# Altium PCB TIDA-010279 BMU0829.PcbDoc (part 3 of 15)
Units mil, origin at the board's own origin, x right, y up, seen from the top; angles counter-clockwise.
Board outline 11269.69 x 4438.98 mil, 4 copper layers (Top Layer, Signal Layer 1, Signal Layer 2, Bottom Layer), stack 61.6 mil thick; 1437 components, 728 nets, 3667 pads, 2806 vias.

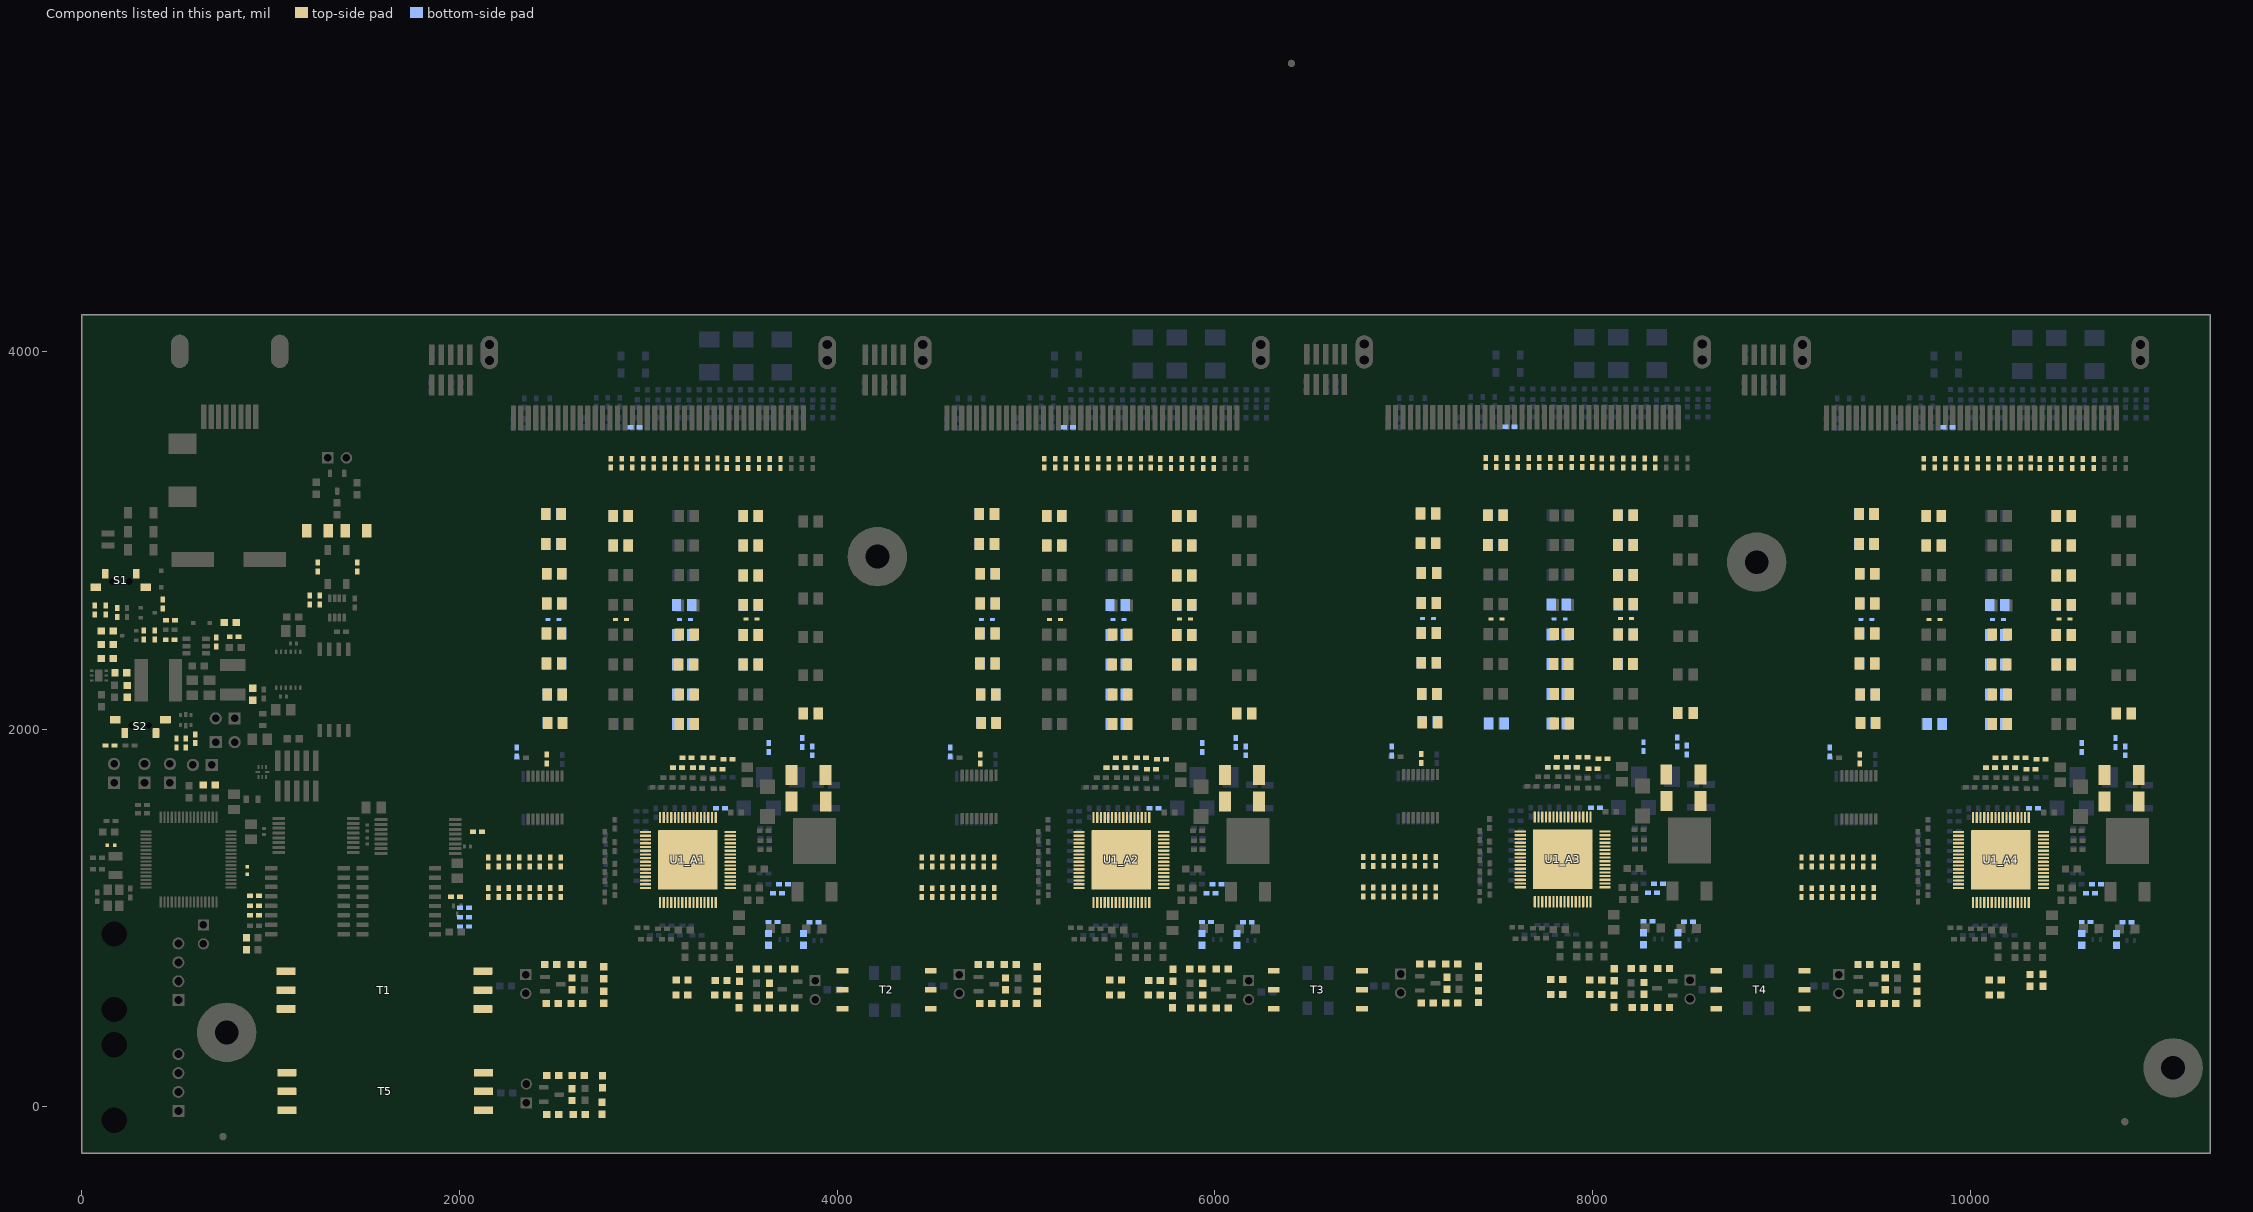
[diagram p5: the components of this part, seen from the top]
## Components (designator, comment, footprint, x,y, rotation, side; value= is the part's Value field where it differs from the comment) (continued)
R38_A3 "CRCW080568R0JNEA" 0805_HV 7490.51,2029.14 r0 bottom value=68 (schematic designator R38)
R38_A4 "CRCW080568R0JNEA" 0805_HV 9810.74,2025.93 r0 bottom value=68 (schematic designator R38)
R39_A1 "CRCW080568R0JNEA" 0805_HV 3189.11,2656.12 r0 bottom value=68 (schematic designator R39)
R39_A2 "CRCW080568R0JNEA" 0805_HV 5484.12,2656.12 r0 bottom value=68 (schematic designator R39)
R39_A3 "CRCW080568R0JNEA" 0805_HV 7820.72,2659.32 r0 bottom value=68 (schematic designator R39)
R39_A4 "CRCW080568R0JNEA" 0805_HV 10140.95,2656.12 r0 bottom value=68 (schematic designator R39)
R40_A1 "CRCW080568R0JNEA" 0805_HV 3859.45,2081.65 r0 top value=68 (schematic designator R40)
R40_A2 "CRCW080568R0JNEA" 0805_HV 6154.47,2081.65 r0 top value=68 (schematic designator R40)
R40_A3 "CRCW080568R0JNEA" 0805_HV 8491.06,2084.86 r0 top value=68 (schematic designator R40)
R40_A4 "CRCW080568R0JNEA" 0805_HV 10811.29,2081.65 r0 top value=68 (schematic designator R40)
R41_A1 "CRCW04021K00FKED" 0402 3699.67,3405.51 r270 top value=1.00k (schematic designator R41)
R41_A2 "CRCW04021K00FKED" 0402 5994.68,3405.51 r270 top value=1.00k (schematic designator R41)
R41_A3 "CRCW04021K00FKED" 0402 8331.28,3408.72 r270 top value=1.00k (schematic designator R41)
R41_A4 "CRCW04021K00FKED" 0402 10651.51,3405.51 r270 top value=1.00k (schematic designator R41)
R42_A1 "CRCW080568R0JNEA" 0805_HV 2498.12,3138.62 r0 top value=68 (schematic designator R42)
R42_A2 "CRCW080568R0JNEA" 0805_HV 4793.14,3138.62 r0 top value=68 (schematic designator R42)
R42_A3 "CRCW080568R0JNEA" 0805_HV 7129.74,3141.83 r0 top value=68 (schematic designator R42)
R42_A4 "CRCW080568R0JNEA" 0805_HV 9449.97,3138.62 r0 top value=68 (schematic designator R42)
R43_A1 "CRCW080568R0JNEA" 0805_HV 3204.12,2500.26 r0 top value=68 (schematic designator R43)
R43_A2 "CRCW080568R0JNEA" 0805_HV 5499.14,2500.26 r0 top value=68 (schematic designator R43)
R43_A3 "CRCW080568R0JNEA" 0805_HV 7835.73,2503.47 r0 top value=68 (schematic designator R43)
R43_A4 "CRCW080568R0JNEA" 0805_HV 10155.96,2500.26 r0 top value=68 (schematic designator R43)
R44_A1 "CRCW080568R0JNEA" 0805_HV 3541.98,3128.75 r0 top value=68 (schematic designator R44)
R44_A2 "CRCW080568R0JNEA" 0805_HV 5836.99,3128.75 r0 top value=68 (schematic designator R44)
R44_A3 "CRCW080568R0JNEA" 0805_HV 8173.59,3131.96 r0 top value=68 (schematic designator R44)
R44_A4 "CRCW080568R0JNEA" 0805_HV 10493.82,3128.75 r0 top value=68 (schematic designator R44)
R45_A1 "CRCW080568R0JNEA" 0805_HV 2498.12,2980.51 r0 top value=68 (schematic designator R45)
R45_A2 "CRCW080568R0JNEA" 0805_HV 4793.14,2980.51 r0 top value=68 (schematic designator R45)
R45_A3 "CRCW080568R0JNEA" 0805_HV 7129.74,2983.72 r0 top value=68 (schematic designator R45)
R45_A4 "CRCW080568R0JNEA" 0805_HV 9449.97,2980.51 r0 top value=68 (schematic designator R45)
R46_A1 "CRCW080568R0JNEA" 0805_HV 3189.11,2498.57 r0 bottom value=68 (schematic designator R46)
R46_A2 "CRCW080568R0JNEA" 0805_HV 5484.12,2498.57 r0 bottom value=68 (schematic designator R46)
R46_A3 "CRCW080568R0JNEA" 0805_HV 7820.72,2501.78 r0 bottom value=68 (schematic designator R46)
R46_A4 "CRCW080568R0JNEA" 0805_HV 10140.95,2498.57 r0 bottom value=68 (schematic designator R46)
R47_A1 "CRCW080568R0JNEA" 0805_HV 3541.98,2971.21 r0 top value=68 (schematic designator R47)
R47_A2 "CRCW080568R0JNEA" 0805_HV 5836.99,2971.21 r0 top value=68 (schematic designator R47)
R47_A3 "CRCW080568R0JNEA" 0805_HV 8173.59,2974.42 r0 top value=68 (schematic designator R47)
R47_A4 "CRCW080568R0JNEA" 0805_HV 10493.82,2971.21 r0 top value=68 (schematic designator R47)
R48_A1 "CRCW080568R0JNEA" 0805_HV 2495.94,3138.62 r0 bottom value=68 (schematic designator R48)
R48_A2 "CRCW080568R0JNEA" 0805_HV 4790.96,3138.62 r0 bottom value=68 (schematic designator R48)
R48_A3 "CRCW080568R0JNEA" 0805_HV 7127.56,3141.83 r0 bottom value=68 (schematic designator R48)
R48_A4 "CRCW080568R0JNEA" 0805_HV 9447.79,3138.62 r0 bottom value=68 (schematic designator R48)
R49_A1 "CRCW080568R0JNEA" 0805_HV 3189.11,2341.02 r0 bottom value=68 (schematic designator R49)
R49_A2 "CRCW080568R0JNEA" 0805_HV 5484.12,2341.02 r0 bottom value=68 (schematic designator R49)
R49_A3 "CRCW080568R0JNEA" 0805_HV 7820.72,2344.23 r0 bottom value=68 (schematic designator R49)
R49_A4 "CRCW080568R0JNEA" 0805_HV 10140.95,2341.02 r0 bottom value=68 (schematic designator R49)
R50_A1 "CRCW080568R0JNEA" 0805_HV 3543.08,3128.75 r0 bottom value=68 (schematic designator R50)
R50_A2 "CRCW080568R0JNEA" 0805_HV 5838.1,3128.75 r0 bottom value=68 (schematic designator R50)
R50_A3 "CRCW080568R0JNEA" 0805_HV 8174.69,3131.96 r0 bottom value=68 (schematic designator R50)
R50_A4 "CRCW080568R0JNEA" 0805_HV 10494.92,3128.75 r0 bottom value=68 (schematic designator R50)
R51_A1 "CRCW04021K00FKED" 0402 3642.8,3405.51 r270 top value=1.00k (schematic designator R51)
R51_A2 "CRCW04021K00FKED" 0402 5937.82,3405.51 r270 top value=1.00k (schematic designator R51)
R51_A3 "CRCW04021K00FKED" 0402 8274.41,3408.72 r270 top value=1.00k (schematic designator R51)
R51_A4 "CRCW04021K00FKED" 0402 10594.64,3405.51 r270 top value=1.00k (schematic designator R51)
R52_A1 "CRCW080568R0JNEA" 0805_HV 2495.94,2980.51 r0 bottom value=68 (schematic designator R52)
R52_A2 "CRCW080568R0JNEA" 0805_HV 4790.96,2980.51 r0 bottom value=68 (schematic designator R52)
R52_A3 "CRCW080568R0JNEA" 0805_HV 7127.56,2983.72 r0 bottom value=68 (schematic designator R52)
R52_A4 "CRCW080568R0JNEA" 0805_HV 9447.79,2980.51 r0 bottom value=68 (schematic designator R52)
R53_A1 "CRCW080568R0JNEA" 0805_HV 3201.6,2341.02 r0 top value=68 (schematic designator R53)
R53_A2 "CRCW080568R0JNEA" 0805_HV 5496.62,2341.02 r0 top value=68 (schematic designator R53)
R53_A3 "CRCW080568R0JNEA" 0805_HV 7833.21,2344.23 r0 top value=68 (schematic designator R53)
R53_A4 "CRCW080568R0JNEA" 0805_HV 10153.44,2341.02 r0 top value=68 (schematic designator R53)
R54_A1 "CRCW080568R0JNEA" 0805_HV 3543.08,2971.21 r0 bottom value=68 (schematic designator R54)
R54_A2 "CRCW080568R0JNEA" 0805_HV 5838.1,2971.21 r0 bottom value=68 (schematic designator R54)
R54_A3 "CRCW080568R0JNEA" 0805_HV 8174.69,2974.42 r0 bottom value=68 (schematic designator R54)
R54_A4 "CRCW080568R0JNEA" 0805_HV 10494.92,2971.21 r0 bottom value=68 (schematic designator R54)
R55_A1 "CRCW080568R0JNEA" 0805_HV 2501.64,2822.4 r0 top value=68 (schematic designator R55)
R55_A2 "CRCW080568R0JNEA" 0805_HV 4796.66,2822.4 r0 top value=68 (schematic designator R55)
R55_A3 "CRCW080568R0JNEA" 0805_HV 7133.26,2825.61 r0 top value=68 (schematic designator R55)
R55_A4 "CRCW080568R0JNEA" 0805_HV 9453.49,2822.4 r0 top value=68 (schematic designator R55)
R56_A1 "CRCW080568R0JNEA" 0805_HV 3204.12,2183.48 r0 top value=68 (schematic designator R56)
R56_A2 "CRCW080568R0JNEA" 0805_HV 5499.14,2183.48 r0 top value=68 (schematic designator R56)
R56_A3 "CRCW080568R0JNEA" 0805_HV 7835.73,2186.69 r0 top value=68 (schematic designator R56)
R56_A4 "CRCW080568R0JNEA" 0805_HV 10155.96,2183.48 r0 top value=68 (schematic designator R56)
R57_A1 "CRCW080568R0JNEA" 0805_HV 3542.76,2658.37 r0 top value=68 (schematic designator R57)
R57_A2 "CRCW080568R0JNEA" 0805_HV 5837.78,2658.37 r0 top value=68 (schematic designator R57)
R57_A3 "CRCW080568R0JNEA" 0805_HV 8174.38,2661.58 r0 top value=68 (schematic designator R57)
R57_A4 "CRCW080568R0JNEA" 0805_HV 10494.6,2658.37 r0 top value=68 (schematic designator R57)
R58_A1 "CRCW080568R0JNEA" 0805_HV 2501.39,2822.4 r0 bottom value=68 (schematic designator R58)
R58_A2 "CRCW080568R0JNEA" 0805_HV 4796.41,2822.4 r0 bottom value=68 (schematic designator R58)
R58_A3 "CRCW080568R0JNEA" 0805_HV 7133.01,2825.61 r0 bottom value=68 (schematic designator R58)
R58_A4 "CRCW080568R0JNEA" 0805_HV 9453.24,2822.4 r0 bottom value=68 (schematic designator R58)
R59_A1 "CRCW080568R0JNEA" 0805_HV 3203.57,2025.93 r0 top value=68 (schematic designator R59)
R59_A2 "CRCW080568R0JNEA" 0805_HV 5498.58,2025.93 r0 top value=68 (schematic designator R59)
R59_A3 "CRCW080568R0JNEA" 0805_HV 7835.18,2029.14 r0 top value=68 (schematic designator R59)
R59_A4 "CRCW080568R0JNEA" 0805_HV 10155.41,2025.93 r0 top value=68 (schematic designator R59)
R60_A1 "CRCW080568R0JNEA" 0805_HV 3543.08,2656.12 r0 bottom value=68 (schematic designator R60)
R60_A2 "CRCW080568R0JNEA" 0805_HV 5838.1,2656.12 r0 bottom value=68 (schematic designator R60)
R60_A3 "CRCW080568R0JNEA" 0805_HV 8174.69,2659.32 r0 bottom value=68 (schematic designator R60)
R60_A4 "CRCW080568R0JNEA" 0805_HV 10494.92,2656.12 r0 bottom value=68 (schematic designator R60)
R61_A1 "CRCW04021K00FKED" 0402 3585.93,3405.51 r270 top value=1.00k (schematic designator R61)
R61_A2 "CRCW04021K00FKED" 0402 5880.95,3405.51 r270 top value=1.00k (schematic designator R61)
R61_A3 "CRCW04021K00FKED" 0402 8217.54,3408.72 r270 top value=1.00k (schematic designator R61)
R61_A4 "CRCW04021K00FKED" 0402 10537.77,3405.51 r270 top value=1.00k (schematic designator R61)
R62_A1 "CRCW080568R0JNEA" 0805_HV 2501.11,2664.29 r0 top value=68 (schematic designator R62)
R62_A2 "CRCW080568R0JNEA" 0805_HV 4796.13,2664.29 r0 top value=68 (schematic designator R62)
R62_A3 "CRCW080568R0JNEA" 0805_HV 7132.73,2667.5 r0 top value=68 (schematic designator R62)
R62_A4 "CRCW080568R0JNEA" 0805_HV 9452.96,2664.29 r0 top value=68 (schematic designator R62)
R63_A1 "CRCW080568R0JNEA" 0805_HV 3189.11,2025.93 r0 bottom value=68 (schematic designator R63)
R63_A2 "CRCW080568R0JNEA" 0805_HV 5484.12,2025.93 r0 bottom value=68 (schematic designator R63)
R63_A3 "CRCW080568R0JNEA" 0805_HV 7820.72,2029.14 r0 bottom value=68 (schematic designator R63)
R63_A4 "CRCW080568R0JNEA" 0805_HV 10140.95,2025.93 r0 bottom value=68 (schematic designator R63)
R64_A1 "CRCW080568R0JNEA" 0805_HV 3541.98,2813.66 r0 top value=68 (schematic designator R64)
R64_A2 "CRCW080568R0JNEA" 0805_HV 5836.99,2813.66 r0 top value=68 (schematic designator R64)
R64_A3 "CRCW080568R0JNEA" 0805_HV 8173.59,2816.87 r0 top value=68 (schematic designator R64)
R64_A4 "CRCW080568R0JNEA" 0805_HV 10493.82,2813.66 r0 top value=68 (schematic designator R64)
R65_A1 "CRCW04021K00FKED" 0402 3529.06,3405.51 r270 top value=1.00k (schematic designator R65)
R65_A2 "CRCW04021K00FKED" 0402 5824.08,3405.51 r270 top value=1.00k (schematic designator R65)
R65_A3 "CRCW04021K00FKED" 0402 8160.68,3408.72 r270 top value=1.00k (schematic designator R65)
R65_A4 "CRCW04021K00FKED" 0402 10480.91,3405.51 r270 top value=1.00k (schematic designator R65)
R66_A1 "CRCW080568R0JNEA" 0805_HV 2501.39,2664.29 r0 bottom value=68 (schematic designator R66)
R66_A2 "CRCW080568R0JNEA" 0805_HV 4796.41,2664.29 r0 bottom value=68 (schematic designator R66)
R66_A3 "CRCW080568R0JNEA" 0805_HV 7133.01,2667.5 r0 bottom value=68 (schematic designator R66)
R66_A4 "CRCW080568R0JNEA" 0805_HV 9453.24,2664.29 r0 bottom value=68 (schematic designator R66)
R67_A1 "CRCW080568R0JNEA" 0805_HV 3189.11,2183.48 r0 bottom value=68 (schematic designator R67)
R67_A2 "CRCW080568R0JNEA" 0805_HV 5484.12,2183.48 r0 bottom value=68 (schematic designator R67)
R67_A3 "CRCW080568R0JNEA" 0805_HV 7820.72,2186.69 r0 bottom value=68 (schematic designator R67)
R67_A4 "CRCW080568R0JNEA" 0805_HV 10140.95,2183.48 r0 bottom value=68 (schematic designator R67)
R68_A1 "CRCW080568R0JNEA" 0805_HV 3543.08,2813.66 r0 bottom value=68 (schematic designator R68)
R68_A2 "CRCW080568R0JNEA" 0805_HV 5838.1,2813.66 r0 bottom value=68 (schematic designator R68)
R68_A3 "CRCW080568R0JNEA" 0805_HV 8174.69,2816.87 r0 bottom value=68 (schematic designator R68)
R68_A4 "CRCW080568R0JNEA" 0805_HV 10494.92,2813.66 r0 bottom value=68 (schematic designator R68)
R69_A1 "CRCW080568R0JNEA" 0805_HV 2500.37,2506.18 r0 top value=68 (schematic designator R69)
R69_A2 "CRCW080568R0JNEA" 0805_HV 4795.39,2506.18 r0 top value=68 (schematic designator R69)
R69_A3 "CRCW080568R0JNEA" 0805_HV 7131.98,2509.39 r0 top value=68 (schematic designator R69)
R69_A4 "CRCW080568R0JNEA" 0805_HV 9452.21,2506.18 r0 top value=68 (schematic designator R69)
R70_A1 "CRCW080568R0JNEA" 0805_HV 2854.76,3128.75 r0 bottom value=68 (schematic designator R70)
R70_A2 "CRCW080568R0JNEA" 0805_HV 5149.78,3128.75 r0 bottom value=68 (schematic designator R70)
R70_A3 "CRCW080568R0JNEA" 0805_HV 7486.37,3131.96 r0 bottom value=68 (schematic designator R70)
R70_A4 "CRCW080568R0JNEA" 0805_HV 9806.6,3128.75 r0 bottom value=68 (schematic designator R70)
R71_A1 "CRCW080568R0JNEA" 0805_HV 3543.08,2341.02 r0 bottom value=68 (schematic designator R71)
R71_A2 "CRCW080568R0JNEA" 0805_HV 5838.1,2341.02 r0 bottom value=68 (schematic designator R71)
R71_A3 "CRCW080568R0JNEA" 0805_HV 8174.69,2344.23 r0 bottom value=68 (schematic designator R71)
R71_A4 "CRCW080568R0JNEA" 0805_HV 10494.92,2341.02 r0 bottom value=68 (schematic designator R71)
R72_A1 "CRCW080568R0JNEA" 0805_HV 2501.39,2505.07 r0 bottom value=68 (schematic designator R72)
R72_A2 "CRCW080568R0JNEA" 0805_HV 4796.41,2505.07 r0 bottom value=68 (schematic designator R72)
R72_A3 "CRCW080568R0JNEA" 0805_HV 7133.01,2508.28 r0 bottom value=68 (schematic designator R72)
R72_A4 "CRCW080568R0JNEA" 0805_HV 9453.24,2505.07 r0 bottom value=68 (schematic designator R72)
R73_A1 "CRCW080568R0JNEA" 0805_HV 2853.39,3128.75 r0 top value=68 (schematic designator R73)
R73_A2 "CRCW080568R0JNEA" 0805_HV 5148.41,3128.75 r0 top value=68 (schematic designator R73)
R73_A3 "CRCW080568R0JNEA" 0805_HV 7485,3131.96 r0 top value=68 (schematic designator R73)
R73_A4 "CRCW080568R0JNEA" 0805_HV 9805.23,3128.75 r0 top value=68 (schematic designator R73)
R74_A1 "CRCW080568R0JNEA" 0805_HV 3541.29,2341.02 r0 top value=68 (schematic designator R74)
R74_A2 "CRCW080568R0JNEA" 0805_HV 5836.3,2341.02 r0 top value=68 (schematic designator R74)
R74_A3 "CRCW080568R0JNEA" 0805_HV 8172.9,2344.23 r0 top value=68 (schematic designator R74)
R74_A4 "CRCW080568R0JNEA" 0805_HV 10493.13,2341.02 r0 top value=68 (schematic designator R74)
R75_A1 "CRCW04021K00FKED" 0402 3472.2,3405.51 r270 top value=1.00k (schematic designator R75)
R75_A2 "CRCW04021K00FKED" 0402 5767.21,3405.51 r270 top value=1.00k (schematic designator R75)
R75_A3 "CRCW04021K00FKED" 0402 8103.81,3408.72 r270 top value=1.00k (schematic designator R75)
R75_A4 "CRCW04021K00FKED" 0402 10424.04,3405.51 r270 top value=1.00k (schematic designator R75)
R76_A1 "CRCW080568R0JNEA" 0805_HV 2501.39,2348.07 r0 bottom value=68 (schematic designator R76)
R76_A2 "CRCW080568R0JNEA" 0805_HV 4796.41,2348.07 r0 bottom value=68 (schematic designator R76)
R76_A3 "CRCW080568R0JNEA" 0805_HV 7133.01,2351.28 r0 bottom value=68 (schematic designator R76)
R76_A4 "CRCW080568R0JNEA" 0805_HV 9453.24,2348.07 r0 bottom value=68 (schematic designator R76)
R77_A1 "CRCW080568R0JNEA" 0805_HV 2854.76,2971.21 r0 bottom value=68 (schematic designator R77)
R77_A2 "CRCW080568R0JNEA" 0805_HV 5149.78,2971.21 r0 bottom value=68 (schematic designator R77)
R77_A3 "CRCW080568R0JNEA" 0805_HV 7486.37,2974.42 r0 bottom value=68 (schematic designator R77)
R77_A4 "CRCW080568R0JNEA" 0805_HV 9806.6,2971.21 r0 bottom value=68 (schematic designator R77)
R78_A1 "CRCW080568R0JNEA" 0805_HV 3542.76,2498.57 r0 top value=68 (schematic designator R78)
R78_A2 "CRCW080568R0JNEA" 0805_HV 5837.78,2498.57 r0 top value=68 (schematic designator R78)
R78_A3 "CRCW080568R0JNEA" 0805_HV 8174.38,2501.78 r0 top value=68 (schematic designator R78)
R78_A4 "CRCW080568R0JNEA" 0805_HV 10494.6,2498.57 r0 top value=68 (schematic designator R78)
R79_A1 "CRCW0402511RFKED" 0402 3366.1,3408.84 r90 top value=511 (schematic designator R79)
R79_A2 "CRCW0402511RFKED" 0402 5661.12,3408.84 r90 top value=511 (schematic designator R79)
R79_A3 "CRCW0402511RFKED" 0402 7997.72,3412.05 r90 top value=511 (schematic designator R79)
R79_A4 "CRCW0402511RFKED" 0402 10317.95,3408.84 r90 top value=511 (schematic designator R79)
R80_A1 "CRCW080568R0JNEA" 0805_HV 2500.37,2348.07 r0 top value=68 (schematic designator R80)
R80_A2 "CRCW080568R0JNEA" 0805_HV 4795.39,2348.07 r0 top value=68 (schematic designator R80)
R80_A3 "CRCW080568R0JNEA" 0805_HV 7131.98,2351.28 r0 top value=68 (schematic designator R80)
R80_A4 "CRCW080568R0JNEA" 0805_HV 9452.21,2348.07 r0 top value=68 (schematic designator R80)
R81_A1 "CRCW080568R0JNEA" 0805_HV 2853.39,2971.21 r0 top value=68 (schematic designator R81)
R81_A2 "CRCW080568R0JNEA" 0805_HV 5148.41,2971.21 r0 top value=68 (schematic designator R81)
R81_A3 "CRCW080568R0JNEA" 0805_HV 7485,2974.42 r0 top value=68 (schematic designator R81)
R81_A4 "CRCW080568R0JNEA" 0805_HV 9805.23,2971.21 r0 top value=68 (schematic designator R81)
R82_A1 "CRCW080568R0JNEA" 0805_HV 3543.08,2498.57 r0 bottom value=68 (schematic designator R82)
R82_A2 "CRCW080568R0JNEA" 0805_HV 5838.1,2498.57 r0 bottom value=68 (schematic designator R82)
R82_A3 "CRCW080568R0JNEA" 0805_HV 8174.69,2501.78 r0 bottom value=68 (schematic designator R82)
R82_A4 "CRCW080568R0JNEA" 0805_HV 10494.92,2498.57 r0 bottom value=68 (schematic designator R82)
R83_A1 "CRCW04021K00FKED" 0402 3415.33,3405.51 r270 top value=1.00k (schematic designator R83)
R83_A2 "CRCW04021K00FKED" 0402 5710.34,3405.51 r270 top value=1.00k (schematic designator R83)
R83_A3 "CRCW04021K00FKED" 0402 8046.94,3408.72 r270 top value=1.00k (schematic designator R83)
R83_A4 "CRCW04021K00FKED" 0402 10367.17,3405.51 r270 top value=1.00k (schematic designator R83)
R84_A1 "CRCW080568R0JNEA" 0805_HV 2506.8,2031.85 r0 top value=68 (schematic designator R84)
R84_A2 "CRCW080568R0JNEA" 0805_HV 4801.81,2031.85 r0 top value=68 (schematic designator R84)
R84_A3 "CRCW080568R0JNEA" 0805_HV 7138.41,2035.06 r0 top value=68 (schematic designator R84)
R84_A4 "CRCW080568R0JNEA" 0805_HV 9458.64,2031.85 r0 top value=68 (schematic designator R84)
R85_A1 "CRCW080568R0JNEA" 0805_HV 2504.54,2183.48 r0 bottom value=68 (schematic designator R85)
R85_A2 "CRCW080568R0JNEA" 0805_HV 4799.55,2183.48 r0 bottom value=68 (schematic designator R85)
R85_A3 "CRCW080568R0JNEA" 0805_HV 7136.15,2186.69 r0 bottom value=68 (schematic designator R85)
R85_A4 "CRCW080568R0JNEA" 0805_HV 9456.38,2183.48 r0 bottom value=68 (schematic designator R85)
R86_A1 "CRCW080568R0JNEA" 0805_HV 2503.71,2183.48 r0 top value=68 (schematic designator R86)
R86_A2 "CRCW080568R0JNEA" 0805_HV 4798.73,2183.48 r0 top value=68 (schematic designator R86)
R86_A3 "CRCW080568R0JNEA" 0805_HV 7135.32,2186.69 r0 top value=68 (schematic designator R86)
R86_A4 "CRCW080568R0JNEA" 0805_HV 9455.55,2183.48 r0 top value=68 (schematic designator R86)
R87_A1 "CRCW080568R0JNEA" 0805_HV 2504.54,2033.6 r0 bottom value=68 (schematic designator R87)
R87_A2 "CRCW080568R0JNEA" 0805_HV 4799.55,2033.6 r0 bottom value=68 (schematic designator R87)
R87_A3 "CRCW080568R0JNEA" 0805_HV 7136.15,2036.8 r0 bottom value=68 (schematic designator R87)
R87_A4 "CRCW080568R0JNEA" 0805_HV 9456.38,2033.6 r0 bottom value=68 (schematic designator R87)
R88 "ERJ-2GEJ473X" FP-ERJ-2GEJ473X_0402-MFG 875.98,1250.49 r270 top value=47k
R90_A1 "CRCW04021K00FKED" 0402 3313.38,3407.63 r270 top value=1.00k (schematic designator R90)
R90_A2 "CRCW04021K00FKED" 0402 5608.4,3407.63 r270 top value=1.00k (schematic designator R90)
R90_A3 "CRCW04021K00FKED" 0402 7945,3410.84 r270 top value=1.00k (schematic designator R90)
R90_A4 "CRCW04021K00FKED" 0402 10265.23,3407.63 r270 top value=1.00k (schematic designator R90)
R100_A1 "CRCW04021K00FKED" 0402 3256.52,3407.63 r270 top value=1.00k (schematic designator R100)
R100_A2 "CRCW04021K00FKED" 0402 5551.53,3407.63 r270 top value=1.00k (schematic designator R100)
R100_A3 "CRCW04021K00FKED" 0402 7888.13,3410.84 r270 top value=1.00k (schematic designator R100)
R100_A4 "CRCW04021K00FKED" 0402 10208.36,3407.63 r270 top value=1.00k (schematic designator R100)
R104_A1 "CRCW04021K00FKED" 0402 3199.65,3407.63 r270 top value=1.00k (schematic designator R104)
R104_A2 "CRCW04021K00FKED" 0402 5494.66,3407.63 r270 top value=1.00k (schematic designator R104)
R104_A3 "CRCW04021K00FKED" 0402 7831.26,3410.84 r270 top value=1.00k (schematic designator R104)
R104_A4 "CRCW04021K00FKED" 0402 10151.49,3407.63 r270 top value=1.00k (schematic designator R104)
R114_A1 "CRCW04021K00FKED" 0402 3142.78,3407.63 r270 top value=1.00k (schematic designator R114)
R114_A2 "CRCW04021K00FKED" 0402 5437.8,3407.63 r270 top value=1.00k (schematic designator R114)
R114_A3 "CRCW04021K00FKED" 0402 7774.39,3410.84 r270 top value=1.00k (schematic designator R114)
R114_A4 "CRCW04021K00FKED" 0402 10094.62,3407.63 r270 top value=1.00k (schematic designator R114)
R121_A1 "CRCW04023K30JNED" 0402 3660.84,978.59 r0 bottom value=3.3k (schematic designator R121)
R121_A2 "CRCW04023K30JNED" 0402 5955.86,978.59 r0 bottom value=3.3k (schematic designator R121)
R121_A3 "CRCW04023K30JNED" 0402 8292.46,981.79 r0 bottom value=3.3k (schematic designator R121)
R121_A4 "CRCW04023K30JNED" 0402 10612.69,978.59 r0 bottom value=3.3k (schematic designator R121)
R122_A1 "CRCW04023K30JNED" 0402 3876.11,977.11 r0 bottom value=3.3k (schematic designator R122)
R122_A2 "CRCW04023K30JNED" 0402 6171.13,977.11 r0 bottom value=3.3k (schematic designator R122)
R122_A3 "CRCW04023K30JNED" 0402 8507.73,980.32 r0 bottom value=3.3k (schematic designator R122)
R122_A4 "CRCW04023K30JNED" 0402 10827.96,977.11 r0 bottom value=3.3k (schematic designator R122)
R126_A1 "CRCW04021K00FKED" 0402 3085.91,3407.63 r270 top value=1.00k (schematic designator R126)
R126_A2 "CRCW04021K00FKED" 0402 5380.93,3407.63 r270 top value=1.00k (schematic designator R126)
R126_A3 "CRCW04021K00FKED" 0402 7717.52,3410.84 r270 top value=1.00k (schematic designator R126)
R126_A4 "CRCW04021K00FKED" 0402 10037.75,3407.63 r270 top value=1.00k (schematic designator R126)
R128_A1 "CRCW04021K00FKED" 0402 3029.04,3407.63 r270 top value=1.00k (schematic designator R128)
R128_A2 "CRCW04021K00FKED" 0402 5324.06,3407.63 r270 top value=1.00k (schematic designator R128)
R128_A3 "CRCW04021K00FKED" 0402 7660.66,3410.84 r270 top value=1.00k (schematic designator R128)
R128_A4 "CRCW04021K00FKED" 0402 9980.89,3407.63 r270 top value=1.00k (schematic designator R128)
R132_A1 "CRCW04021K00FKED" 0402 2972.18,3407.63 r270 top value=1.00k (schematic designator R132)
R132_A2 "CRCW04021K00FKED" 0402 5267.19,3407.63 r270 top value=1.00k (schematic designator R132)
R132_A3 "CRCW04021K00FKED" 0402 7603.79,3410.84 r270 top value=1.00k (schematic designator R132)
R132_A4 "CRCW04021K00FKED" 0402 9924.02,3407.63 r270 top value=1.00k (schematic designator R132)
R135_A1 "CRCW04021K00FKED" 0402 2915.31,3407.63 r270 top value=1.00k (schematic designator R135)
R135_A2 "CRCW04021K00FKED" 0402 5210.32,3407.63 r270 top value=1.00k (schematic designator R135)
R135_A3 "CRCW04021K00FKED" 0402 7546.92,3410.84 r270 top value=1.00k (schematic designator R135)
R135_A4 "CRCW04021K00FKED" 0402 9867.15,3407.63 r270 top value=1.00k (schematic designator R135)
R136_A1 "CRCW060310M0JNEA" 0603 3637.22,886.3 r270 bottom value=10Meg (schematic designator R136)
R136_A2 "CRCW060310M0JNEA" 0603 5932.24,886.3 r270 bottom value=10Meg (schematic designator R136)
R136_A3 "CRCW060310M0JNEA" 0603 8268.83,889.51 r270 bottom value=10Meg (schematic designator R136)
R136_A4 "CRCW060310M0JNEA" 0603 10589.06,886.3 r270 bottom value=10Meg (schematic designator R136)
R137_A1 "CRCW060310M0JNEA" 0603 3821,886.3 r270 bottom value=10Meg (schematic designator R137)
R137_A2 "CRCW060310M0JNEA" 0603 6116.01,886.3 r270 bottom value=10Meg (schematic designator R137)
R137_A3 "CRCW060310M0JNEA" 0603 8452.61,889.51 r270 bottom value=10Meg (schematic designator R137)
R137_A4 "CRCW060310M0JNEA" 0603 10772.84,886.3 r270 bottom value=10Meg (schematic designator R137)
R138_A1 "CRCW04021K00FKED" 0402 2858.44,3407.63 r270 top value=1.00k (schematic designator R138)
R138_A2 "CRCW04021K00FKED" 0402 5153.46,3407.63 r270 top value=1.00k (schematic designator R138)
R138_A3 "CRCW04021K00FKED" 0402 7490.05,3410.84 r270 top value=1.00k (schematic designator R138)
R138_A4 "CRCW04021K00FKED" 0402 9810.28,3407.63 r270 top value=1.00k (schematic designator R138)
R139_A1 "CRCW04021K00FKED" 0402 2801.57,3407.63 r270 top value=1.00k (schematic designator R139)
R139_A2 "CRCW04021K00FKED" 0402 5096.59,3407.63 r270 top value=1.00k (schematic designator R139)
R139_A3 "CRCW04021K00FKED" 0402 7433.19,3410.84 r270 top value=1.00k (schematic designator R139)
R139_A4 "CRCW04021K00FKED" 0402 9753.42,3407.63 r270 top value=1.00k (schematic designator R139)
R140_A1 "CRCW04020000Z0ED" 0402 2929.95,3597.76 r0 bottom value=0 (schematic designator R140)
R140_A2 "CRCW04020000Z0ED" 0402 5224.97,3597.76 r0 bottom value=0 (schematic designator R140)
R140_A3 "CRCW04020000Z0ED" 0402 7561.56,3600.97 r0 bottom value=0 (schematic designator R140)
R140_A4 "CRCW04020000Z0ED" 0402 9881.79,3597.76 r0 bottom value=0 (schematic designator R140)
R144_A1 "CRCW040210K0FKED" 0402 2153.54,1133.86 r270 top value=10.0k (schematic designator R144)
R144_A2 "CRCW040210K0FKED" 0402 4448.56,1133.86 r270 top value=10.0k (schematic designator R144)
R144_A3 "CRCW040210K0FKED" 0402 6785.15,1137.07 r270 top value=10.0k (schematic designator R144)
R144_A4 "CRCW040210K0FKED" 0402 9105.38,1133.86 r270 top value=10.0k (schematic designator R144)
R145_A1 "CRCW04021K00JNED" 0402 2153.54,1295.8 r270 top value=1.0k (schematic designator R145)
R145_A2 "CRCW04021K00JNED" 0402 4448.56,1295.8 r270 top value=1.0k (schematic designator R145)
R145_A3 "CRCW04021K00JNED" 0402 6785.15,1299.01 r270 top value=1.0k (schematic designator R145)
R145_A4 "CRCW04021K00JNED" 0402 9105.38,1295.8 r270 top value=1.0k (schematic designator R145)
R146_A1 "CRCW040210K0FKED" 0402 2316.07,1135.05 r270 top value=10.0k (schematic designator R146)
R146_A2 "CRCW040210K0FKED" 0402 4611.09,1135.05 r270 top value=10.0k (schematic designator R146)
R146_A3 "CRCW040210K0FKED" 0402 6947.69,1138.26 r270 top value=10.0k (schematic designator R146)
R146_A4 "CRCW040210K0FKED" 0402 9267.92,1135.05 r270 top value=10.0k (schematic designator R146)
R147_A1 "CRCW040210K0FKED" 0402 2207.17,1133.73 r270 top value=10.0k (schematic designator R147)
R147_A2 "CRCW040210K0FKED" 0402 4502.19,1133.73 r270 top value=10.0k (schematic designator R147)
R147_A3 "CRCW040210K0FKED" 0402 6838.78,1136.94 r270 top value=10.0k (schematic designator R147)
R147_A4 "CRCW040210K0FKED" 0402 9159.01,1133.73 r270 top value=10.0k (schematic designator R147)
R148_A1 "CRCW04021K00JNED" 0402 2303.15,1879.92 r270 bottom value=1.0k (schematic designator R148)
R148_A2 "CRCW04021K00JNED" 0402 4598.17,1879.92 r270 bottom value=1.0k (schematic designator R148)
R148_A3 "CRCW04021K00JNED" 0402 6934.76,1883.13 r270 bottom value=1.0k (schematic designator R148)
R148_A4 "CRCW04021K00JNED" 0402 9254.99,1879.92 r270 bottom value=1.0k (schematic designator R148)
R149_A1 "CRCW04021K00JNED" 0402 2316.07,1296.98 r270 top value=1.0k (schematic designator R149)
R149_A2 "CRCW04021K00JNED" 0402 4611.09,1296.98 r270 top value=1.0k (schematic designator R149)
R149_A3 "CRCW04021K00JNED" 0402 6947.69,1300.19 r270 top value=1.0k (schematic designator R149)
R149_A4 "CRCW04021K00JNED" 0402 9267.92,1296.98 r270 top value=1.0k (schematic designator R149)
R150_A1 "CRCW04021K00JNED" 0402 2207.17,1295.66 r270 top value=1.0k (schematic designator R150)
R150_A2 "CRCW04021K00JNED" 0402 4502.19,1295.66 r270 top value=1.0k (schematic designator R150)
R150_A3 "CRCW04021K00JNED" 0402 6838.78,1298.87 r270 top value=1.0k (schematic designator R150)
R150_A4 "CRCW04021K00JNED" 0402 9159.01,1295.66 r270 top value=1.0k (schematic designator R150)
R151_A1 "CRCW04021K00JNED" 0402 2461.06,1841.08 r270 top value=1.0k (schematic designator R151)
R151_A2 "CRCW04021K00JNED" 0402 4756.08,1841.08 r270 top value=1.0k (schematic designator R151)
R151_A3 "CRCW04021K00JNED" 0402 7092.67,1844.28 r270 top value=1.0k (schematic designator R151)
R151_A4 "CRCW04021K00JNED" 0402 9412.9,1841.08 r270 top value=1.0k (schematic designator R151)
R152_A1 "CRCW040210K0FKED" 0402 2536.11,1135.05 r270 top value=10.0k (schematic designator R152)
R152_A2 "CRCW040210K0FKED" 0402 4831.12,1135.05 r270 top value=10.0k (schematic designator R152)
R152_A3 "CRCW040210K0FKED" 0402 7167.72,1138.26 r270 top value=10.0k (schematic designator R152)
R152_A4 "CRCW040210K0FKED" 0402 9487.95,1135.05 r270 top value=10.0k (schematic designator R152)
R153_A1 "CRCW04021K00JNED" 0402 2536.11,1296.98 r270 top value=1.0k (schematic designator R153)
R153_A2 "CRCW04021K00JNED" 0402 4831.12,1296.98 r270 top value=1.0k (schematic designator R153)
R153_A3 "CRCW04021K00JNED" 0402 7167.72,1300.19 r270 top value=1.0k (schematic designator R153)
R153_A4 "CRCW04021K00JNED" 0402 9487.95,1296.98 r270 top value=1.0k (schematic designator R153)
R154_A1 "CRCW2010100RFKEF" 2010 3848.55,1616.25 r180 top value=100 (schematic designator R154)
R154_A2 "CRCW2010100RFKEF" 2010 6143.57,1616.25 r180 top value=100 (schematic designator R154)
R154_A3 "CRCW2010100RFKEF" 2010 8480.17,1619.46 r180 top value=100 (schematic designator R154)
R154_A4 "CRCW2010100RFKEF" 2010 10800.4,1616.25 r180 top value=100 (schematic designator R154)
R155_A1 "CRCW2010200RFKEF" 2010 3848.43,1756.24 r0 top value=200 (schematic designator R155)
R155_A2 "CRCW2010200RFKEF" 2010 6143.44,1756.24 r0 top value=200 (schematic designator R155)
R155_A3 "CRCW2010200RFKEF" 2010 8480.04,1759.45 r0 top value=200 (schematic designator R155)
R155_A4 "CRCW2010200RFKEF" 2010 10800.27,1756.24 r0 top value=200 (schematic designator R155)
R156_A1 "CRCW040210K0FKED" 0402 2481.1,1135.05 r270 top value=10.0k (schematic designator R156)
R156_A2 "CRCW040210K0FKED" 0402 4776.11,1135.05 r270 top value=10.0k (schematic designator R156)
R156_A3 "CRCW040210K0FKED" 0402 7112.71,1138.26 r270 top value=10.0k (schematic designator R156)
R156_A4 "CRCW040210K0FKED" 0402 9432.94,1135.05 r270 top value=10.0k (schematic designator R156)
R157_A1 "CRCW04021K00JNED" 0402 2481.1,1296.98 r270 top value=1.0k (schematic designator R157)
R157_A2 "CRCW04021K00JNED" 0402 4776.11,1296.98 r270 top value=1.0k (schematic designator R157)
R157_A3 "CRCW04021K00JNED" 0402 7112.71,1300.19 r270 top value=1.0k (schematic designator R157)
R157_A4 "CRCW04021K00JNED" 0402 9432.94,1296.98 r270 top value=1.0k (schematic designator R157)
R158_A1 "CRCW040210K0FKED" 0402 2426.09,1135.05 r270 top value=10.0k (schematic designator R158)
R158_A2 "CRCW040210K0FKED" 0402 4721.11,1135.05 r270 top value=10.0k (schematic designator R158)
R158_A3 "CRCW040210K0FKED" 0402 7057.7,1138.26 r270 top value=10.0k (schematic designator R158)
R158_A4 "CRCW040210K0FKED" 0402 9377.93,1135.05 r270 top value=10.0k (schematic designator R158)
R159_A1 "CRCW04021K00JNED" 0402 2426.09,1296.98 r270 top value=1.0k (schematic designator R159)
R159_A2 "CRCW04021K00JNED" 0402 4721.11,1296.98 r270 top value=1.0k (schematic designator R159)
R159_A3 "CRCW04021K00JNED" 0402 7057.7,1300.19 r270 top value=1.0k (schematic designator R159)
R159_A4 "CRCW04021K00JNED" 0402 9377.93,1296.98 r270 top value=1.0k (schematic designator R159)
R161_A1 "CRCW040210K0FKED" 0402 2261.06,1135.05 r270 top value=10.0k (schematic designator R161)
R161_A2 "CRCW040210K0FKED" 0402 4556.08,1135.05 r270 top value=10.0k (schematic designator R161)
R161_A3 "CRCW040210K0FKED" 0402 6892.68,1138.26 r270 top value=10.0k (schematic designator R161)
R161_A4 "CRCW040210K0FKED" 0402 9212.91,1135.05 r270 top value=10.0k (schematic designator R161)
R162_A1 "CRCW040210K0FKED" 0402 2371.08,1135.05 r270 top value=10.0k (schematic designator R162)
R162_A2 "CRCW040210K0FKED" 0402 4666.1,1135.05 r270 top value=10.0k (schematic designator R162)
R162_A3 "CRCW040210K0FKED" 0402 7002.69,1138.26 r270 top value=10.0k (schematic designator R162)
R162_A4 "CRCW040210K0FKED" 0402 9322.92,1135.05 r270 top value=10.0k (schematic designator R162)
R164_A1 "CRCW04021K00JNED" 0402 2261.06,1296.98 r270 top value=1.0k (schematic designator R164)
R164_A2 "CRCW04021K00JNED" 0402 4556.08,1296.98 r270 top value=1.0k (schematic designator R164)
R164_A3 "CRCW04021K00JNED" 0402 6892.68,1300.19 r270 top value=1.0k (schematic designator R164)
R164_A4 "CRCW04021K00JNED" 0402 9212.91,1296.98 r270 top value=1.0k (schematic designator R164)
R165_A1 "CRCW04021K00JNED" 0402 2371.08,1296.98 r270 top value=1.0k (schematic designator R165)
R165_A2 "CRCW04021K00JNED" 0402 4666.1,1296.98 r270 top value=1.0k (schematic designator R165)
R165_A3 "CRCW04021K00JNED" 0402 7002.69,1300.19 r270 top value=1.0k (schematic designator R165)
R165_A4 "CRCW04021K00JNED" 0402 9322.92,1296.98 r270 top value=1.0k (schematic designator R165)
R177_A1 "RC0603JR-070RL" 0603 2484.19,753.36 r0 top value=0 (schematic designator R177)
R177_A2 "RC0603JR-070RL" 0603 4779.2,753.36 r0 top value=0 (schematic designator R177)
R177_A3 "RC0603JR-070RL" 0603 7115.8,756.57 r0 top value=0 (schematic designator R177)
R177_A4 "RC0603JR-070RL" 0603 9436.03,753.36 r0 top value=0 (schematic designator R177)
R178_A1 "CRCW060351R0JNEA" 0603 2621.98,753.36 r0 top value=51 (schematic designator R178)
R178_A2 "CRCW060351R0JNEA" 0603 4917,753.36 r0 top value=51 (schematic designator R178)
R178_A3 "CRCW060351R0JNEA" 0603 7253.59,756.57 r0 top value=51 (schematic designator R178)
R178_A4 "CRCW060351R0JNEA" 0603 9573.82,753.36 r0 top value=51 (schematic designator R178)
R179_A1 "ERJ-3GEY0R00V" 0603 3178.54,671.95 r0 top value=0 (schematic designator R179)
R179_A2 "ERJ-3GEY0R00V" 0603 5473.56,671.95 r0 top value=0 (schematic designator R179)
R179_A3 "ERJ-3GEY0R00V" 0603 7810.15,675.15 r0 top value=0 (schematic designator R179)
R179_A4 "ERJ-3GEY0R00V" 0603 10130.38,671.95 r0 top value=0 (schematic designator R179)
R180_A1 "ERJ-3GEY0R00V" 0603 3384.92,668.03 r0 top value=0 (schematic designator R180)
R180_A2 "ERJ-3GEY0R00V" 0603 5679.93,668.03 r0 top value=0 (schematic designator R180)
R180_A3 "ERJ-3GEY0R00V" 0603 8016.53,671.24 r0 top value=0 (schematic designator R180)
R180_A4 "ERJ-3GEY0R00V" 0603 10384.26,670.01 r270 top value=0 (schematic designator R180)
R181_A1 "CRCW060351R0JNEA" 0603 3603.03,729.57 r0 top value=51 (schematic designator R181)
R181_A2 "CRCW060351R0JNEA" 0603 5898.05,729.57 r0 top value=51 (schematic designator R181)
R181_A3 "CRCW060351R0JNEA" 0603 8234.64,732.78 r0 top value=51 (schematic designator R181)
R181_A4 "CRCW060351R0JNEA" 0603 2634.1,-40.59 r180 top value=51 (schematic designator R181)
R182_A1 "RC0603JR-070RL" 0603 3743.26,729.57 r0 top value=0 (schematic designator R182)
R182_A2 "RC0603JR-070RL" 0603 6038.28,729.57 r0 top value=0 (schematic designator R182)
R182_A3 "RC0603JR-070RL" 0603 8374.88,732.78 r0 top value=0 (schematic designator R182)
R182_A4 "RC0603JR-070RL" 0603 2493.87,-40.59 r180 top value=0 (schematic designator R182)
R184_A1 "CRCW0603510RJNEA" 0603 2764.06,710.76 r90 top value=510 (schematic designator R184)
R184_A2 "CRCW0603510RJNEA" 0603 5059.08,710.76 r90 top value=510 (schematic designator R184)
R184_A3 "CRCW0603510RJNEA" 0603 7395.67,713.97 r90 top value=510 (schematic designator R184)
R184_A4 "CRCW0603510RJNEA" 0603 9715.9,710.76 r90 top value=510 (schematic designator R184)
R185_A1 "CRCW0603510RJNEA" 0603 3482.42,696.7 r90 top value=510 (schematic designator R185)
R185_A2 "CRCW0603510RJNEA" 0603 5777.44,696.7 r90 top value=510 (schematic designator R185)
R185_A3 "CRCW0603510RJNEA" 0603 8114.03,699.91 r90 top value=510 (schematic designator R185)
R185_A4 "CRCW0603510RJNEA" 0603 2754.71,-7.72 r270 top value=510 (schematic designator R185)
R186_A1 "ERJ-3EKF1001V" 0603 2596.75,650.63 r90 top value=1.00k (schematic designator R186)
R186_A2 "ERJ-3EKF1001V" 0603 4891.77,650.63 r90 top value=1.00k (schematic designator R186)
R186_A3 "ERJ-3EKF1001V" 0603 7228.37,653.84 r90 top value=1.00k (schematic designator R186)
R186_A4 "ERJ-3EKF1001V" 0603 9548.6,650.63 r90 top value=1.00k (schematic designator R186)
R187_A1 "ERJ-3EKF1001V" 0603 3640.36,623.73 r90 top value=1.00k (schematic designator R187)
R187_A2 "ERJ-3EKF1001V" 0603 5935.38,623.73 r90 top value=1.00k (schematic designator R187)
R187_A3 "ERJ-3EKF1001V" 0603 8271.97,626.94 r90 top value=1.00k (schematic designator R187)
R187_A4 "ERJ-3EKF1001V" 0603 2596.77,65.24 r270 top value=1.00k (schematic designator R187)
R188_A1 "CRCW0603510RJNEA" 0603 2764.06,580.84 r90 top value=510 (schematic designator R188)
R188_A2 "CRCW0603510RJNEA" 0603 5059.08,580.84 r90 top value=510 (schematic designator R188)
R188_A3 "CRCW0603510RJNEA" 0603 7395.67,584.05 r90 top value=510 (schematic designator R188)
R188_A4 "CRCW0603510RJNEA" 0603 9715.9,580.84 r90 top value=510 (schematic designator R188)
R189_A1 "CRCW0603510RJNEA" 0603 3480.39,555.83 r90 top value=510 (schematic designator R189)
R189_A2 "CRCW0603510RJNEA" 0603 5775.4,555.83 r90 top value=510 (schematic designator R189)
R189_A3 "CRCW0603510RJNEA" 0603 8112,559.04 r90 top value=510 (schematic designator R189)
R189_A4 "CRCW0603510RJNEA" 0603 2756.75,133.15 r270 top value=510 (schematic designator R189)
R190_A1 "RC0603JR-070RL" 0603 2492.06,546.67 r0 top value=0 (schematic designator R190)
R190_A2 "RC0603JR-070RL" 0603 4787.08,546.67 r0 top value=0 (schematic designator R190)
R190_A3 "RC0603JR-070RL" 0603 7123.67,549.88 r0 top value=0 (schematic designator R190)
R190_A4 "RC0603JR-070RL" 0603 9443.9,546.67 r0 top value=0 (schematic designator R190)
R191_A1 "CRCW060351R0JNEA" 0603 2621.98,546.67 r0 top value=51 (schematic designator R191)
R191_A2 "CRCW060351R0JNEA" 0603 4917,546.67 r0 top value=51 (schematic designator R191)
R191_A3 "CRCW060351R0JNEA" 0603 7253.59,549.88 r0 top value=51 (schematic designator R191)
R191_A4 "CRCW060351R0JNEA" 0603 9573.82,546.67 r0 top value=51 (schematic designator R191)
R192_A1 "ERJ-3GEY0R00V" 0603 3178.03,591.38 r0 top value=0 (schematic designator R192)
R192_A2 "ERJ-3GEY0R00V" 0603 5473.05,591.38 r0 top value=0 (schematic designator R192)
R192_A3 "ERJ-3GEY0R00V" 0603 7809.64,594.59 r0 top value=0 (schematic designator R192)
R192_A4 "ERJ-3GEY0R00V" 0603 10129.87,591.38 r0 top value=0 (schematic designator R192)
R193_A1 "ERJ-3GEY0R00V" 0603 3383.86,591.78 r0 top value=0 (schematic designator R193)
R193_A2 "ERJ-3GEY0R00V" 0603 5678.87,591.78 r0 top value=0 (schematic designator R193)
R193_A3 "ERJ-3GEY0R00V" 0603 8015.47,594.99 r0 top value=0 (schematic designator R193)
R193_A4 "ERJ-3GEY0R00V" 0603 10314.96,669.29 r270 top value=0 (schematic designator R193)
R194_A1 "CRCW060351R0JNEA" 0603 3608.86,522.34 r0 top value=51 (schematic designator R194)
R194_A2 "CRCW060351R0JNEA" 0603 5903.88,522.34 r0 top value=51 (schematic designator R194)
R194_A3 "CRCW060351R0JNEA" 0603 8240.48,525.55 r0 top value=51 (schematic designator R194)
R194_A4 "CRCW060351R0JNEA" 0603 2628.27,166.64 r180 top value=51 (schematic designator R194)
R195_A1 "RC0603JR-070RL" 0603 3743.26,522.34 r0 top value=0 (schematic designator R195)
R195_A2 "RC0603JR-070RL" 0603 6038.28,522.34 r0 top value=0 (schematic designator R195)
R195_A3 "RC0603JR-070RL" 0603 8374.88,525.55 r0 top value=0 (schematic designator R195)
R195_A4 "RC0603JR-070RL" 0603 2493.87,166.64 r180 top value=0 (schematic designator R195)
R196_A1 "CRCW04020000Z0ED" 0402 3153.96,1795.9 r180 bottom value=0 (schematic designator R196)
R196_A2 "CRCW04020000Z0ED" 0402 5448.97,1795.9 r180 bottom value=0 (schematic designator R196)
R196_A3 "CRCW04020000Z0ED" 0402 7785.57,1799.11 r180 bottom value=0 (schematic designator R196)
R196_A4 "CRCW04020000Z0ED" 0402 10105.8,1795.9 r180 bottom value=0 (schematic designator R196)
R197_A1 "CRCW04020000Z0ED" 0402 3260.84,1794.94 r180 bottom value=0 (schematic designator R197)
R197_A2 "CRCW04020000Z0ED" 0402 5555.86,1794.94 r180 bottom value=0 (schematic designator R197)
R197_A3 "CRCW04020000Z0ED" 0402 7892.45,1798.14 r180 bottom value=0 (schematic designator R197)
R197_A4 "CRCW04020000Z0ED" 0402 10212.68,1794.94 r180 bottom value=0 (schematic designator R197)
R198_A1 "CRCW04020000Z0ED" 0402 3867.28,1885.13 r90 bottom value=0 (schematic designator R198)
R198_A2 "CRCW04020000Z0ED" 0402 6162.3,1885.13 r90 bottom value=0 (schematic designator R198)
R198_A3 "CRCW04020000Z0ED" 0402 8498.9,1888.34 r90 bottom value=0 (schematic designator R198)
R198_A4 "CRCW04020000Z0ED" 0402 10819.13,1885.13 r90 bottom value=0 (schematic designator R198)
R199_A1 "CRCW04020000Z0ED" 0402 3153.96,1795.9 r180 top value=0 (schematic designator R199)
R199_A2 "CRCW04020000Z0ED" 0402 5448.97,1795.9 r180 top value=0 (schematic designator R199)
R199_A3 "CRCW04020000Z0ED" 0402 7785.57,1799.11 r180 top value=0 (schematic designator R199)
R199_A4 "CRCW04020000Z0ED" 0402 10105.8,1795.9 r180 top value=0 (schematic designator R199)
R200_A1 "CRCW04020000Z0ED" 0402 3259.28,1795.9 r180 top value=0 (schematic designator R200)
R200_A2 "CRCW04020000Z0ED" 0402 5554.3,1795.9 r180 top value=0 (schematic designator R200)
R200_A3 "CRCW04020000Z0ED" 0402 7890.9,1799.11 r180 top value=0 (schematic designator R200)
R200_A4 "CRCW04020000Z0ED" 0402 10211.13,1795.9 r180 top value=0 (schematic designator R200)
R201_A1 "CRCW04020000Z0ED" 0402 3368.95,1787.63 r180 top value=0 (schematic designator R201)
R201_A2 "CRCW04020000Z0ED" 0402 5663.97,1787.63 r180 top value=0 (schematic designator R201)
R201_A3 "CRCW04020000Z0ED" 0402 8000.56,1790.84 r180 top value=0 (schematic designator R201)
R201_A4 "CRCW04020000Z0ED" 0402 10320.79,1787.63 r180 top value=0 (schematic designator R201)
R202_A1 "CRCW04020000Z0ED" 0402 3637.13,1903.4 r90 bottom value=0 (schematic designator R202)
R202_A2 "CRCW04020000Z0ED" 0402 5932.15,1903.4 r90 bottom value=0 (schematic designator R202)
R202_A3 "CRCW04020000Z0ED" 0402 8268.74,1906.61 r90 bottom value=0 (schematic designator R202)
R202_A4 "CRCW04020000Z0ED" 0402 10588.97,1903.4 r90 bottom value=0 (schematic designator R202)
R203_A1 "CRCW04020000Z0ED" 0402 3815.95,1929 r90 bottom value=0 (schematic designator R203)
R203_A2 "CRCW04020000Z0ED" 0402 6110.97,1929 r90 bottom value=0 (schematic designator R203)
R203_A3 "CRCW04020000Z0ED" 0402 8447.57,1932.21 r90 bottom value=0 (schematic designator R203)
R203_A4 "CRCW04020000Z0ED" 0402 10767.8,1929 r90 bottom value=0 (schematic designator R203)
R204_A1 "CRCW04020000Z0ED" 0402 3382.18,1580.59 r180 bottom value=0 (schematic designator R204)
R204_A2 "CRCW04020000Z0ED" 0402 5677.2,1580.59 r180 bottom value=0 (schematic designator R204)
R204_A3 "CRCW04020000Z0ED" 0402 8013.79,1583.79 r180 bottom value=0 (schematic designator R204)
R204_A4 "CRCW04020000Z0ED" 0402 10334.02,1580.59 r180 bottom value=0 (schematic designator R204)
R205_A1 "CRCW04020000Z0ED" 0402 3203.8,1847.08 r180 top value=0 (schematic designator R205)
R205_A2 "CRCW04020000Z0ED" 0402 5498.81,1847.08 r180 top value=0 (schematic designator R205)
R205_A3 "CRCW04020000Z0ED" 0402 7835.41,1850.29 r180 top value=0 (schematic designator R205)
R205_A4 "CRCW04020000Z0ED" 0402 10155.64,1847.08 r180 top value=0 (schematic designator R205)
R206_A1 "CRCW04020000Z0ED" 0402 3316.48,1847.08 r180 top value=0 (schematic designator R206)
R206_A2 "CRCW04020000Z0ED" 0402 5611.5,1847.08 r180 top value=0 (schematic designator R206)
R206_A3 "CRCW04020000Z0ED" 0402 7948.09,1850.29 r180 top value=0 (schematic designator R206)
R206_A4 "CRCW04020000Z0ED" 0402 10268.32,1847.08 r180 top value=0 (schematic designator R206)
R207_A1 "CRCW04020000Z0ED" 0402 3422.48,1839.56 r180 top value=0 (schematic designator R207)
R207_A2 "CRCW04020000Z0ED" 0402 5717.5,1839.56 r180 top value=0 (schematic designator R207)
R207_A3 "CRCW04020000Z0ED" 0402 8054.09,1842.77 r180 top value=0 (schematic designator R207)
R207_A4 "CRCW04020000Z0ED" 0402 10374.32,1839.56 r180 top value=0 (schematic designator R207)
R208 "CRCW04020000Z0ED" 0402 2027.56,1053.15 r180 bottom value=0
R209 "CRCW04020000Z0ED" 0402 2027.56,1003.94 r180 bottom value=0
R210 "CRCW04020000Z0ED" 0402 2027.56,954.72 r180 bottom value=0
R211 "CRCW04020000Z0ED" 0402 2096.46,1456.69 r180 top value=0
R214 "CRCW040247K0JNED" 0402 149.73,1913.14 r180 top value=47k
R215_A1 "CRCW0402100KFKED" 0402 3716.01,1177.81 r180 bottom value=100k (schematic designator R215)
R215_A2 "CRCW0402100KFKED" 0402 6011.03,1177.81 r180 bottom value=100k (schematic designator R215)
R215_A3 "CRCW0402100KFKED" 0402 8347.62,1181.02 r180 bottom value=100k (schematic designator R215)
R215_A4 "CRCW0402100KFKED" 0402 10667.85,1177.81 r180 bottom value=100k (schematic designator R215)
R216 "CRCW04020000Z0ED" 0402 69.98,2629.86 r90 top value=0
R218 "CRCW0402118KFKED" 0402 807.3,2488.31 r0 top value=118k
R219 "CRCW040222K1FKED" 0402 711.87,2460.21 r90 top value=22.1k
R220 "CRCW06030000Z0EA" 0603 785.65,2564.71 r180 top value=0
R223 "RC0603JR-070RL" 0603 674.85,1703.38 r0 top value=0
R226 "CRCW0402220RJNED" 0402 600.39,1948.82 r90 top value=220
R227 "CRCW0402330RJNED" 0402 550.99,1925.69 r90 top value=330
R228 "CRCW0402330RJNED" 0402 501.9,1926.28 r90 top value=330
R229 "ERA-2AEB104X" FP-ERA-2AEB104X_0402-MFG 155.48,1385.02 r180 top
R230 "CRCW060310K0JNEA" 0603 134.97,2447.34 r180 top value=10k
R231 "CRCW060310K0JNEA" 0603 134.97,2519.54 r180 top value=10k
R232 "CRCW060310K0JNEA" 0603 134.37,2374.6 r180 top value=10k
R233 "CRCW040210K0JNED" 0402 328.74,2497.89 r90 top value=10k
R234 "CRCW040210K0JNED" 0402 387.5,2497.89 r90 top value=10k
R235 "CRCW04023K30JNED" 0402 127.19,2629.86 r270 top value=3.3k
R236 "CRCW0402100KJNED" 0402 188.77,2618.05 r90 top value=100k
R237 "CRCW06030000Z0EA" 0603 241.27,2199.16 r90 top value=0
R238 "CRCW06030000Z0EA" 0603 207.77,2298.46 r0 top value=0
R240 "CRCW04021K00JNED" 0402 428.12,2661.42 r270 top value=1.0k
R241 "CRCW04021K00JNED" 0402 468.51,2473.5 r0 top value=1.0k
R244 "CRCW040210K0JNED" 0402 470.48,2576.52 r180 top value=10k
R246 "CRCW060318K2FKEA" 0603 905.51,2185.04 r90 top value=18.2k
R247 "CRCW060318K2FKEA" 0603 871.88,863.32 r90 top value=18.2k
R248 "CRCW04020000Z0ED" 0402 1250.51,2857.79 r90 top value=0
R249 "ERJ-8ENF60R4V" 1206 1247.78,3050.2 r180 top value=60.4
R250 "CRCW04020000Z0ED" 0402 914.06,1013.54 r180 top value=0
R251 "CRCW04020000Z0ED" 0402 914.06,1063.54 r0 top value=0
R252 "ERJ-8ENF60R4V" 1206 1451.61,3050.2 r180 top value=60.4
R253 "CRCW04020000Z0ED" 0402 914.06,1117.03 r0 top value=0
R254 "CRCW04020000Z0ED" 0402 1457.91,2857.46 r90 top value=0
R255 "ERJ-2RKF2201X" 0402 1260.35,2683.66 r270 top value=2.20k
R256 "ERJ-2RKF2201X" 0402 1206.74,2683.66 r270 top value=2.20k
R257_A1 "CRCW0402100KFKED" 0402 3684.47,1130.99 r0 bottom value=100k (schematic designator R257)
R257_A2 "CRCW0402100KFKED" 0402 5979.48,1130.99 r0 bottom value=100k (schematic designator R257)
R257_A3 "CRCW0402100KFKED" 0402 8316.08,1134.2 r0 bottom value=100k (schematic designator R257)
R257_A4 "CRCW0402100KFKED" 0402 10636.31,1130.99 r0 bottom value=100k (schematic designator R257)
R258 "CRCW040210K0JNED" 0402 1978.35,1112.2 r0 top value=10k
RT1_A1 "TMP6131DYAT" DYA0002A-MFG 2854.78,2580.3 r180 top value=10k (schematic designator RT1)
RT1_A2 "TMP6131DYAT" DYA0002A-MFG 5153.73,2580.3 r180 top value=10k (schematic designator RT1)
RT1_A3 "TMP6131DYAT" DYA0002A-MFG 7490.33,2583.51 r180 top value=10k (schematic designator RT1)
RT1_A4 "TMP6131DYAT" DYA0002A-MFG 9810.56,2580.3 r180 top value=10k (schematic designator RT1)
RT2_A1 "TMP6131DYAT" DYA0002A-MFG 2496.83,2581.17 r0 bottom value=10k (schematic designator RT2)
RT2_A2 "TMP6131DYAT" DYA0002A-MFG 4791.85,2581.17 r0 bottom value=10k (schematic designator RT2)
RT2_A3 "TMP6131DYAT" DYA0002A-MFG 7128.44,2584.37 r0 bottom value=10k (schematic designator RT2)
RT2_A4 "TMP6131DYAT" DYA0002A-MFG 9448.67,2581.17 r0 bottom value=10k (schematic designator RT2)
RT3_A1 "TMP6131DYAT" DYA0002A-MFG 3193.75,2580.76 r0 bottom value=10k (schematic designator RT3)
RT3_A2 "TMP6131DYAT" DYA0002A-MFG 5488.77,2580.76 r0 bottom value=10k (schematic designator RT3)
RT3_A3 "TMP6131DYAT" DYA0002A-MFG 7825.36,2583.97 r0 bottom value=10k (schematic designator RT3)
RT3_A4 "TMP6131DYAT" DYA0002A-MFG 10145.59,2580.76 r0 bottom value=10k (schematic designator RT3)
RT4_A1 "TMP6131DYAT" DYA0002A-MFG 3545.43,2582.39 r180 top value=10k (schematic designator RT4)
RT4_A2 "TMP6131DYAT" DYA0002A-MFG 5840.45,2582.39 r180 top value=10k (schematic designator RT4)
RT4_A3 "TMP6131DYAT" DYA0002A-MFG 8177.04,2585.59 r180 top value=10k (schematic designator RT4)
RT4_A4 "TMP6131DYAT" DYA0002A-MFG 10497.27,2582.39 r180 top value=10k (schematic designator RT4)
S1 "1188E-1K2-V-TR" SW_1188E 206.69,2795.28 r90 top
S2 "1188E-1K2-V-TR" SW_1188E 310.26,2006.63 r270 top
T1 "LKBMT10B" FP-LKBMT10B_SMT_XFRMR_27MM9_12MM5-MFG 1602.8,618.1 r0 top
T2 "74941301" FP-HMU1228NL_SMT_TRANSFORMER_8MM89_10MM09-MFG 4261.81,620.08 r0 top
T3 "74941301" FP-HMU1228NL_SMT_TRANSFORMER_8MM89_10MM09-MFG 6545.28,620.08 r0 top
T4 "74941301" FP-HMU1228NL_SMT_TRANSFORMER_8MM89_10MM09-MFG 8887.8,620.08 r0 top
T5 "LKBMT10B" FP-LKBMT10B_SMT_XFRMR_27MM9_12MM5-MFG 1606.74,81.48 r0 top
U1_A1 "BQ78706PAP" PAP0064N-MFG 3209.47,1306.96 r270 top (schematic designator U1)
U1_A2 "BQ78706PAP" PAP0064N-MFG 5504.48,1306.96 r270 top (schematic designator U1)
U1_A3 "BQ78706PAP" PAP0064N-MFG 7841.08,1310.16 r270 top (schematic designator U1)
U1_A4 "BQ78706PAP" PAP0064N-MFG 10161.31,1306.96 r270 top (schematic designator U1)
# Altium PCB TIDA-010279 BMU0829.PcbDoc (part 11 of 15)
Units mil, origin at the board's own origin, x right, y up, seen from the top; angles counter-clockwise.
Board outline 11269.69 x 4438.98 mil, 4 copper layers (Top Layer, Signal Layer 1, Signal Layer 2, Bottom Layer), stack 61.6 mil thick; 1437 components, 728 nets, 3667 pads, 2806 vias.

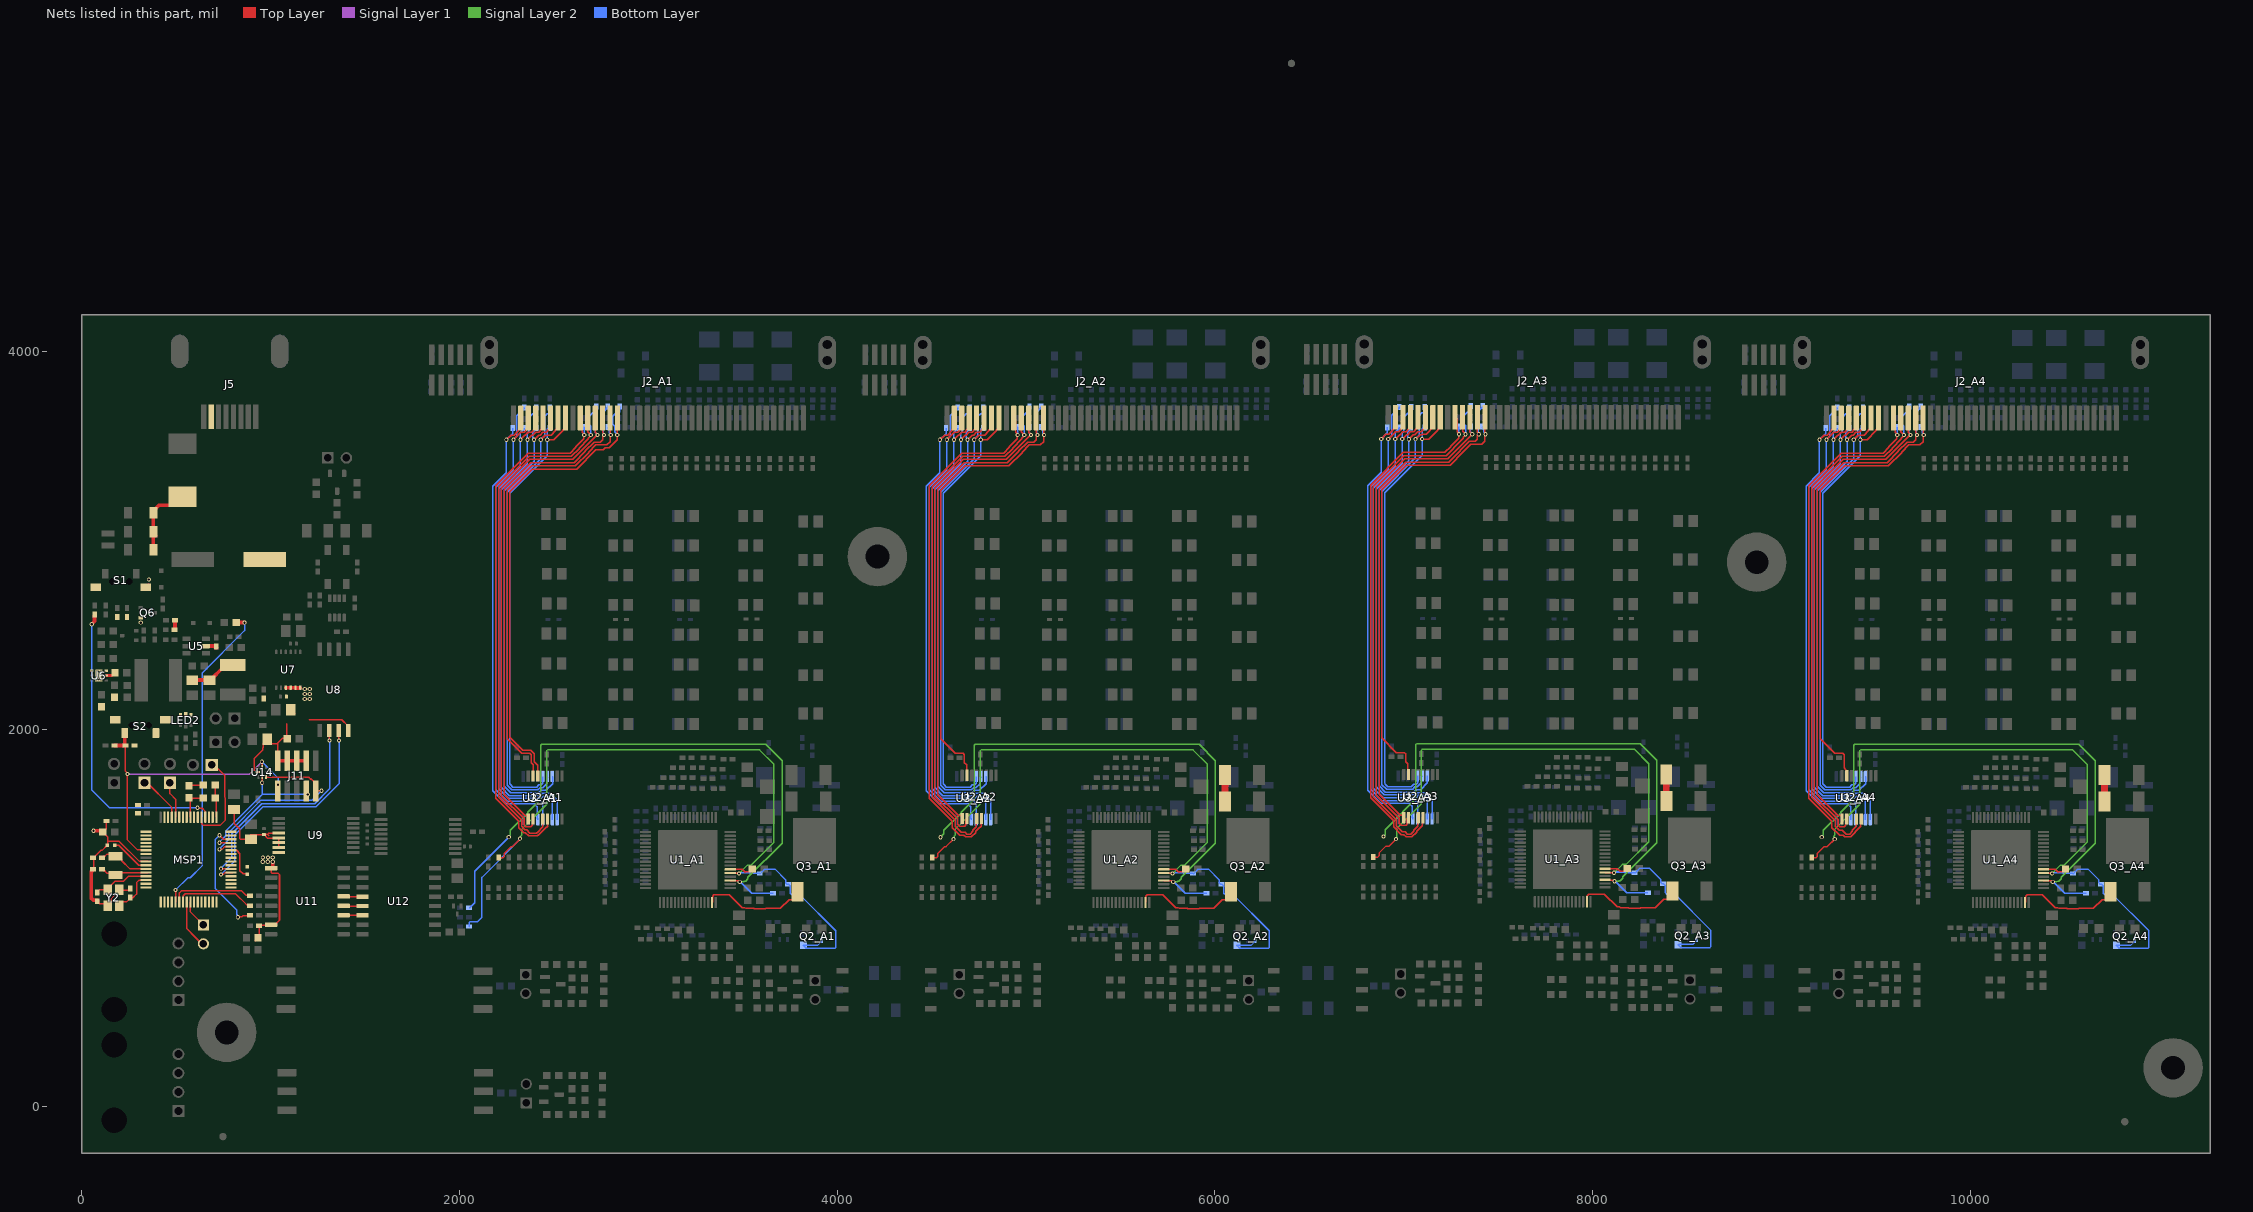
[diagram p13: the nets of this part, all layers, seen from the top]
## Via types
v1: diameter 22.01, hole 12.01, Top Layer to Bottom Layer, tented both sides, 2656 vias
v2: diameter 19.68, hole 7.87, Top Layer to Bottom Layer, tented both sides, 144 vias
v3: diameter 92.52, hole 49.21, Top Layer to Bottom Layer, 4 vias
v4: diameter 19.68, hole 7.87, Top Layer to Bottom Layer, 2 vias

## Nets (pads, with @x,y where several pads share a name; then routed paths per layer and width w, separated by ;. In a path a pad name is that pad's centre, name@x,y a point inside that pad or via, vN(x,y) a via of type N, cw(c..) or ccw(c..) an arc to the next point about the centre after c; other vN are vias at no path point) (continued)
NetR154_A2_2: R154_A2.2 R155_A2.1 | length 140
  Top Layer w35: R155_A2.1@6052.89,1756.24 6052.95,1756.17 R154_A2.2@6053.02,1616.25 R154_A2.2@6053.02,1616.25
NetR154_A3_2: R154_A3.2 R155_A3.1 | length 140
  Top Layer w35: R155_A3.1@8389.49,1759.45 8389.55,1759.38 R154_A3.2@8389.62,1619.46 R154_A3.2@8389.62,1619.46
NetR154_A4_2: R154_A4.2 R155_A4.1 | length 140
  Top Layer w35: R155_A4.1@10709.72,1756.24 10709.78,1756.17 R154_A4.2@10709.85,1616.25 R154_A4.2@10709.85,1616.25
NetR238_1: R238.1 U6.2 | length 53
  Top Layer w15: U6.2@129.57,2283.19 160.02,2283.19 175.29,2298.46 R238.1@176.27,2298.46
NetU11_3: U11.3 U12.14 | length 99.8
  Top Layer w8: U11.3@1386.71,1014.08 1387.46,1013.32 U12.14@1486.22,1013.32
NetU11_4: U11.4 U12.13 | length 99.8
  Top Layer w8: U11.4@1386.71,1064.08 1387.46,1063.32 U12.13@1486.22,1063.32
NetU11_5: U11.5 U12.12 | length 99.8
  Top Layer w8: U11.5@1386.71,1114.08 1387.46,1113.32 U12.12@1486.22,1113.32
NFAULT/GPIO2_A1: C114_A1.1 Q2_A1.1 R137_A1.2 R150_A1.1 R210.1 R215_A1.1 U1_A1.53 | length 4315.1
  Top Layer w8: R150_A1.1@2207.17,1319.29 2230.98,1319.29 2237.38,1325.68 2237.38,1341.27 2273.89,1377.78 2282.49,1377.78 2321.11,1416.41 v1(2321.11,1419.84) ; U1_A1.53@3433.88,1238.06 3434.96,1236.97 3479.5,1236.97 v1(3480.58,1235.89)
  Signal Layer 2 w8: v1(2321.11,1419.84) 2323.67,1422.4 2323.67,1432.31 2330.52,1439.16 2330.52,1470.84 2461.7,1602.02 2461.7,1884.88 2466.39,1889.57 3589.19,1889.57 3665.25,1813.51 3665.25,1400.54 3544.85,1280.14 3525.36,1280.14 3481.11,1235.89 v1(3480.58,1235.89)
  Bottom Layer w8: R210.1@2051.18,954.72 2051.18,975.57 2055.87,980.25 2095.43,980.25 2118.97,1003.79 2118.97,1214.26 2321.11,1416.41 v1(2321.11,1419.84) ; v1(3480.58,1235.89) 3484.37,1235.89 3488.64,1240.16 3534.8,1240.16 3539.07,1235.89 3589.32,1235.89 C114_A1.1@3589.84,1235.37 3593.78,1235.37 3609.46,1251.05 3609.46,1252.09 3616.42,1259.05 3670.17,1259.05 3727.88,1201.34 3727.88,1185.62 3735.7,1177.81 3743.57,1177.81 3751.38,1170 3751.38,1130.99 3760.41,1121.96 3803.31,1121.96 3992.69,932.59 3992.69,843.25 3988.01,838.57 3837.23,838.57 3836.68,839.12 3835.7,839.12 3821,853.82 R137_A1.2@3821,854.81 3822.94,856.75 3897.97,856.75 3917.32,876.1 Q2_A1.1@3917.32,881.62
NFAULT/GPIO2_A2: C114_A2.1 Q2_A2.1 R137_A2.2 R150_A2.1 R215_A2.1 U1_A2.53 | length 3714.4
  Top Layer w8: R150_A2.1@4502.19,1319.29 4526,1319.29 4532.4,1325.68 4532.4,1341.27 4568.91,1377.78 4576.01,1377.78 4615.54,1417.32 v1(4616.13,1417.32) ; U1_A2.53@5728.89,1238.06 5729.98,1236.97 5774.51,1236.97 v1(5775.6,1235.89)
  Signal Layer 2 w8: v1(4616.13,1417.32) 4618.69,1419.88 4618.69,1432.31 4625.54,1439.16 4625.54,1470.84 4756.72,1602.02 4756.72,1884.88 4761.4,1889.57 5884.21,1889.57 5960.27,1813.51 5960.27,1400.54 5839.87,1280.14 5820.38,1280.14 5776.12,1235.89 v1(5775.6,1235.89)
  Bottom Layer w8: v1(5775.6,1235.89) 5779.39,1235.89 5783.66,1240.16 5829.82,1240.16 5834.09,1235.89 5884.33,1235.89 C114_A2.1@5884.86,1235.37 5888.79,1235.37 5904.48,1251.05 5904.48,1252.09 5911.43,1259.05 5965.19,1259.05 6022.9,1201.34 6022.9,1185.62 6030.71,1177.81 6038.59,1177.81 6046.4,1170 6046.4,1130.99 6055.42,1121.96 6098.33,1121.96 6287.71,932.59 6287.71,843.25 6283.02,838.57 6132.25,838.57 6131.7,839.12 6130.71,839.12 6116.01,853.82 R137_A2.2@6116.01,854.81 6117.95,856.75 6192.98,856.75 6212.34,876.1 Q2_A2.1@6212.34,881.62
NFAULT/GPIO2_A3: C114_A3.1 Q2_A3.1 R137_A3.2 R150_A3.1 R215_A3.1 U1_A3.53 | length 3719.8
  Top Layer w8: R150_A3.1@6838.78,1322.49 6862.59,1322.49 6868.99,1328.89 6868.99,1344.48 6905.51,1380.99 6922.32,1380.99 v1(6958.65,1417.32) ; U1_A3.53@8065.49,1241.27 8066.57,1240.18 8111.11,1240.18 v1(8112.2,1239.1)
  Signal Layer 2 w8: v1(6958.65,1417.32) 6961.33,1420 6961.33,1443.52 6962.13,1444.32 6962.13,1474.05 7093.31,1605.23 7093.31,1888.09 7098,1892.78 8220.8,1892.78 8296.87,1816.71 8296.87,1403.75 8176.47,1283.35 8156.97,1283.35 8112.72,1239.1 v1(8112.2,1239.1)
  Bottom Layer w8: v1(8112.2,1239.1) 8115.99,1239.1 8120.26,1243.37 8166.42,1243.37 8170.69,1239.1 8220.93,1239.1 C114_A3.1@8221.45,1238.57 8225.39,1238.57 8241.08,1254.26 8241.08,1255.3 8248.03,1262.26 8301.78,1262.26 8359.5,1204.55 8359.5,1188.83 8367.31,1181.02 8375.18,1181.02 8382.99,1173.21 8382.99,1134.2 8392.02,1125.17 8434.93,1125.17 8624.31,935.79 8624.31,846.46 8619.62,841.78 8468.85,841.78 8468.29,842.33 8467.31,842.33 8452.61,857.03 R137_A3.2@8452.61,858.01 8454.55,859.96 8529.58,859.96 8548.94,879.31 Q2_A3.1@8548.94,884.82
NFAULT/GPIO2_A4: C114_A4.1 Q2_A4.1 R137_A4.2 R150_A4.1 R215_A4.1 U1_A4.53 | length 3724.3
  Top Layer w8: R150_A4.1@9159.01,1319.29 9182.82,1319.29 9189.22,1325.68 9189.22,1341.27 9225.74,1377.79 9241.94,1377.79 v1(9281.48,1417.32) ; U1_A4.53@10385.72,1238.06 10386.8,1236.97 10431.34,1236.97 v1(10432.43,1235.89)
  Signal Layer 2 w8: v1(9281.48,1417.32) 9278.8,1420 9278.8,1429.03 9275.52,1432.31 9282.36,1439.16 9282.36,1470.84 9413.54,1602.02 9413.54,1884.88 9418.23,1889.57 10541.03,1889.57 10617.1,1813.51 10617.1,1400.54 10496.7,1280.14 10477.2,1280.14 10432.95,1235.89 v1(10432.43,1235.89)
  Bottom Layer w8: v1(10432.43,1235.89) 10436.22,1235.89 10440.49,1240.16 10486.64,1240.16 10490.92,1235.89 10541.16,1235.89 C114_A4.1@10541.68,1235.37 10545.62,1235.37 10561.31,1251.05 10561.31,1252.09 10568.26,1259.05 10622.01,1259.05 10679.73,1201.34 10679.73,1185.62 10687.54,1177.81 10695.41,1177.81 10703.22,1170 10703.22,1130.99 10712.25,1121.96 10755.16,1121.96 10944.53,932.59 10944.53,843.25 10939.85,838.57 10789.08,838.57 10788.52,839.12 10787.54,839.12 10772.84,853.82 R137_A4.2@10772.84,854.81 10774.78,856.75 10849.81,856.75 10869.17,876.1 Q2_A4.1@10869.17,881.62
NPNB_A1: Q3_A1.1 U1_A1.47 | length 564.5
  Top Layer w7: U1_A1.47@3337.42,1082.55 3339.83,1084.95 3339.83,1115.64 3347.63,1123.45 3429.04,1123.45 3497.52,1054.96 3510.72,1054.96 3515.13,1050.55 3558.12,1050.55 3559.79,1048.88 3620.9,1048.88 3622.57,1050.55 3698.29,1050.55 3744.79,1097.05 3762.29,1097.05 3790.29,1125.04 Q3_A1.1@3790.29,1139.33
NPNB_A2: Q3_A2.1 U1_A2.47 | length 564.5
  Top Layer w7: U1_A2.47@5632.44,1082.55 5634.84,1084.95 5634.84,1115.64 5642.65,1123.45 5724.05,1123.45 5792.54,1054.96 5805.74,1054.96 5810.15,1050.55 5853.13,1050.55 5854.8,1048.88 5915.92,1048.88 5917.59,1050.55 5993.31,1050.55 6039.81,1097.05 6057.31,1097.05 6085.3,1125.04 Q3_A2.1@6085.3,1139.33
NPNB_A3: Q3_A3.1 U1_A3.47 | length 564.5
  Top Layer w7: U1_A3.47@7969.03,1085.75 7971.44,1088.16 7971.44,1118.85 7979.24,1126.66 8060.65,1126.66 8129.14,1058.17 8142.33,1058.17 8146.74,1053.76 8189.73,1053.76 8191.4,1052.09 8252.51,1052.09 8254.18,1053.76 8329.91,1053.76 8376.4,1100.26 8393.9,1100.26 8421.9,1128.25 Q3_A3.1@8421.9,1142.54
NPNB_A4: Q3_A4.1 U1_A4.47 | length 564.5
  Top Layer w7: U1_A4.47@10289.26,1082.55 10291.67,1084.95 10291.67,1115.64 10299.47,1123.45 10380.88,1123.45 10449.37,1054.96 10462.56,1054.96 10466.97,1050.55 10509.96,1050.55 10511.63,1048.88 10572.74,1048.88 10574.41,1050.55 10650.13,1050.55 10696.63,1097.05 10714.13,1097.05 10742.13,1125.04 Q3_A4.1@10742.13,1139.33
PA0: MSP1.33
PA1: MSP1.34
PA2_ROSC: MSP1.42 R229.1 | length 219.4
  Top Layer w8: R229.1@175.65,1385.02 196.48,1385.02 228.37,1353.13 228.37,1352.69 301.61,1279.45 MSP1.42@351.04,1279.45
PA3_LFXIN: C174.2 MSP1.43 Y1.2 | length 287.8
  Top Layer w8: C174.2@106.77,1318.58 114.58,1326.4 123.28,1326.4 123.51,1326.63 123.51,1328.25 131.66,1336.4 179.1,1336.4 194.78,1320.72 200.69,1320.72 212.5,1308.9 212.5,1303 255.74,1259.76 MSP1.43@351.04,1259.76
PA4_LFXOUT: C177.2 MSP1.44 Y1.1 | length 256
  Top Layer w8: C177.2@106.77,1258.51 114.35,1250.93 123.51,1250.93 123.51,1246.99 132.53,1237.98 179.1,1237.98 181.2,1240.08 MSP1.44@351.04,1240.08
PA5_HFXIN: C176.2 MSP1.45 Y2.3 | length 319.5
  Top Layer w8: C176.2@82.99,1135.81 82.99,1139.75 93.52,1150.28 Y2.3@136.77,1150.28 136.77,1155.2 176.18,1194.61 221.42,1194.61 247.2,1220.39 MSP1.45@351.04,1220.39 ; C176.2@84.03,1136.85 89.17,1131.71 C176.2@89.17,1127.78
PA6_HFXOUT: C175.2 MSP1.46 Y2.1 | length 253.5
  Top Layer w8: Y2.1@199.76,1063.66 199.76,1066.54 218.4,1085.18 236.76,1085.18 255.91,1104.33 C175.2@255.91,1108.27 263.28,1100.9 269.67,1107.29 270.71,1107.29 290.28,1126.86 290.28,1187.14 301.95,1198.8 349.13,1198.8 MSP1.46@351.04,1200.71
PA7_CLK-OUT: MSP1.49
PA8_UART1-TX: MSP1.54 R253.1 | length 437.7
  Top Layer w8: MSP1.54@516.39,1083.95 517.31,1084.88 517.31,1132.61 528.26,1143.56 846.31,1143.56 868.64,1121.22 886.24,1121.22 R253.1@890.44,1117.03
PA9_UART1-RX: MSP1.55 R251.1 | length 417.2
  Top Layer w8: MSP1.55@536.08,1084.56 537.98,1086.47 537.98,1117.87 547.79,1127.68 814.91,1127.68 871.88,1070.71 883.27,1070.71 R251.1@890.44,1063.54
PA10_UART0-TX: J16.2 MSP1.56 | length 269.7
  Top Layer w8: MSP1.56@555.76,1084.56 555.76,943.5 601.13,898.13 622.17,877.09 623.55,877.09 637.32,863.32 J16.2@651.13,863.32
PA11_UART0-RX: J16.1 MSP1.57 | length 149.8
  Top Layer w8: MSP1.57@575.45,1084.56 575.45,1032.22 J16.1@644.34,963.32
PA12_CAN-TX: MSP1.5 U8.3 | length 1255
  Top Layer w8: v1(737.05,1229.63) 739.73,1232.31 750.85,1232.31 756.71,1238.17 797.95,1238.17 MSP1.5@799.85,1240.08 ; U8.3@1360.2,1992.78 1361.28,1991.7 1361.28,1940.3 v1(1362.36,1939.22)
  Bottom Layer w8: v1(737.05,1229.63) 737.77,1229.63 810.12,1301.98 810.12,1439.62 959.41,1588.9 1240.1,1588.9 1362.36,1711.16 v1(1362.36,1939.22)
PA13_CAN-RX: MSP1.6 U8.2 | length 1195.7
  Top Layer w8: v1(737.05,1261.26) 738.55,1259.76 MSP1.6@790.01,1259.76 MSP1.6@799.85,1259.76 ; U8.2@1310.2,1992.78 1311.28,1991.7 1311.28,1940.3 v1(1312.36,1939.22)
  Bottom Layer w8: v1@737.87,1263.76 794.18,1320.07 794.18,1395.67 794.25,1395.74 794.25,1446.19 952.83,1604.78 1233.52,1604.78 1312.36,1683.61 v1(1312.36,1939.22)
PA14_TIMH0-C0: MSP1.7
PA15_DAC-OUT: MSP1.8
PA16_OPA1-OUT_ADC1.1: MSP1.9
PA17_OPA1-IN-_ADC1.2: MSP1.10
PA18_OPA1-IN+_ADC1.3_GPAMP-IN-: MSP1.11 R88.2 | length 164.8
  Top Layer w7: MSP1.11@816.93,1358.27 820.62,1358.27 837.86,1341.03 837.86,1250.92 855.64,1233.14 873.16,1233.14 R88.2@875.98,1230.32
PA19_SWDIO: J11.2 MSP1.12 U14.7 | length 1102.6
  Top Layer w8: v1@739.22,1363.16 742.34,1363.16 757.05,1377.87 MSP1.12@799.85,1377.87 ; U14.7@976.29,1746.24 976.29,1745.56 977.21,1744.64 1202.07,1744.64 1210.94,1735.77 1215.02,1735.77 1238.86,1711.93 J11.2@1238.86,1671.57 1240.55,1673.26 v1(1269.65,1673.26)
  Bottom Layer w8: v1@731.07,1369.02 732.67,1369.02 778.37,1414.73 778.37,1452.77 949.62,1624.02 1220.41,1624.02 v1(1269.65,1673.26)
  other v1: 729.38,1363.16
PA20_SWCLK: J11.4 MSP1.13 U14.6 | length 735.6
  Top Layer w8: v1@739.35,1398.21 739.67,1397.88 MSP1.13@766.39,1397.88 ; v1(955.36,1715.6) 956.54,1716.78 956.54,1746.18 U14.6@956.6,1746.24 ; J11.4@1188.86,1645.79 v1(1196.86,1653.79) 1188.86,1661.79 J11.4@1188.86,1671.57
  Bottom Layer w8: v1@732.18,1404.68 762.5,1435 762.5,1460.93 955.36,1653.79 ; v1(955.36,1715.6) 955.36,1653.79 ; v1(1196.86,1653.79) 955.36,1653.79
  other v1: 729.5,1398.21
PA21_VREF-: C172.2 MSP1.17 R223.2 | length 173
  Top Layer w8: R223.2@706.35,1703.38 706.35,1654.17 ; 706.45,1654.07 706.35,1654.17 ; MSP1.17@713.24,1533.38 713.24,1627.59 C172.2@706.35,1634.48 706.35,1654.17
PA22_OPA0-OUT_ADC0.7_GPAMP-OUT_COMP2-IN0+: MSP1.18
PA23_VREF+: C172.1 C173.1 MSP1.24 | length 174.6
  Top Layer w8: C173.1@568.65,1635.47 575.45,1628.67 575.45,1597.08 MSP1.24@575.45,1533.38 ; C173.1@585.29,1629.66 580.46,1634.48 C172.1@643.36,1634.48
PA24_OPA0-IN1-_ADC0.3: MSP1.25
PA25_OPA0-IN1+_ADC0.2: MSP1.26
PA26_OPA0-IN0+_GPAMP-IN+_COMP0-IN0+: MSP1.30
PA27_OPA0-IN0-_COMP0-IN0-_TIMA2_FAL: MSP1.31
PA28_TIMA2_C0: MSP1.35
PA29_TIMG10_C0: MSP1.36
PA30_TIMG10_C1: MSP1.37
PA31_TIMA2_C1: MSP1.39
PB0_SPI1-CS2: MSP1.47
PB1_TIMA1-C1: MSP1.48
PB2_I2C1-SCL: MSP1.50
PB3_I2C1-SDA: MSP1.51
PB4_TIMA1-C0: MSP1.52
PB5: MSP1.53 R220.1 | length 1684.5
  Top Layer w8: v1(496.71,1147.54) 496.71,1086.47 MSP1.53@498.61,1084.56
  Top Layer w20: R220.1@817.14,2564.71 860.85,2564.71 861.89,2563.67 v1(862.43,2563.67)
  Bottom Layer w8: v1(496.71,1147.54) 562.05,1212.89 574.4,1212.89 637.07,1275.56 637.07,2296.11 862.65,2521.69 862.65,2529.55 862.43,2529.77 v1(862.43,2563.67)
PB6_SPI1-CS0: MSP1.58
PB7_SPI1-POCI: MSP1.59
PB8_SPI1-PICO: MSP1.60
PB9_SPI1-SCK: MSP1.61
PB10_TIMG0-C0: MSP1.62
PB11_TIMG0-C1: MSP1.63
PB12_TIMA0-C2_TIMA1-FAL: MSP1.64
PB13_TIMA0-C3: MSP1.1
PB14_TIMG10_IDX: MSP1.2
PB15_UART2-TX_TIMG1-C0: MSP1.3
PB16_UART2-RX_TIMG1-C1: MSP1.4
PB17_ADC1.4_SPI1-CS1: MSP1.14 R250.2 | length 640.2
  Top Layer w8: v1(729.78,1438.25) 750.78,1417.24 MSP1.14@790.01,1417.24 MSP1.14@799.85,1417.24 ; v1(826.77,1003.94) 829.45,1006.62 847.37,1006.62 853.78,1013.02 889.93,1013.02 R250.2@890.44,1013.54
  Bottom Layer w8: v1(729.78,1438.25) 706.5,1414.97 706.5,1155.76 820.74,1041.52 820.74,1019.87 824.09,1016.52 824.09,1006.62 v1(826.77,1003.94)
PB18_ADC1.5: MSP1.15
PB19_OPA1-IN+_ADC1.6: MSP1.16
PB20_TIMA0-C2: MSP1.19
PB21: MSP1.20 R216.1 | length 1599.7
  Top Layer w8: v1(613.43,1583.56) 615.84,1581.15 637.82,1581.15 653.15,1565.82 MSP1.20@653.15,1544.26
  Top Layer w20: v1(52.79,2554.96) 52.79,2555.5 68.17,2570.88 68.17,2600.49 R216.1@69.98,2602.3
  Bottom Layer w8: v1(52.79,2554.96) 52.45,2554.62 52.45,1678.93 147.83,1583.56 v1(613.43,1583.56)
PB22: J17.1 MSP1.21 | length 496
  Top Layer w8: MSP1.21@634.5,1533.38 635.32,1532.57 635.32,1498.94 642.28,1491.98 734.59,1491.98 759.07,1516.46 759.07,1519.83 756.61,1755.52 J17.1@696.25,1815.89
PB23_TIMA0-FAL: MSP1.22
PB24_ADC0.5_COMP1-IN1+: MSP1.23
PB25_ADC0.4_TIMA2-FAL: MSP1.27
PB26: J18.1 MSP1.28 | length 199.6
  Top Layer w8: J18.1@467.18,1720.72 467.18,1658.6 496.71,1629.07 MSP1.28@496.71,1533.38
PB27: J20.1 MSP1.29 | length 247.3
  Top Layer w8: J20.1@339.57,1723.71 475.84,1587.43 475.84,1534.56 MSP1.29@477.02,1533.38
PGND: C167.2 C168.2 C169.2 C170.2 C171.2 C173.2 C174.1 C175.1 C176.1 C177.1 C178.2 C179.2 C180.2 C181.2 C183.2 C184.2 C185.2 C186.2 C196.2 C197.2 C198.2 C199.2 C201.1 C205.2 C206.1 C207.2 C213.2 C214.1 C215.2 C216.2 CO1.2 D13.1 J5.1 J11.3 J11.5 J11.7 J11.9 LED2.1 LED2.2 LED2.3 MSP1.41 Q6.2 R88.1 R219.1 R223.1 R229.2 R236.1 R244.1 S1.1 S1.2 S2.1 S2.2 S2.3 U5.2 U6.3 U6.4 U6.7@91.18,2283.19 U7.3 U7.4 U7.5 U7.6 U8.4 U9.4 U9.5 U9.6 U9.7 U9.8 U11.9 U11.15 U14.4 Y2.2 Y2.4 | length 4029.6
  Top Layer w8: C177.1@64.52,1258.74 64.52,1313.59 C174.1@59.52,1318.58 63.46,1318.58 71.27,1326.4 71.27,1327.44 101.08,1357.25 108.01,1357.25 135.3,1384.53 R229.2@135.3,1385.02 137.28,1387.01 137.28,1402.05 ; C176.1@82.99,1088.56 82.99,1084.63 90.8,1076.82 94.74,1076.82 95.87,1075.69 124.74,1075.69 Y2.4@136.77,1063.66 155.41,1082.3 155.41,1101 Y2.2@199.76,1145.35 ; C167.2@112.12,1454.71 C167.2@113.1,1454.71 ; C168.2@130.67,1513.33 130.67,1472.27 C167.2@113.1,1454.71 ; Y2.2@199.76,1150.28 203.38,1146.66 248.09,1146.66 255.91,1154.47 C175.1@255.91,1155.51 ; MSP1.41@351.04,1299.13 305.47,1299.13 197.86,1406.74 141.97,1406.74 137.28,1402.05 ; C173.2@568.65,1699.45 572.59,1703.38 R223.1@643.36,1703.38 ; C186.2@807.09,1574.17 807.09,1500.01 836.61,1470.48 836.61,1422.01 841.3,1417.32 C213.2@885.63,1417.32 ; C213.2@888.41,1414.77 891.13,1417.49 891.13,1440.95 C214.1@964.57,1440.94 966.78,1443.16 985.57,1443.16 990.41,1447.99 1041.5,1447.99 U9.4@1043.31,1449.8 ; C213.2@901.03,1399.93 C213.2@906.54,1405.43 ; U14.4@931.01,1772.82 929.11,1774.72 923.2,1774.72 913.45,1784.47 913.45,1844.53 959.77,1890.85 959.77,1901.87 961.76,1903.85 961.76,1925.08 C185.2@982.76,1946.08 982.69,1946.01 982.69,1943.87 1003.69,1922.87 1033.99,1922.87 1038.86,1927.74 ; 974.41,1432.22 984.23,1422.4 1041.5,1422.4 U9.5@1043.31,1424.21 U9.7@1043.31,1373.03 ; 988.82,1436.91 990.86,1434.86 ; U11.9@1002.85,1264.08 1002.85,1240.99 1006.08,1237.76 1039.07,1237.76 1047.2,1229.63 1047.2,987.76 1023.52,964.08 U11.15@1002.85,964.08 ; J11.9@1038.86,1831.81 1038.86,1927.74 ; 1085.87,2027.87 1085.87,1963.43 1074.55,1963.43 1073.83,1962.71 1073.83,1951.39 1073.1,1950.67 1061.79,1950.67 1038.86,1927.74 ; C201.1@1087.8,1948.73 C201.1@1088.79,1948.73 ; C205.2@1107.02,2102.33 C205.2@1127.44,2081.91 ; 1205.98,2049.94 1376.66,2049.94 1410.2,2016.4 U8.4@1410.2,1992.78 ; C167.2@113.1,1454.71 127.8,1440.01 127.8,1439.02 137.28,1429.54 137.28,1402.05 ; C216.2@933.76,894.53 933.76,893.55 919.06,878.85 918.08,878.85 C216.2@933.76,894.53 ; C216.2@933.76,894.53 939.4,900.17 939.4,956.84 C215.2@937.69,958.55 940.45,961.32 999.87,961.32 U11.15@999.98,961.21 ; U11.15@999.98,961.21 U11.15@1002.85,964.08 ; U11.15@999.98,961.21 U11.15@1002.85,964.08 ; U11.15@999.98,961.21 U11.15@1002.85,964.08 ; U11.15@999.98,961.21 U11.15@1002.85,964.08
  Top Layer w20: C177.1@59.52,1258.51 57.71,1256.7 53.77,1256.7 53.77,1247.99 50,1244.22 50,1106.03 61.72,1094.31 81.18,1094.31 82.99,1092.5 C176.1@82.99,1084.63 ; v1(62.49,1461.71) 62.88,1461.32 105.5,1461.32 C167.2@112.12,1454.71 ; C198.2@104.46,2127.03 C198.2@104.46,2128.02 ; S1.2@339.57,2751.97 343.61,2751.97 S1.2@353.29,2761.65 ; C181.2@379.29,2949.24 C180.2@379.29,3034.96 ; C180.2@390.94,3023.31 C180.2@379.29,3034.96 ; C199.2@492.13,2527.01 492.29,2527.01 494.1,2528.82 R244.1@494.1,2576.52 ; D13.1@533.47,3230.1 488.47,3185.1 408.89,3185.1 379.29,3155.5 C179.2@379.29,3145.66 C180.2@379.29,3044.8 C180.2@379.29,3034.96 ; C183.2@597.29,2260.61 682.54,2260.61 749.24,2327.31 C184.2@749.24,2351.14 ; U5.2@657.92,2440.38 U5.2@657.24,2439.69 700.07,2439.69 R219.1@707.52,2432.24 ; R219.1@711.87,2436.59 711.87,2432.91 R219.1@713.68,2431.1 ; U11.9@1002.85,1264.08 1004.66,1265.89 1011.12,1265.89 v1(1011.12,1297.72) ; J11.9@1038.86,1831.81 J11.7@1088.86,1831.81 J11.5@1138.86,1831.81 J11.3@1188.86,1831.81 ; U7.3@1080.72,2219.34 U7.4@1106.31,2219.34 U7.5@1131.9,2219.34 ; U7.5@1132.55,2216.98 1155.99,2216.98 1155.99,2217.85 U7.6@1157.49,2219.34
  other v1: 958.52,1297.72 985.26,1297.72 958.97,1320.72 985.71,1320.72 1011.57,1320.72 1181.11,2159.75 1207.01,2159.75 1181.11,2185.61 1207.01,2185.61 1181.11,2212.35 1207.01,2212.35 312.27,2563.67 355.54,2792.19
  other v4: 91.18,2261.54 91.18,2304.84
R\S\T\: C171.1 J11.10 MSP1.38 R214.1 S2.4 U14.2 | length 1686.3
  Top Layer w8: S2.4@225.34,1995.66 S2.4@226.83,1994.17 ; C171.1@231.49,1913.14 231.49,1776.51 242.4,1765.6 v1(242.4,1761.81) 242.4,1412.93 295.23,1360.09 349.13,1360.09 MSP1.38@351.04,1358.19 ; v1(953.81,1826.69) 953.81,1822.9 956.6,1820.11 U14.2@956.6,1799.39
  Top Layer w20: R214.1@173.35,1913.14 C171.1@229.4,1913.14 ; S2.4@227.59,1979.07 227.59,1914.95 C171.1@229.4,1913.14 ; C171.1@231.49,1913.14 C171.1@229.4,1913.14
  Signal Layer 1 w8: v1(242.4,1761.81) 888.93,1761.81 v1(953.81,1826.69)
  Bottom Layer w8: v1(953.81,1826.69) 1039.52,1740.99 v1(1039.52,1705.6)
REF_CAP_A1: C64_A1.2 U1_A1.54 | length 130.9
  Top Layer w7: U1_A1.54@3433.88,1257.74 3470.79,1257.74 3471.31,1258.27 3498.29,1258.27 3513.61,1242.94 3515.31,1244.64 3535.98,1244.64 C64_A1.2@3551.18,1259.84
REF_CAP_A2: C64_A2.2 U1_A2.54 | length 130.9
  Top Layer w7: U1_A2.54@5728.89,1257.74 5765.81,1257.74 5766.33,1258.27 5793.3,1258.27 5808.63,1242.94 5810.33,1244.64 5831,1244.64 C64_A2.2@5846.2,1259.84
REF_CAP_A3: C64_A3.2 U1_A3.54 | length 130.9
  Top Layer w7: U1_A3.54@8065.49,1260.95 8102.4,1260.95 8102.93,1261.48 8129.9,1261.48 8145.22,1246.15 8146.92,1247.85 8167.59,1247.85 C64_A3.2@8182.79,1263.05
REF_CAP_A4: C64_A4.2 U1_A4.54 | length 130.9
  Top Layer w7: U1_A4.54@10385.72,1257.74 10422.63,1257.74 10423.16,1258.27 10450.13,1258.27 10465.45,1242.94 10467.15,1244.64 10487.82,1244.64 C64_A4.2@10503.02,1259.84
RX/GPIO0_A1: R208.1 R257_A1.1 U1_A1.51 | length 3343.9
  Top Layer w7: U1_A1.51@3433.88,1198.69 3435.31,1197.25 3473.9,1197.25 3480.02,1191.13 v1(3484.09,1191.13)
  Signal Layer 2 w7: v1(2260.93,1427.8) 2269.87,1436.74 2269.87,1463.54 2361.83,1555.5 2361.83,1558.46 2431.45,1628.08 2431.45,1915.72 2435.55,1919.82 3620.72,1919.82 3707.74,1832.8 3707.74,1395.18 3527.64,1215.08 3527.64,1208.01 3514.53,1194.9 3509.09,1194.9 3505.59,1191.4 3484.36,1191.4 v1(3484.09,1191.13)
  Bottom Layer w7: R208.1@2051.18,1053.15 2055.12,1053.15 2081.58,1079.61 2081.58,1248.45 2260.3,1427.17 v1@2263.78,1427.17 ; v1(3484.09,1191.13) 3487.28,1191.13 3547.42,1130.99 R257_A1.1@3660.84,1130.99
RX/GPIO0_A2: R257_A2.1 U1_A2.51 | length 2881.8
  Top Layer w7: U1_A2.51@5728.89,1198.69 5730.33,1197.25 5768.92,1197.25 5775.04,1191.13 v1(5779.1,1191.13)
  Signal Layer 2 w7: v1(4547.23,1427.16) v1(4547.23,1427.16) 4564.88,1444.87 4564.88,1463.54 4656.84,1555.5 4656.84,1558.46 4726.47,1628.08 4726.47,1915.72 4730.57,1919.82 5915.73,1919.82 6002.75,1832.8 6002.75,1395.18 5822.65,1215.08 5822.65,1208.01 5809.54,1194.9 5804.11,1194.9 5800.61,1191.4 5779.37,1191.4 v1(5779.1,1191.13)
  Bottom Layer w7: v1(5779.1,1191.13) 5782.3,1191.13 5842.44,1130.99 R257_A2.1@5955.86,1130.99
RX/GPIO0_A3: R257_A3.1 U1_A3.51 | length 2877.5
  Top Layer w7: U1_A3.51@8065.49,1201.9 8066.92,1200.46 8105.52,1200.46 8111.64,1194.34 v1(8115.7,1194.34)
  Signal Layer 2 w7: v1(6892.54,1431.01) 6901.48,1439.95 6901.48,1466.75 6993.44,1558.71 6993.44,1561.67 7063.07,1631.29 7063.07,1918.92 7067.17,1923.02 8252.33,1923.02 8339.35,1836.01 8339.35,1398.38 8159.25,1218.28 8159.25,1211.22 8146.14,1198.11 8140.7,1198.11 8137.2,1194.61 8115.97,1194.61 v1(8115.7,1194.34)
  Bottom Layer w7: v1(8115.7,1194.34) 8118.89,1194.34 8179.04,1134.2 R257_A3.1@8292.46,1134.2
RX/GPIO0_A4: R257_A4.1 U1_A4.51 | length 2877.5
  Top Layer w7: U1_A4.51@10385.72,1198.69 10387.15,1197.25 10425.75,1197.25 10431.87,1191.13 v1(10435.93,1191.13)
  Signal Layer 2 w7: v1(9212.77,1427.8) 9221.71,1436.74 9221.71,1463.54 9313.67,1555.5 9313.67,1558.46 9383.3,1628.08 9383.3,1915.72 9387.4,1919.82 10572.56,1919.82 10659.58,1832.8 10659.58,1395.18 10479.48,1215.08 10479.48,1208.01 10466.37,1194.9 10460.93,1194.9 10457.43,1191.4 10436.2,1191.4 v1(10435.93,1191.13)
  Bottom Layer w7: v1(10435.93,1191.13) 10439.12,1191.13 10499.27,1130.99 R257_A4.1@10612.69,1130.99
TS1_A1: C136_A1.1 J2_A1.1 U3_A1.5 | length 2459.7
  Top Layer w7: v1(2248.36,3532.1) 2273.04,3556.78 2288.89,3556.78 2310.69,3578.58 2310.69,3581.73 2324.91,3595.94 J2_A1.1@2324.91,3647.12
  Bottom Layer w7: C136_A1.1@2280.98,3593.93 2280.98,3564.72 v1(2248.36,3532.1) 2248.36,3356.07 2177.55,3285.26 2177.55,1672.32 2246.35,1603.52 2397.77,1603.52 2412.94,1588.35 2412.94,1528.73 2415.13,1526.54 U3_A1.5@2415.13,1520.2
TS1_A2: C136_A2.1 J2_A2.1 U3_A2.5 | length 2459.7
  Top Layer w7: v1(4543.38,3532.1) 4568.05,3556.78 4583.9,3556.78 4605.71,3578.58 4605.71,3581.73 4619.93,3595.94 J2_A2.1@4619.93,3647.12
  Bottom Layer w7: C136_A2.1@4575.99,3593.93 4575.99,3564.72 v1(4543.38,3532.1) 4543.38,3356.07 4472.57,3285.26 4472.57,1672.32 4541.37,1603.52 4692.79,1603.52 4707.96,1588.35 4707.96,1528.73 4710.14,1526.54 U3_A2.5@4710.14,1520.2
TS1_A3: C136_A3.1 J2_A3.1 U3_A3.5 | length 2459.7
  Top Layer w7: v1(6879.97,3535.31) 6904.65,3559.98 6920.5,3559.98 6942.31,3581.79 6942.31,3584.93 6956.52,3599.15 J2_A3.1@6956.52,3650.33
  Bottom Layer w7: C136_A3.1@6912.59,3597.14 6912.59,3567.93 v1(6879.97,3535.31) 6879.97,3359.27 6809.17,3288.47 6809.17,1675.53 6877.97,1606.73 7029.39,1606.73 7044.56,1591.56 7044.56,1531.94 7046.74,1529.75 U3_A3.5@7046.74,1523.41
TS1_A4: C136_A4.1 J2_A4.1 U3_A4.5 | length 2459.7
  Top Layer w7: v1(9200.2,3532.1) 9224.88,3556.78 9240.73,3556.78 9262.54,3578.58 9262.54,3581.73 9276.75,3595.94 J2_A4.1@9276.75,3647.12
  Bottom Layer w7: C136_A4.1@9232.82,3593.93 9232.82,3564.72 v1(9200.2,3532.1) 9200.2,3356.07 9129.4,3285.26 9129.4,1672.32 9198.2,1603.52 9349.62,1603.52 9364.79,1588.35 9364.79,1528.73 9366.97,1526.54 U3_A4.5@9366.97,1520.2
TS2_A1: C130_A1.1 J2_A1.22 U3_A1.4 | length 2609.9
  Top Layer w7: v1(2285.54,3532.1) 2324.23,3570.79 2342.27,3570.79 2350.06,3578.58 2350.06,3581.73 2364.28,3595.94 J2_A1.22@2364.28,3647.12
  Bottom Layer w7: C130_A1.1@2343.97,3702.2 2343.97,3698.26 2304.35,3658.65 2304.35,3550.91 v1(2285.54,3532.1) 2285.54,3372.21 2192.43,3279.1 2192.43,1678.48 2252.51,1618.4 2430.25,1618.4 2440.72,1607.93 U3_A1.4@2440.72,1520.2
TS2_A2: C130_A2.1 J2_A2.22 U3_A2.4 | length 2609.9
  Top Layer w7: v1(4580.56,3532.1) 4619.24,3570.79 4637.29,3570.79 4645.08,3578.58 4645.08,3581.73 4659.3,3595.94 J2_A2.22@4659.3,3647.12
  Bottom Layer w7: C130_A2.1@4638.98,3702.2 4638.98,3698.26 4599.37,3658.65 4599.37,3550.91 v1(4580.56,3532.1) 4580.56,3372.21 4487.44,3279.1 4487.44,1678.48 4547.53,1618.4 4725.27,1618.4 4735.74,1607.93 U3_A2.4@4735.74,1520.2
TS2_A3: C130_A3.1 J2_A3.22 U3_A3.4 | length 2609.9
  Top Layer w7: v1(6917.15,3535.31) 6955.84,3574 6973.88,3574 6981.68,3581.79 6981.68,3584.93 6995.89,3599.15 J2_A3.22@6995.89,3650.33
  Bottom Layer w7: C130_A3.1@6975.58,3705.41 6975.58,3701.47 6935.96,3661.85 6935.96,3554.12 v1(6917.15,3535.31) 6917.15,3375.42 6824.04,3282.31 6824.04,1681.69 6884.13,1621.61 7061.87,1621.61 7072.33,1611.14 U3_A3.4@7072.33,1523.41
TS2_A4: C130_A4.1 J2_A4.22 U3_A4.4 | length 2609.9
  Top Layer w7: v1(9237.38,3532.1) 9276.07,3570.79 9294.11,3570.79 9301.91,3578.58 9301.91,3581.73 9316.12,3595.94 J2_A4.22@9316.12,3647.12
  Bottom Layer w7: C130_A4.1@9295.81,3702.2 9295.81,3698.26 9256.19,3658.65 9256.19,3550.91 v1(9237.38,3532.1) 9237.38,3372.21 9144.27,3279.1 9144.27,1678.48 9204.36,1618.4 9382.1,1618.4 9392.56,1607.93 U3_A4.4@9392.56,1520.2
TS3_A1: C126_A1.1 J2_A1.2 U3_A1.2 | length 2551.7
  Top Layer w7: v1(2322.72,3532.1) 2346.53,3555.91 2348.43,3555.91 2363.31,3570.79 2381.64,3570.79 2389.43,3578.58 2389.43,3581.73 2403.65,3595.94 J2_A1.2@2403.65,3647.12
  Bottom Layer w7: C126_A1.1@2343.47,3593.93 2343.47,3590 2322.72,3569.24 v1(2322.72,3532.1) 2322.72,3388.35 2207.3,3272.94 2207.3,1684.64 2258.67,1633.27 2432.77,1633.27 2445.19,1645.69 2473.36,1645.69 2491.9,1627.15 U3_A1.2@2491.9,1520.2
TS3_A2: C126_A2.1 J2_A2.2 U3_A2.2 | length 2551.7
  Top Layer w7: v1(4617.73,3532.1) 4641.55,3555.91 4643.45,3555.91 4658.32,3570.79 4676.66,3570.79 4684.45,3578.58 4684.45,3581.73 4698.67,3595.94 J2_A2.2@4698.67,3647.12
  Bottom Layer w7: C126_A2.1@4638.49,3593.93 4638.49,3590 4617.73,3569.24 v1(4617.73,3532.1) 4617.73,3388.35 4502.32,3272.94 4502.32,1684.64 4553.69,1633.27 4727.79,1633.27 4740.21,1645.69 4768.37,1645.69 4786.92,1627.15 U3_A2.2@4786.92,1520.2
TS3_A3: C126_A3.1 J2_A3.2 U3_A3.2 | length 2551.7
  Top Layer w7: v1(6954.33,3535.31) 6978.15,3559.12 6980.04,3559.12 6994.92,3574 7013.25,3574 7021.05,3581.79 7021.05,3584.93 7035.26,3599.15 J2_A3.2@7035.26,3650.33
  Bottom Layer w7: C126_A3.1@6975.09,3597.14 6975.09,3593.2 6954.33,3572.45 v1(6954.33,3535.31) 6954.33,3391.56 6838.91,3276.15 6838.91,1687.85 6890.29,1636.48 7064.38,1636.48 7076.8,1648.9 7104.97,1648.9 7123.51,1630.36 U3_A3.2@7123.51,1523.41
TS3_A4: C126_A4.1 J2_A4.2 U3_A4.2 | length 2551.7
  Top Layer w7: v1(9274.56,3532.1) 9298.38,3555.91 9300.27,3555.91 9315.15,3570.79 9333.48,3570.79 9341.28,3578.58 9341.28,3581.73 9355.49,3595.94 J2_A4.2@9355.49,3647.12
  Bottom Layer w7: C126_A4.1@9295.32,3593.93 9295.32,3590 9274.56,3569.24 v1(9274.56,3532.1) 9274.56,3388.35 9159.14,3272.94 9159.14,1684.64 9210.52,1633.27 9384.61,1633.27 9397.03,1645.69 9425.2,1645.69 9443.74,1627.15 U3_A4.2@9443.74,1520.2
TS4_A1: C121_A1.1 J2_A1.23 U3_A1.1 | length 2693.7
  Top Layer w7: v1(2359.9,3532.1) 2383.71,3555.91 2387.8,3555.91 2402.68,3570.79 2421.01,3570.79 2428.8,3578.58 2428.8,3581.73 2443.02,3595.94 J2_A1.23@2443.02,3647.12
  Bottom Layer w7: C121_A1.1@2406.66,3702.2 2405.97,3701.51 2405.97,3675.66 2400.11,3669.8 2388.83,3669.8 2368.16,3649.13 2368.16,3574.97 2359.39,3566.2 2359.39,3532.61 v1(2359.9,3532.1) 2359.9,3404.5 2222.18,3266.78 2222.18,1690.81 2264.84,1648.15 2426.61,1648.15 2439.03,1660.57 2479.52,1660.57 2517.49,1622.59 U3_A1.1@2517.49,1520.2
TS4_A2: C121_A2.1 J2_A2.23 U3_A2.1 | length 2693.7
  Top Layer w7: v1(4654.91,3532.1) 4678.73,3555.91 4682.82,3555.91 4697.69,3570.79 4716.03,3570.79 4723.82,3578.58 4723.82,3581.73 4738.04,3595.94 J2_A2.23@4738.04,3647.12
  Bottom Layer w7: C121_A2.1@4701.68,3702.2 4700.98,3701.51 4700.98,3675.66 4695.13,3669.8 4683.84,3669.8 4663.17,3649.13 4663.17,3574.97 4654.4,3566.2 4654.4,3532.61 v1(4654.91,3532.1) 4654.91,3404.5 4517.19,3266.78 4517.19,1690.81 4559.85,1648.15 4721.63,1648.15 4734.05,1660.57 4774.53,1660.57 4812.51,1622.59 U3_A2.1@4812.51,1520.2
TS4_A3: C121_A3.1 J2_A3.23 U3_A3.1 | length 2693.7
  Top Layer w7: v1(6991.51,3535.31) 7015.33,3559.12 7019.41,3559.12 7034.29,3574 7052.62,3574 7060.42,3581.79 7060.42,3584.93 7074.63,3599.15 J2_A3.23@7074.63,3650.33
  Bottom Layer w7: C121_A3.1@7038.28,3705.41 7037.58,3704.71 7037.58,3678.87 7031.72,3673.01 7020.44,3673.01 6999.77,3652.34 6999.77,3578.18 6991,3569.41 6991,3535.82 v1(6991.51,3535.31) 6991.51,3407.71 6853.79,3269.98 6853.79,1694.01 6896.45,1651.35 7058.22,1651.35 7070.64,1663.77 7111.13,1663.77 7149.1,1625.8 U3_A3.1@7149.1,1523.41
TS4_A4: C121_A4.1 J2_A4.23 U3_A4.1 | length 2693.7
  Top Layer w7: v1(9311.74,3532.1) 9335.56,3555.91 9339.64,3555.91 9354.52,3570.79 9372.85,3570.79 9380.65,3578.58 9380.65,3581.73 9394.86,3595.94 J2_A4.23@9394.86,3647.12
  Bottom Layer w7: C121_A4.1@9358.51,3702.2 9357.81,3701.51 9357.81,3675.66 9351.95,3669.8 9340.67,3669.8 9320,3649.13 9320,3574.97 9311.23,3566.2 9311.23,3532.61 v1(9311.74,3532.1) 9311.74,3404.5 9174.02,3266.78 9174.02,1690.81 9216.68,1648.15 9378.45,1648.15 9390.87,1660.57 9431.36,1660.57 9469.33,1622.59 U3_A4.1@9469.33,1520.2
TS5_A1: C116_A1.1 J2_A1.3 U3_A1.15 | length 2467.7
  Top Layer w7: v1(2394.98,3531.63) 2419.27,3555.91 2427.17,3555.91 2442.05,3570.79 2460.38,3570.79 2468.17,3578.58 2468.17,3581.73 2482.39,3595.94 J2_A1.3@2482.39,3647.12
  Bottom Layer w7: C116_A1.1@2405.97,3593.93 2405.97,3590 2387.76,3571.79 2387.76,3542.91 2394.98,3535.69 v1(2394.98,3531.63) 2394.98,3418.54 2237.05,3260.62 2237.05,1696.97 2271,1663.02 2420.45,1663.02 2432.87,1675.44 2456.91,1675.44 2493.16,1711.69 2493.16,1747.28 U3_A1.15@2491.9,1748.54
TS5_A2: C116_A2.1 J2_A2.3 U3_A2.15 | length 2467.7
  Top Layer w7: v1(4689.99,3531.63) 4714.28,3555.91 4722.19,3555.91 4737.06,3570.79 4755.4,3570.79 4763.19,3578.58 4763.19,3581.73 4777.41,3595.94 J2_A2.3@4777.41,3647.12
  Bottom Layer w7: C116_A2.1@4700.98,3593.93 4700.98,3590 4682.77,3571.79 4682.77,3542.91 4689.99,3535.69 v1(4689.99,3531.63) 4689.99,3418.54 4532.07,3260.62 4532.07,1696.97 4566.01,1663.02 4715.47,1663.02 4727.89,1675.44 4751.93,1675.44 4788.18,1711.69 4788.18,1747.28 U3_A2.15@4786.92,1748.54
TS5_A3: C116_A3.1 J2_A3.3 U3_A3.15 | length 2467.7
  Top Layer w7: v1(7026.59,3534.83) 7050.88,3559.12 7058.78,3559.12 7073.66,3574 7091.99,3574 7099.79,3581.79 7099.79,3584.93 7114,3599.15 J2_A3.3@7114,3650.33
  Bottom Layer w7: C116_A3.1@7037.58,3597.14 7037.58,3593.2 7019.37,3574.99 7019.37,3546.11 7026.59,3538.9 v1(7026.59,3534.83) 7026.59,3421.75 6868.66,3263.82 6868.66,1700.17 6902.61,1666.23 7052.06,1666.23 7064.48,1678.65 7088.52,1678.65 7124.77,1714.9 7124.77,1750.49 U3_A3.15@7123.51,1751.75
TS5_A4: C116_A4.1 J2_A4.3 U3_A4.15 | length 2467.7
  Top Layer w7: v1(9346.82,3531.63) 9371.11,3555.91 9379.01,3555.91 9393.89,3570.79 9412.22,3570.79 9420.02,3578.58 9420.02,3581.73 9434.23,3595.94 J2_A4.3@9434.23,3647.12
  Bottom Layer w7: C116_A4.1@9357.81,3593.93 9357.81,3590 9339.6,3571.79 9339.6,3542.91 9346.82,3535.69 v1(9346.82,3531.63) 9346.82,3418.54 9188.89,3260.62 9188.89,1696.97 9222.84,1663.02 9372.29,1663.02 9384.71,1675.44 9408.75,1675.44 9445,1711.69 9445,1747.28 U3_A4.15@9443.74,1748.54
TS6_A1: C111_A1.1 J2_A1.24 U3_A1.14 | length 2538.8
  Top Layer w7: v1(2430.06,3532) 2453.97,3555.91 2466.54,3555.91 2467.54,3556.91 2485.87,3556.91 2507.54,3578.58 2507.54,3581.73 2521.76,3595.94 J2_A1.24@2521.76,3647.12
  Bottom Layer w7: v1(2430.06,3532) 2430.06,3432.59 2251.92,3254.45 2251.92,1703.13 2277.16,1677.89 2414.29,1677.89 2426.71,1690.31 2439.7,1690.31 2460.95,1711.57 2460.95,1743.19 U3_A1.14@2466.31,1748.54 ; v1@2431.1,3533.46 2431.52,3533.46 2450.26,3552.21 2450.26,3656.78 2464.3,3670.81 2470.03,3670.81 2479.2,3679.99 C111_A1.1@2479.2,3702.2
TS6_A2: C111_A2.1 J2_A2.24 U3_A2.14 | length 2538.8
  Top Layer w7: v1(4725.07,3532) 4748.99,3555.91 4761.56,3555.91 4762.55,3556.91 4780.89,3556.91 4802.56,3578.58 4802.56,3581.73 4816.78,3595.94 J2_A2.24@4816.78,3647.12
  Bottom Layer w7: v1(4725.07,3532) 4725.07,3432.59 4546.94,3254.45 4546.94,1703.13 4572.17,1677.89 4709.3,1677.89 4721.72,1690.31 4734.71,1690.31 4755.97,1711.57 4755.97,1743.19 U3_A2.14@4761.33,1748.54 ; v1@4726.12,3533.46 4726.54,3533.46 4745.28,3552.21 4745.28,3656.78 4759.31,3670.81 4765.04,3670.81 4774.22,3679.99 C111_A2.1@4774.22,3702.2
TS6_A3: C111_A3.1 J2_A3.24 U3_A3.14 | length 2538.8
  Top Layer w7: v1(7061.67,3535.21) 7085.58,3559.12 7098.15,3559.12 7099.15,3560.12 7117.48,3560.12 7139.16,3581.79 7139.16,3584.93 7153.37,3599.15 J2_A3.24@7153.37,3650.33
  Bottom Layer w7: v1(7061.67,3535.21) 7061.67,3435.8 6883.54,3257.66 6883.54,1706.34 6908.77,1681.1 7045.9,1681.1 7058.32,1693.52 7071.31,1693.52 7092.56,1714.78 7092.56,1746.39 U3_A3.14@7097.92,1751.75 ; v1@7062.72,3536.67 7063.13,3536.67 7081.88,3555.41 7081.88,3659.99 7095.91,3674.02 7101.64,3674.02 7110.82,3683.2 C111_A3.1@7110.82,3705.41
TS6_A4: C111_A4.1 J2_A4.24 U3_A4.14 | length 2538.8
  Top Layer w7: v1(9381.9,3532) 9405.81,3555.91 9418.38,3555.91 9419.38,3556.91 9437.71,3556.91 9459.39,3578.58 9459.39,3581.73 9473.6,3595.94 J2_A4.24@9473.6,3647.12
  Bottom Layer w7: v1(9381.9,3532) 9381.9,3432.59 9203.77,3254.45 9203.77,1703.13 9229,1677.89 9366.13,1677.89 9378.55,1690.31 9391.54,1690.31 9412.79,1711.57 9412.79,1743.19 U3_A4.14@9418.15,1748.54 ; v1@9382.94,3533.46 9383.36,3533.46 9402.11,3552.21 9402.11,3656.78 9416.14,3670.81 9421.87,3670.81 9431.05,3679.99 C111_A4.1@9431.05,3702.2
TS7_A1: C108_A1.1 J2_A1.4 U3_A1.13 | length 2378.7
  Top Layer w7: v1(2465.14,3532.1) 2500.43,3532.1 2546.91,3578.58 2546.91,3581.73 2561.13,3595.94 J2_A1.4@2561.13,3647.12
  Bottom Layer w7: U3_A1.13@2440.72,1748.54 2440.94,1748.32 2440.94,1712.6 2433.53,1705.19 2420.55,1705.19 2408.13,1692.77 2283.32,1692.77 2270.9,1705.19 2266.8,1709.29 2266.8,3248.29 2465.14,3446.63 v1(2465.14,3532.1) 2465.14,3590.61 2474.98,3590.61 C108_A1.1@2478.31,3593.93
TS7_A2: C108_A2.1 J2_A2.4 U3_A2.13 | length 2378.7
  Top Layer w7: v1(4760.15,3532.1) 4795.45,3532.1 4841.93,3578.58 4841.93,3581.73 4856.15,3595.94 J2_A2.4@4856.15,3647.12
  Bottom Layer w7: U3_A2.13@4735.74,1748.54 4735.96,1748.32 4735.96,1712.6 4728.55,1705.19 4715.56,1705.19 4703.14,1692.77 4578.33,1692.77 4565.91,1705.19 4561.81,1709.29 4561.81,3248.29 4760.15,3446.63 v1(4760.15,3532.1) 4760.15,3590.61 4770,3590.61 C108_A2.1@4773.32,3593.93
TS7_A3: C108_A3.1 J2_A3.4 U3_A3.13 | length 2378.7
  Top Layer w7: v1(7096.75,3535.31) 7132.04,3535.31 7178.53,3581.79 7178.53,3584.93 7192.74,3599.15 J2_A3.4@7192.74,3650.33
  Bottom Layer w7: U3_A3.13@7072.33,1751.75 7072.56,1751.53 7072.56,1715.8 7065.15,1708.4 7052.16,1708.4 7039.74,1695.98 6914.93,1695.98 6902.51,1708.4 6898.41,1712.5 6898.41,3251.5 7096.75,3449.84 v1(7096.75,3535.31) 7096.75,3593.81 7106.59,3593.81 C108_A3.1@7109.92,3597.14
TS7_A4: C108_A4.1 J2_A4.4 U3_A4.13 | length 2378.7
  Top Layer w7: v1(9416.98,3532.1) 9452.27,3532.1 9498.76,3578.58 9498.76,3581.73 9512.97,3595.94 J2_A4.4@9512.97,3647.12
  Bottom Layer w7: U3_A4.13@9392.56,1748.54 9392.79,1748.32 9392.79,1712.6 9385.38,1705.19 9372.39,1705.19 9359.97,1692.77 9235.16,1692.77 9222.74,1705.19 9218.64,1709.29 9218.64,3248.29 9416.98,3446.63 v1(9416.98,3532.1) 9416.98,3590.61 9426.82,3590.61 C108_A4.1@9430.15,3593.93
TS8_A1: C137_A1.1 J2_A1.5 U2_A1.5 | length 2821.7
  Top Layer w7: U2_A1.5@2466.31,1524.15 2466.31,1485.66 2461.38,1480.73 2460.69,1480.73 2417.07,1437.12 2415.4,1437.12 2412.84,1434.56 2366.76,1434.56 2349.04,1452.29 2340.41,1452.29 2313.97,1478.73 2313.97,1511.89 2192.43,1633.43 2192.43,3288.63 2364.98,3461.18 2585.59,3461.18 2616.21,3491.8 2616.21,3493.57 2658.67,3536.03 2658.67,3555.92 v1(2660.28,3557.53) 2660.28,3561.6 2650.15,3571.72 2650.15,3636.84 J2_A1.5@2639.87,3647.12
  Bottom Layer w7: C137_A1.1@2659.32,3598.72 2660.28,3597.76 v1@2660.28,3557.88
TS8_A2: C137_A2.1 J2_A2.5 U2_A2.5 | length 2834.1
  Top Layer w7: U2_A2.5@4763.91,1527.5 4761.33,1524.91 4761.33,1485.66 4756.4,1480.73 4755.7,1480.73 4733,1458.03 4733,1451.98 4710.3,1429.28 4679.44,1429.28 4670.99,1437.74 4649.97,1437.74 4608.98,1478.73 4608.98,1511.89 4487.44,1633.43 4487.44,3288.63 4659.99,3461.18 4880.61,3461.18 4911.23,3491.8 4911.23,3493.57 4953.68,3536.03 4953.68,3555.92 v1(4955.3,3557.53) 4955.3,3561.6 4945.17,3571.72 4945.17,3636.84 J2_A2.5@4934.89,3647.12
  Bottom Layer w7: C137_A2.1@4954.34,3598.72 4955.3,3597.76 v1@4955.3,3557.88
TS8_A3: C137_A3.1 J2_A3.5 U2_A3.5 | length 2837
  Top Layer w7: U2_A3.5@7101.36,1531 7097.92,1527.57 7097.92,1488.87 7093,1483.94 7092.3,1483.94 7067.64,1459.28 7067.64,1453.94 7042.98,1429.28 7012.11,1429.28 7000.45,1440.94 6986.57,1440.94 6945.58,1481.93 6945.58,1515.1 6824.04,1636.64 6824.04,3291.84 6996.59,3464.39 7217.21,3464.39 7247.82,3495.01 7247.82,3496.78 7290.28,3539.24 7290.28,3559.13 v1(7291.89,3560.74) 7291.89,3564.8 7281.76,3574.93 7281.76,3640.05 J2_A3.5@7271.48,3650.33
  Bottom Layer w7: C137_A3.1@7290.94,3601.93 7291.89,3600.97 v1@7291.89,3561.09
TS8_A4: C137_A4.1 J2_A4.5 U2_A4.5 | length 2831.1
  Top Layer w7: U2_A4.5@9422.5,1524.55 9418.15,1520.2 9418.15,1485.66 9413.23,1480.73 9412.53,1480.73 9389.17,1457.37 9389.17,1452.64 9365.81,1429.28 9334.94,1429.28 9326.49,1437.74 9306.8,1437.74 9265.81,1478.73 9265.81,1511.89 9144.27,1633.43 9144.27,3288.63 9316.82,3461.18 9537.44,3461.18 9568.05,3491.8 9568.05,3493.57 9610.51,3536.03 9610.51,3555.92 v1(9612.12,3557.53) 9612.12,3561.6 9601.99,3571.72 9601.99,3636.84 J2_A4.5@9591.71,3647.12
  Bottom Layer w7: C137_A4.1@9611.17,3598.72 9612.12,3597.76 v1@9612.12,3557.88
TS9_A1: C131_A1.1 J2_A1.26 U2_A1.4 | length 2912.3
  Top Layer w7: U2_A1.4@2440.72,1524.15 2440.72,1481.8 2410.91,1451.99 2409.24,1451.99 2406.68,1449.44 2372.92,1449.44 2355.2,1467.16 2346.57,1467.16 2328.84,1484.89 2328.84,1518.05 2207.3,1639.59 2207.3,3282.47 2369.17,3444.34 2592.57,3444.34 2633.05,3484.82 2633.05,3486.6 2682.66,3536.2 2682.66,3540.77 2695.36,3553.47 v1(2695.36,3557.53) 2679.24,3573.65 J2_A1.26@2679.24,3647.12
  Bottom Layer w7: v1(2695.36,3557.53) 2695.36,3557.88 2695.36,3602.26 2684.01,3613.61 2684.01,3653.92 2704.68,3674.59 2717.26,3674.59 2723.12,3680.44 C131_A1.1@2723.12,3706.99
TS9_A2: C131_A2.1 J2_A2.26 U2_A2.4 | length 2924.7
  Top Layer w7: U2_A2.4@4738.32,1527.5 4735.74,1524.91 4735.74,1481.8 4718.13,1464.2 4718.13,1458.14 4704.14,1444.15 4685.6,1444.15 4677.15,1452.61 4656.14,1452.61 4623.86,1484.89 4623.86,1518.05 4502.32,1639.59 4502.32,3282.47 4664.19,3444.34 4887.59,3444.34 4928.07,3484.82 4928.07,3486.6 4977.67,3536.2 4977.67,3540.77 4990.37,3553.47 v1(4990.37,3557.53) 4974.26,3573.65 J2_A2.26@4974.26,3647.12
  Bottom Layer w7: v1(4990.37,3557.53) 4990.37,3557.88 4990.37,3602.26 4979.02,3613.61 4979.02,3653.92 4999.69,3674.59 5012.28,3674.59 5018.14,3680.44 C131_A2.1@5018.14,3706.99
TS9_A3: C131_A3.1 J2_A3.26 U2_A3.4 | length 2927.5
  Top Layer w7: U2_A3.4@7075.77,1531 7072.33,1527.57 7072.33,1485.01 7052.76,1465.44 7052.76,1460.1 7036.81,1444.15 7018.28,1444.15 7006.61,1455.82 6992.73,1455.82 6960.45,1488.1 6960.45,1521.26 6838.91,1642.8 6838.91,3285.68 7000.78,3447.55 7224.18,3447.55 7264.67,3488.03 7264.67,3489.81 7314.27,3539.41 7314.27,3543.98 7326.97,3556.68 v1(7326.97,3560.74) 7310.85,3576.86 J2_A3.26@7310.85,3650.33
  Bottom Layer w7: v1(7326.97,3560.74) 7326.97,3561.09 7326.97,3605.46 7315.62,3616.81 7315.62,3657.13 7336.29,3677.79 7348.87,3677.79 7354.73,3683.65 C131_A3.1@7354.73,3710.2
TS9_A4: C131_A4.1 J2_A4.26 U2_A4.4 | length 2921
  Top Layer w7: U2_A4.4@9399.61,1525.59 9395.28,1521.27 9395.28,1484.52 9374.29,1463.53 9374.29,1458.8 9359.64,1444.15 9341.11,1444.15 9320.54,1464.72 9305.6,1464.72 9285.03,1485.29 9285.03,1513.71 9159.14,1639.59 9159.14,3282.47 9321.01,3444.34 9544.41,3444.34 9584.9,3484.82 9584.9,3486.6 9634.5,3536.2 9634.5,3540.77 9647.2,3553.47 v1(9647.2,3557.53) 9631.08,3573.65 J2_A4.26@9631.08,3647.12
  Bottom Layer w7: v1(9647.2,3557.53) 9647.2,3602.26 9635.85,3613.61 9635.85,3653.92 9656.52,3674.59 9669.1,3674.59 9674.96,3680.44 C131_A4.1@9674.96,3706.99
TS10_A1: C127_A1.1 J2_A1.6 U2_A1.2 | length 2678.8
  Top Layer w7: U2_A1.2@2389.54,1524.15 2384.18,1518.79 2384.18,1491.05 2376.38,1483.24 2351.52,1483.24 2343.72,1491.05 2343.72,1524.06 2343.72,1524.21 2222.18,1645.75 2222.18,3276.31 2373.36,3427.5 2599.55,3427.5 2729.58,3557.53 v1(2730.44,3557.53) 2730.44,3559.83 2718.61,3571.66 J2_A1.6@2718.61,3647.12
  Bottom Layer w7: C127_A1.1@2721.82,3598.72 2720.21,3597.11 2720.21,3572.18 v1@2730.44,3561.94
TS10_A2: C127_A2.1 J2_A2.6 U2_A2.2 | length 2676.5
  Top Layer w7: U2_A2.2@4687.14,1527.5 4681.78,1522.14 4681.78,1494.4 4673.98,1486.6 4649.12,1486.6 4638.73,1496.99 4638.73,1524.06 4638.73,1524.21 4517.19,1645.75 4517.19,3276.31 4668.38,3427.5 4894.56,3427.5 5024.6,3557.53 v1(5025.45,3557.53) 5025.45,3559.83 5013.63,3571.66 J2_A2.6@5013.63,3647.12
  Bottom Layer w7: C127_A2.1@5016.84,3598.72 5015.22,3597.11 5015.22,3572.18 v1@5025.45,3561.94
TS10_A3: C127_A3.1 J2_A3.6 U2_A3.2 | length 2676.5
  Top Layer w7: U2_A3.2@7024.58,1531 7019.23,1525.64 7019.23,1497.9 7011.42,1490.1 6986.57,1490.1 6975.33,1501.34 6975.33,1527.27 6975.33,1527.42 6853.79,1648.96 6853.79,3279.52 7004.98,3430.71 7231.16,3430.71 7361.19,3560.74 v1(7362.05,3560.74) 7362.05,3563.04 7350.22,3574.87 J2_A3.6@7350.22,3650.33
  Bottom Layer w7: C127_A3.1@7353.43,3601.93 7351.82,3600.31 7351.82,3575.38 v1@7362.05,3565.15
TS10_A4: C127_A4.1 J2_A4.6 U2_A4.2 | length 2680.2
  Top Layer w7: U2_A4.2@9345.73,1524.55 9340.37,1519.19 9340.37,1491.45 9332.56,1483.65 9307.71,1483.65 9299.9,1491.45 9299.9,1519.87 9174.02,1645.75 9174.02,3276.31 9325.21,3427.5 9551.39,3427.5 9681.42,3557.53 v1(9682.28,3557.53) 9682.28,3559.83 9670.45,3571.66 J2_A4.6@9670.45,3647.12
  Bottom Layer w7: C127_A4.1@9673.66,3598.72 9672.05,3597.11 9672.05,3572.18 v1@9682.28,3561.94
TS11_A1: C122_A1.1 J2_A1.27 U2_A1.1 | length 2714.5
  Top Layer w7: U2_A1.1@2363.95,1524.15 2363.95,1534.91 2358.59,1540.27 2348.69,1540.27 2237.05,1651.91 2237.05,3270.15 2377.56,3410.66 2606.52,3410.66 2666.74,3470.87 2666.74,3472.64 2714.02,3519.93 2745.81,3519.93 2757.98,3532.1 v1@2757.98,3557.53 ; J2_A1.27@2757.98,3647.12 2757.98,3569.13 2765.52,3561.6 v1(2765.52,3557.53)
  Bottom Layer w7: v1(2765.52,3557.53) 2765.52,3561.6 2761.13,3565.98 2761.13,3678.36 2785.82,3703.05 C122_A1.1@2785.82,3706.99
TS11_A2: C122_A2.1 J2_A2.27 U2_A2.1 | length 2713.7
  Top Layer w7: U2_A2.1@4661.55,1527.5 4661.55,1534.91 4656.19,1540.27 4643.71,1540.27 4532.07,1651.91 4532.07,3270.15 4672.57,3410.66 4901.54,3410.66 4961.75,3470.87 4961.75,3472.64 5009.04,3519.93 5040.83,3519.93 5053,3532.1 v1@5053,3557.53 ; J2_A2.27@5053,3647.12 5053,3569.13 5060.53,3561.6 v1(5060.53,3557.53)
  Bottom Layer w7: v1(5060.53,3557.53) 5060.53,3561.6 5056.15,3565.98 5056.15,3678.36 5080.83,3703.05 C122_A2.1@5080.83,3706.99
TS11_A3: C122_A3.1 J2_A3.27 U2_A3.1 | length 2714.3
  Top Layer w7: U2_A3.1@6998.99,1531 6998.99,1538.12 6993.64,1543.48 6980.3,1543.48 6868.66,1655.12 6868.66,3273.36 7009.17,3413.87 7238.14,3413.87 7298.35,3474.08 7298.35,3475.85 7345.64,3523.14 7377.42,3523.14 7389.59,3535.31 v1@7389.59,3560.74 ; J2_A3.27@7389.59,3650.33 7389.59,3572.34 7397.13,3564.8 v1(7397.13,3560.74)
  Bottom Layer w7: v1(7397.13,3560.74) 7397.13,3564.8 7392.74,3569.19 7392.74,3681.57 7417.43,3706.26 C122_A3.1@7417.43,3710.2
TS11_A4: C122_A4.1 J2_A4.27 U2_A4.1 | length 2718.4
  Top Layer w7: U2_A4.1@9320.14,1524.55 9320.14,1534.91 9314.78,1540.27 9300.53,1540.27 9188.89,1651.91 9188.89,3270.15 9329.4,3410.66 9558.37,3410.66 9618.58,3470.87 9618.58,3472.64 9665.87,3519.93 9697.65,3519.93 9709.82,3532.1 v1@9709.82,3557.53 ; J2_A4.27@9709.82,3647.12 9709.82,3569.13 9717.36,3561.6 v1(9717.36,3557.53)
  Bottom Layer w7: v1(9717.36,3557.53) 9717.36,3561.6 9712.97,3565.98 9712.97,3678.36 9737.66,3703.05 C122_A4.1@9737.66,3706.99
TS12_A1: C117_A1.1 J2_A1.7 U2_A1.15 | length 2419.7
  Top Layer w7: U2_A1.15@2389.54,1752.49 2389.54,1812.2 2378.82,1822.92 2378.82,1865.37 2371.82,1872.38 2329.36,1872.38 2251.92,1949.82 2251.92,3263.99 2381.75,3393.81 2613.5,3393.81 2683.58,3463.9 2683.58,3465.67 2722.14,3504.22 2780.02,3504.22 2797.35,3521.55 2797.35,3557.53 J2_A1.7@2797.35,3647.12
  Bottom Layer w7: C117_A1.1@2784.32,3598.72 2792.63,3590.41 2792.63,3569.92 2800.6,3561.94 v1@2800.6,3557.88
  other v1: 2800.6,3557.53
TS12_A2: C117_A2.1 J2_A2.7 U2_A2.15 | length 2417.4
  Top Layer w7: U2_A2.15@4687.14,1755.85 4684.55,1758.43 4684.55,1812.2 4673.84,1822.92 4673.84,1865.37 4666.83,1872.38 4624.38,1872.38 4546.94,1949.82 4546.94,3263.99 4676.76,3393.81 4908.52,3393.81 4978.6,3463.9 4978.6,3465.67 5017.15,3504.22 5075.04,3504.22 5092.37,3521.55 5092.37,3557.53 J2_A2.7@5092.37,3647.12
  Bottom Layer w7: C117_A2.1@5079.33,3598.72 5087.64,3590.41 5087.64,3569.92 5095.61,3561.94 v1@5095.61,3557.88
  other v1: 5095.61,3557.53
TS12_A3: C117_A3.1 J2_A3.7 U2_A3.15 | length 2417.4
  Top Layer w7: U2_A3.15@7024.58,1759.35 7021.15,1762.78 7021.15,1815.41 7010.43,1826.13 7010.43,1868.58 7003.43,1875.59 6960.98,1875.59 6883.54,1953.03 6883.54,3267.2 7013.36,3397.02 7245.11,3397.02 7315.19,3467.1 7315.19,3468.88 7353.75,3507.43 7411.63,3507.43 7428.96,3524.76 7428.96,3560.74 J2_A3.7@7428.96,3650.33
  Bottom Layer w7: C117_A3.1@7415.93,3601.93 7424.24,3593.62 7424.24,3573.12 7432.21,3565.15 v1@7432.21,3561.09
  other v1: 7432.21,3560.74
TS12_A4: C117_A4.1 J2_A4.7 U2_A4.15 | length 2421.1
  Top Layer w7: U2_A4.15@9345.73,1752.89 9340.37,1758.25 9340.37,1785.99 9330.66,1795.69 9330.66,1865.37 9323.66,1872.38 9281.21,1872.38 9203.77,1949.82 9203.77,3263.99 9333.59,3393.81 9565.34,3393.81 9635.42,3463.9 9635.42,3465.67 9673.98,3504.22 9731.86,3504.22 9749.19,3521.55 9749.19,3557.53 J2_A4.7@9749.19,3647.12
  Bottom Layer w7: C117_A4.1@9736.16,3598.72 9744.47,3590.41 9744.47,3569.92 9752.44,3561.94 v1@9752.44,3557.88
  other v1: 9752.44,3557.53
TS13_A1: C112_A1.1 J2_A1.28 U2_A1.14 | length 2572.1
  Top Layer w7: U2_A1.14@2415.13,1752.49 2415.13,1807.65 2394.9,1827.88 2394.9,1870.33 2377.98,1887.25 2335.52,1887.25 2266.8,1955.98 2266.8,3257.83 2385.94,3376.97 2620.89,3376.97 2721.7,3477.78 2760.96,3477.78 2772.31,3489.13 2793.75,3489.13 2836.72,3532.1 2836.72,3557.53 J2_A1.28@2836.72,3647.12
  Bottom Layer w7: v1@2835.68,3557.88 2835.68,3561.19 2822.13,3574.74 2822.13,3604.3 2811.73,3614.69 2811.73,3656.65 2829.67,3674.59 2842.65,3674.59 2848.51,3680.44 C112_A1.1@2848.51,3706.99
  other v1: 2835.68,3557.53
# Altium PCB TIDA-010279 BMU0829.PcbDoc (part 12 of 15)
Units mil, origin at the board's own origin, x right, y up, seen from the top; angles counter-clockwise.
Board outline 11269.69 x 4438.98 mil, 4 copper layers (Top Layer, Signal Layer 1, Signal Layer 2, Bottom Layer), stack 61.6 mil thick; 1437 components, 728 nets, 3667 pads, 2806 vias.

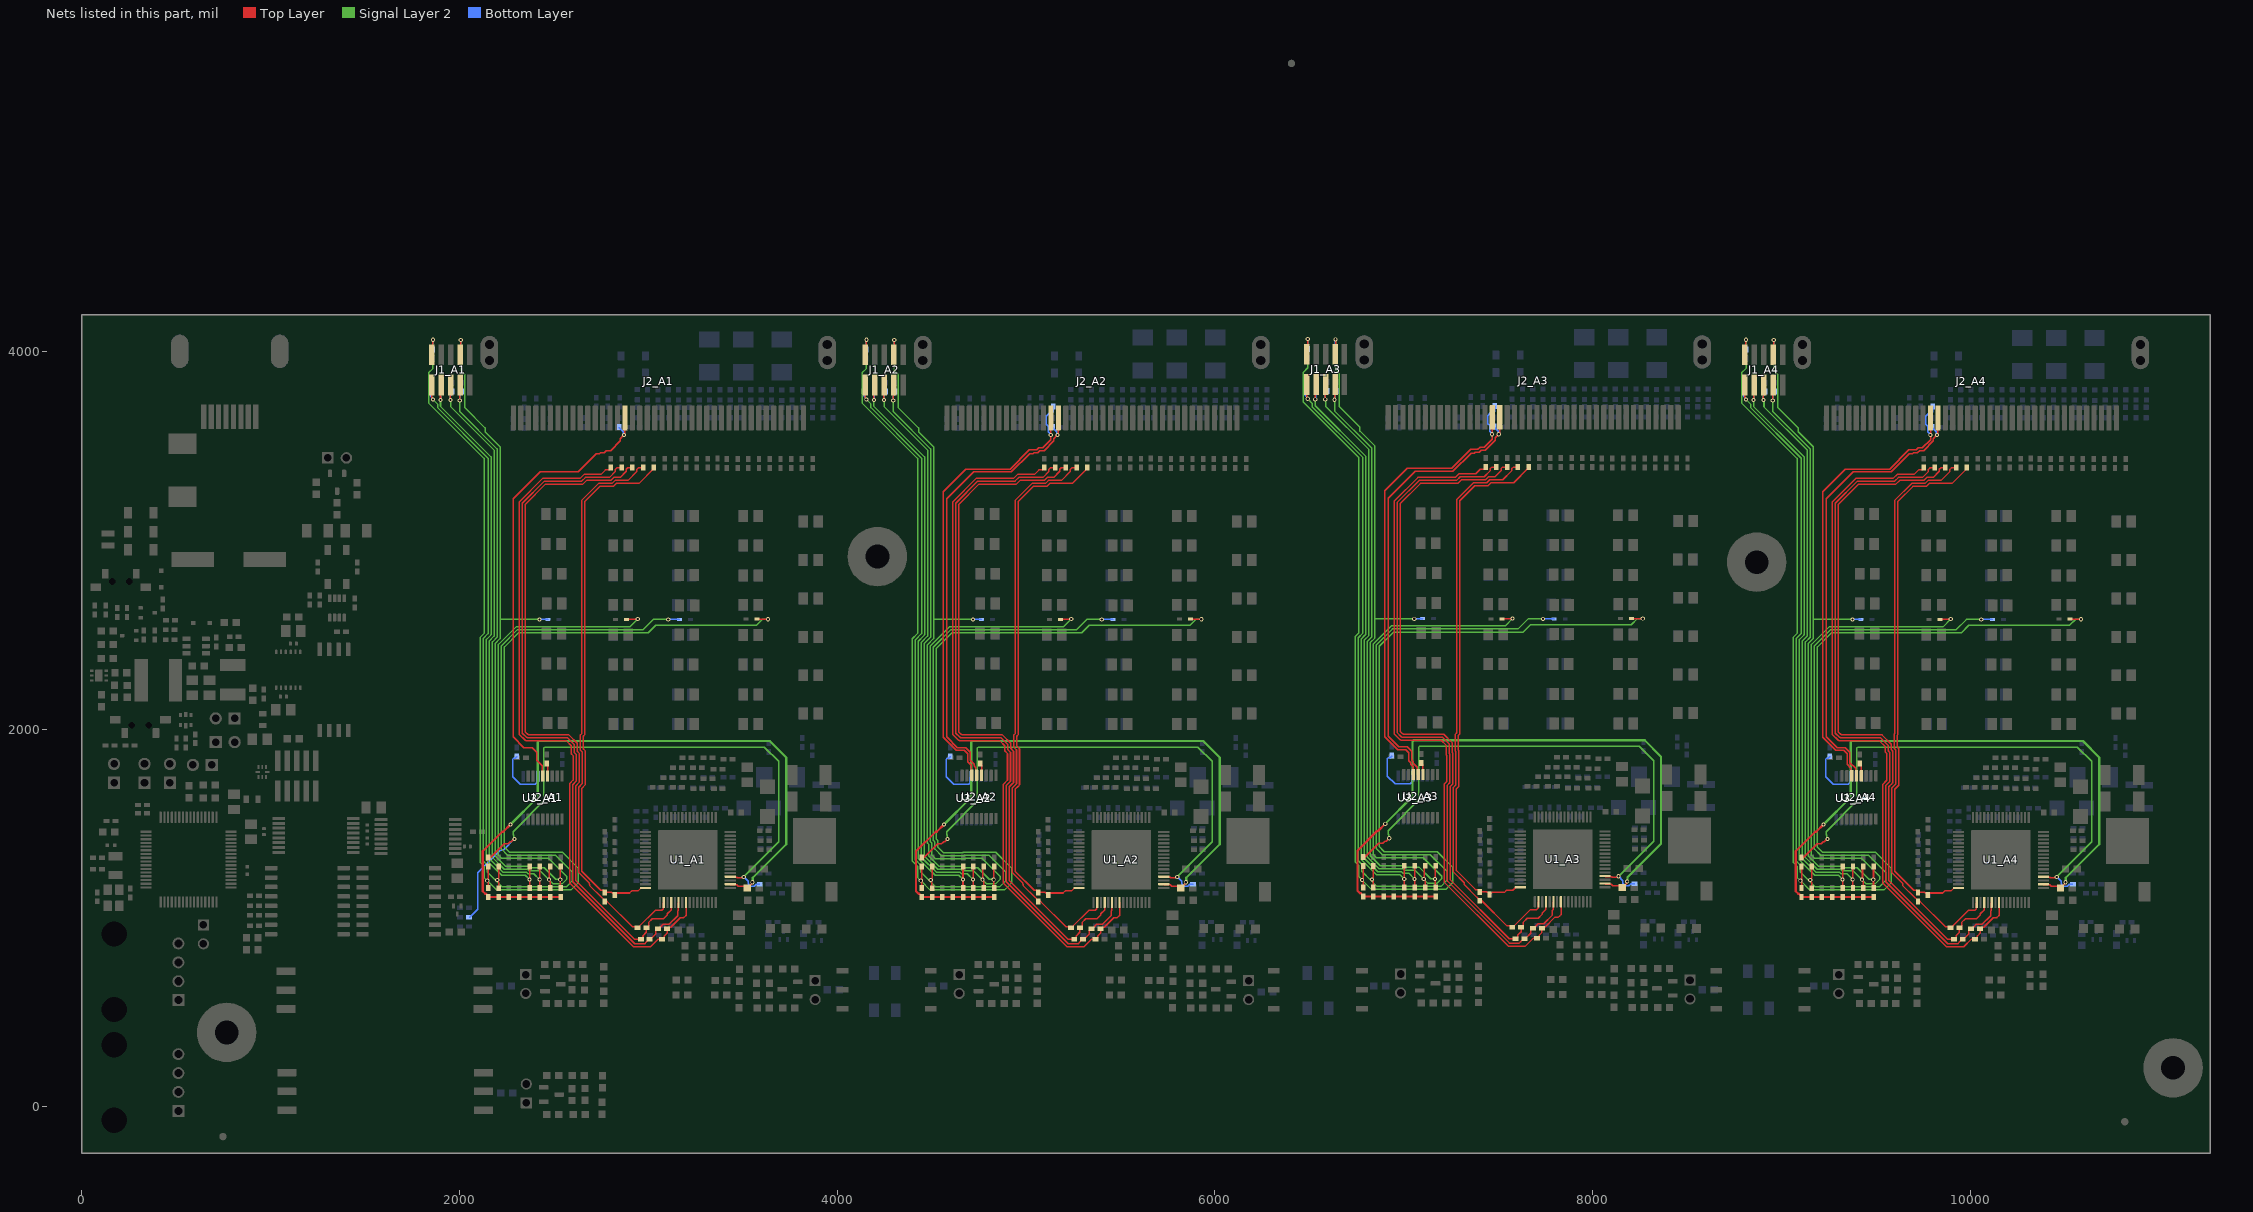
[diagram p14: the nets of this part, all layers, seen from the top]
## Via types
v1: diameter 22.01, hole 12.01, Top Layer to Bottom Layer, tented both sides, 2656 vias
v2: diameter 19.68, hole 7.87, Top Layer to Bottom Layer, tented both sides, 144 vias
v3: diameter 92.52, hole 49.21, Top Layer to Bottom Layer, 4 vias
v4: diameter 19.68, hole 7.87, Top Layer to Bottom Layer, 2 vias

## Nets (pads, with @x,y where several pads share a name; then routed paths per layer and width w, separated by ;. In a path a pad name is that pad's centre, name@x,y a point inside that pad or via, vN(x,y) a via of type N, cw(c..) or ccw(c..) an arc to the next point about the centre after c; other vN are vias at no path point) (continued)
TS13_A2: C112_A2.1 J2_A2.28 U2_A2.14 | length 2569.8
  Top Layer w7: U2_A2.14@4712.73,1755.85 4710.14,1758.43 4710.14,1807.65 4689.91,1827.88 4689.91,1870.33 4672.99,1887.25 4630.54,1887.25 4561.81,1955.98 4561.81,3257.83 4680.96,3376.97 4915.91,3376.97 5016.72,3477.78 5055.98,3477.78 5067.33,3489.13 5088.76,3489.13 5131.74,3532.1 5131.74,3557.53 J2_A2.28@5131.74,3647.12
  Bottom Layer w7: v1@5130.69,3557.88 5130.69,3561.19 5117.14,3574.74 5117.14,3604.3 5106.75,3614.69 5106.75,3656.65 5124.68,3674.59 5137.67,3674.59 5143.53,3680.44 C112_A2.1@5143.53,3706.99
  other v1: 5130.69,3557.53
TS13_A3: C112_A3.1 J2_A3.28 U2_A3.14 | length 2567.9
  Top Layer w7: U2_A3.14@7047.24,1761.81 7049.28,1763.85 7049.28,1799.38 7036.02,1812.63 7036.02,1821.57 7026.51,1831.09 7026.51,1873.54 7009.59,1890.46 6967.14,1890.46 6898.41,1959.19 6898.41,3261.04 7017.55,3380.18 7252.51,3380.18 7353.31,3480.98 7392.58,3480.98 7403.93,3492.33 7425.36,3492.33 7468.33,3535.31 J2_A3.28@7468.33,3650.33
  Bottom Layer w7: v1@7467.29,3561.09 7467.29,3564.4 7453.74,3577.95 7453.74,3607.5 7443.34,3617.9 7443.34,3659.86 7461.28,3677.79 7474.27,3677.79 7480.13,3683.65 C112_A3.1@7480.13,3710.2
  other v1: 7467.29,3560.74
TS13_A4: C112_A4.1 J2_A4.28 U2_A4.14 | length 2564
  Top Layer w7: U2_A4.14@9370.08,1761.81 9366.83,1765.06 9366.83,1792.92 9346.74,1813.01 9346.74,1870.33 9329.82,1887.25 9287.37,1887.25 9218.64,1955.98 9218.64,3257.83 9337.78,3376.97 9572.74,3376.97 9673.54,3477.78 9712.81,3477.78 9724.16,3489.13 9745.59,3489.13 9788.56,3532.1 J2_A4.28@9788.56,3647.12
  Bottom Layer w7: v1@9787.52,3557.88 9787.52,3561.19 9773.97,3574.74 9773.97,3604.3 9763.57,3614.69 9763.57,3656.65 9781.51,3674.59 9794.5,3674.59 9800.36,3680.44 C112_A4.1@9800.36,3706.99
  other v1: 9787.52,3557.53
TS14_A1: C109_A1.1 J2_A1.8 U2_A1.13 | length 2435.7
  Top Layer w7: U2_A1.13@2440.72,1752.49 2437.88,1755.33 2437.88,1805.93 2409.77,1834.04 2409.77,1878.25 2385.9,1902.13 2341.68,1902.13 2285.59,1958.22 2285.59,3220.09 2427.59,3362.1 2627.65,3362.1 2723.93,3458.38 2741.67,3458.38 2746.2,3462.9 2767.13,3462.9 2778.48,3474.25 2799.91,3474.25 2851.59,3525.94 2851.59,3538.37 v1(2870.76,3557.53) 2876.09,3557.53 J2_A1.8@2876.09,3647.12
  Bottom Layer w7: C109_A1.1@2846.81,3598.72 2846.81,3594.78 2867.89,3573.71 2867.89,3560.75 v1@2870.76,3557.88
TS14_A2: C109_A2.1 J2_A2.8 U2_A2.13 | length 2433.4
  Top Layer w7: U2_A2.13@4738.32,1755.85 4734.01,1760.16 4734.01,1795.87 4725.02,1804.87 4725.02,1814.65 4704.79,1834.88 4704.79,1878.25 4680.91,1902.13 4636.7,1902.13 4580.6,1958.22 4580.6,3220.09 4722.61,3362.1 4922.66,3362.1 5018.94,3458.38 5036.69,3458.38 5041.21,3462.9 5062.14,3462.9 5073.49,3474.25 5094.92,3474.25 5146.61,3525.94 5146.61,3538.37 v1(5165.77,3557.53) 5171.11,3557.53 J2_A2.8@5171.11,3647.12
  Bottom Layer w7: C109_A2.1@5141.83,3598.72 5141.83,3594.78 5162.9,3573.71 5162.9,3560.75 v1@5165.77,3557.88
TS14_A3: C109_A3.1 J2_A3.8 U2_A3.13 | length 2433.4
  Top Layer w7: U2_A3.13@7075.77,1759.35 7070.41,1764.71 7070.41,1799.28 7050.9,1818.79 7050.9,1827.73 7041.38,1837.25 7041.38,1881.46 7017.51,1905.34 6973.3,1905.34 6917.2,1961.43 6917.2,3223.3 7059.21,3365.31 7259.26,3365.31 7355.54,3461.59 7373.28,3461.59 7377.81,3466.11 7398.74,3466.11 7410.09,3477.46 7431.52,3477.46 7483.21,3529.15 7483.21,3541.58 v1(7502.37,3560.74) 7507.7,3560.74 J2_A3.8@7507.7,3650.33
  Bottom Layer w7: C109_A3.1@7478.42,3601.93 7478.42,3597.99 7499.5,3576.92 7499.5,3563.96 v1@7502.37,3561.09
TS14_A4: C109_A4.1 J2_A4.8 U2_A4.13 | length 2437.1
  Top Layer w7: U2_A4.13@9396.91,1752.89 9391.8,1758 9391.8,1792.92 9361.61,1823.11 9361.61,1878.25 9337.74,1902.13 9293.53,1902.13 9237.43,1958.22 9237.43,3220.09 9379.44,3362.1 9579.49,3362.1 9675.77,3458.38 9693.51,3458.38 9698.04,3462.9 9718.97,3462.9 9730.32,3474.25 9751.75,3474.25 9803.44,3525.94 9803.44,3538.37 v1(9822.6,3557.53) 9827.93,3557.53 J2_A4.8@9827.93,3647.12
  Bottom Layer w7: C109_A4.1@9798.65,3598.72 9798.65,3594.78 9819.73,3573.71 9819.73,3560.75 v1@9822.6,3557.88
TS15_A1: C138_A1.1 J1_A1.3 R162_A1.1 R165_A1.2 | length 3071.7
  Top Layer w8: v1(1899.64,3742.7) 1899.64,3816.92 J1_A1.3@1903.97,3821.25 ; R162_A1.1@2371.08,1158.67 2370.93,1158.82 2370.93,1203.52 v1(2370.77,1203.67) 2370.93,1203.83 2370.93,1273.21 R165_A1.2@2371.08,1273.36
  Signal Layer 2 w8: v1@1895.89,3742.01 1899.64,3738.26 1899.64,3708.5 2167.57,3440.57 2167.57,2499.11 2161.95,2493.48 2142.81,2474.34 2142.81,1306.61 2161.95,1287.47 2223.66,1225.76 2348.68,1225.76 v1(2370.77,1203.67)
  Bottom Layer w8: v1(1899.64,3742.7) 1901.89,3744.95 1901.89,3786.23 C138_A1.1@1904.13,3788.48
TS15_A2: C138_A2.1 J1_A2.3 R162_A2.1 R165_A2.2 | length 3083
  Top Layer w8: v1(4194.65,3742.7) 4194.65,3816.92 J1_A2.3@4198.99,3821.25 ; R162_A2.1@4666.1,1158.67 4665.94,1158.82 4665.94,1203.52 v1(4665.79,1203.67) 4665.94,1203.83 4665.94,1273.21 R165_A2.2@4666.1,1273.36
  Signal Layer 2 w8: v1(4194.65,3742.7) 4191.59,3742.7 4190.91,3742.01 4194.65,3738.26 4194.65,3708.5 4462.59,3440.57 4462.59,2499.11 4456.96,2493.48 4429.11,2465.63 4429.11,1315.32 4456.96,1287.47 4518.67,1225.76 4643.7,1225.76 v1(4665.79,1203.67)
  Bottom Layer w8: v1(4194.65,3742.7) 4196.9,3744.95 4196.9,3786.23 C138_A2.1@4199.15,3788.48
TS15_A3: C138_A3.1 J1_A3.3 R162_A3.1 R165_A3.2 | length 3071.7
  Top Layer w8: v1(6531.25,3745.9) 6531.25,3820.12 J1_A3.3@6535.58,3824.46 ; R162_A3.1@7002.69,1161.88 7002.54,1162.03 7002.54,1206.73 v1(7002.39,1206.88) 7002.54,1207.03 7002.54,1276.41 R165_A3.2@7002.69,1276.57
  Signal Layer 2 w8: v1@6527.5,3745.22 6531.25,3741.47 6531.25,3711.71 6799.19,3443.78 6799.19,2502.32 6793.56,2496.69 6774.42,2477.55 6774.42,1309.82 6793.56,1290.68 6855.27,1228.97 6980.3,1228.97 v1(7002.39,1206.88)
  Bottom Layer w8: v1(6531.25,3745.9) 6533.5,3748.15 6533.5,3789.44 C138_A3.1@6535.75,3791.69
TS15_A4: C138_A4.1 J1_A4.3 R162_A4.1 R165_A4.2 | length 3071.7
  Top Layer w8: v1(8851.48,3742.7) 8851.48,3816.92 J1_A4.3@8855.81,3821.25 ; R162_A4.1@9322.92,1158.67 9322.77,1158.82 9322.77,1203.52 v1(9322.62,1203.67) 9322.77,1203.83 9322.77,1273.21 R165_A4.2@9322.92,1273.36
  Signal Layer 2 w8: v1@8847.73,3742.01 8851.48,3738.26 8851.48,3708.5 9119.42,3440.57 9119.42,2499.11 9113.79,2493.48 9094.65,2474.34 9094.65,1306.61 9113.79,1287.47 9175.5,1225.76 9300.53,1225.76 v1(9322.62,1203.67)
  Bottom Layer w8: v1(8851.48,3742.7) 8853.73,3744.95 8853.73,3786.23 C138_A4.1@8855.98,3788.48
TS16_A1: C132_A1.1 J1_A1.5 R158_A1.1 R159_A1.2 | length 3088.1
  Top Layer w8: v1(1952.13,3742.7) 1952.13,3819.41 J1_A1.5@1953.97,3821.25 ; R158_A1.1@2426.09,1158.67 2425.25,1159.51 2425.25,1202.83 v1(2424.4,1203.67) 2425.25,1204.51 2425.25,1272.52 R159_A1.2@2426.09,1273.36
  Signal Layer 2 w8: v1@1954.94,3742.01 1954.94,3705.47 2183.45,3476.96 2183.45,2492.54 2158.68,2467.77 2158.68,1313.19 2230.23,1241.64 2355.26,1241.64 2362.67,1234.22 2393.85,1234.22 v1(2424.4,1203.67)
  Bottom Layer w8: v1(1952.13,3742.7) 1952.13,3765.7 1954.16,3767.73 1954.16,3778.68 C132_A1.1@1961.97,3786.49
TS16_A2: C132_A2.1 J1_A2.5 R158_A2.1 R159_A2.2 | length 3098.4
  Top Layer w8: v1(4247.15,3742.7) 4247.15,3819.41 J1_A2.5@4248.99,3821.25 ; R158_A2.1@4721.11,1158.67 4720.26,1159.51 4720.26,1202.83 v1(4719.42,1203.67) 4720.26,1204.51 4720.26,1272.52 R159_A2.2@4721.11,1273.36
  Signal Layer 2 w8: v1(4247.15,3742.7) 4247.83,3742.01 4249.96,3742.01 4249.96,3705.47 4478.46,3476.96 4478.46,2492.54 4444.99,2459.06 4444.99,1321.9 4525.25,1241.64 4650.27,1241.64 4657.69,1234.22 4688.87,1234.22 v1(4719.42,1203.67)
  Bottom Layer w8: v1(4247.15,3742.7) 4247.15,3765.7 4249.17,3767.73 4249.17,3778.68 C132_A2.1@4256.99,3786.49
TS16_A3: C132_A3.1 J1_A3.5 R158_A3.1 R159_A3.2 | length 3088.1
  Top Layer w8: v1(6583.74,3745.9) 6583.74,3822.62 J1_A3.5@6585.58,3824.46 ; R158_A3.1@7057.7,1161.88 7056.86,1162.72 7056.86,1206.04 v1(7056.02,1206.88) 7056.86,1207.72 7056.86,1275.73 R159_A3.2@7057.7,1276.57
  Signal Layer 2 w8: v1@6586.56,3745.22 6586.56,3708.68 6815.06,3480.17 6815.06,2495.75 6790.29,2470.98 6790.29,1316.4 6861.85,1244.84 6986.87,1244.84 6994.29,1237.43 7025.47,1237.43 v1(7056.02,1206.88)
  Bottom Layer w8: v1(6583.74,3745.9) 6583.74,3768.91 6585.77,3770.94 6585.77,3781.89 C132_A3.1@6593.58,3789.7
TS16_A4: C132_A4.1 J1_A4.5 R158_A4.1 R159_A4.2 | length 3088.1
  Top Layer w8: v1(8903.97,3742.7) 8903.97,3819.41 J1_A4.5@8905.81,3821.25 ; R158_A4.1@9377.93,1158.67 9377.09,1159.51 9377.09,1202.83 v1(9376.25,1203.67) 9377.09,1204.52 9377.09,1272.52 R159_A4.2@9377.93,1273.36
  Signal Layer 2 w8: v1@8906.79,3742.01 8906.79,3705.47 9135.29,3476.96 9135.29,2492.54 9110.52,2467.77 9110.52,1313.19 9182.08,1241.64 9307.1,1241.64 9314.52,1234.22 9345.7,1234.22 v1(9376.25,1203.67)
  Bottom Layer w8: v1(8903.97,3742.7) 8903.97,3765.7 8906,3767.73 8906,3778.68 C132_A4.1@8913.81,3786.49
TS17_A1: C128_A1.1 J1_A1.7 R156_A1.1 R157_A1.2 RT1_A1.1 | length 5620.7
  Top Layer w8: v1(2001.59,3740.12) 2001.59,3818.87 J1_A1.7@2003.97,3821.25 ; R156_A1.1@2481.1,1158.67 2481.1,1191.78 2473.78,1199.09 v1(2473.78,1202.88) 2476.46,1205.56 2476.46,1268.72 R157_A1.2@2481.1,1273.36 ; RT1_A1.1@2883.92,2580.3 2885.16,2581.55 2942.5,2581.55 v1(2943.75,2582.8)
  Signal Layer 2 w8: v1(2001.59,3740.12) 2001.59,3681.27 2199.32,3483.54 2199.32,2485.96 2174.55,2461.19 2174.55,1319.76 2236.81,1257.51 2361.83,1257.51 2369.25,1250.1 2426.57,1250.1 2496.66,1180.01 2542.78,1180.01 2568.9,1206.12 2568.9,1218.09 2470.84,1316.15 2223.07,1316.15 2206.3,1332.92 2206.3,2448.04 2301.25,2542.99 2904.77,2542.99 v1@2944.12,2582.34
  Bottom Layer w8: v1(2001.59,3740.12) 2001.59,3763.12 2004.16,3765.69 2004.16,3778.68 C128_A1.1@2011.97,3786.49
TS17_A2: C128_A2.1 J1_A2.7 R156_A2.1 R157_A2.2 RT1_A2.1 | length 5637.9
  Top Layer w8: v1(4296.6,3740.12) 4296.6,3818.87 J1_A2.7@4298.99,3821.25 ; R156_A2.1@4776.11,1158.67 4776.11,1191.78 4768.8,1199.09 v1(4768.8,1202.88) 4771.48,1205.56 4771.48,1268.72 R157_A2.2@4776.11,1273.36 ; RT1_A2.1@5178.93,2580.3 5180.18,2581.55 5237.51,2581.55 v1(5238.76,2582.8)
  Signal Layer 2 w8: v1(4296.6,3740.12) 4296.6,3681.27 4494.34,3483.54 4494.34,2485.96 4460.86,2452.48 4460.86,1328.47 4531.83,1257.51 4656.85,1257.51 4664.26,1250.1 4721.59,1250.1 v1(4768.8,1202.88) 4791.67,1180.01 4837.8,1180.01 4863.91,1206.12 4863.91,1218.09 4765.85,1316.15 4680.8,1316.15 4678.13,1313.48 4520.75,1313.48 4501.32,1332.92 4501.32,1395.83 4492.61,1404.54 4492.61,2439.33 4596.26,2542.99 5199.78,2542.99 5239.14,2582.34 5238.76,2582.72 v1(5238.76,2582.8)
  Bottom Layer w8: v1(4296.6,3740.12) 4296.6,3763.12 4299.17,3765.69 4299.17,3778.68 C128_A2.1@4306.99,3786.49
TS17_A3: C128_A3.1 J1_A3.7 R156_A3.1 R157_A3.2 RT1_A3.1 | length 5620.7
  Top Layer w8: v1(6633.2,3743.32) 6633.2,3822.08 J1_A3.7@6635.58,3824.46 ; R156_A3.1@7112.71,1161.88 7112.71,1194.98 7105.39,1202.3 v1(7105.39,1206.09) 7108.07,1208.77 7108.07,1271.93 R157_A3.2@7112.71,1276.57 ; RT1_A3.1@7515.53,2583.51 7516.77,2584.76 7574.11,2584.76 v1(7575.36,2586)
  Signal Layer 2 w8: v1(6633.2,3743.32) 6633.2,3684.48 6830.94,3486.75 6830.94,2489.17 6806.17,2464.4 6806.17,1322.97 6868.42,1260.72 6993.45,1260.72 7000.86,1253.3 7058.18,1253.3 7128.27,1183.21 7174.39,1183.21 7200.51,1209.33 7200.51,1221.3 7102.45,1319.36 6854.68,1319.36 6837.91,1336.12 6837.91,2451.25 6932.86,2546.2 7536.38,2546.2 v1@7575.73,2585.55
  Bottom Layer w8: v1(6633.2,3743.32) 6633.2,3766.33 6635.77,3768.9 6635.77,3781.89 C128_A3.1@6643.58,3789.7
TS17_A4: C128_A4.1 J1_A4.7 R156_A4.1 R157_A4.2 RT1_A4.1 | length 5620.7
  Top Layer w8: v1(8953.43,3740.12) 8953.43,3818.87 J1_A4.7@8955.81,3821.25 ; R156_A4.1@9432.94,1158.67 9432.94,1191.78 9425.62,1199.09 v1(9425.62,1202.88) 9428.3,1205.56 9428.3,1268.72 R157_A4.2@9432.94,1273.36 ; RT1_A4.1@9835.76,2580.3 9837,2581.55 9894.34,2581.55 v1(9895.59,2582.8)
  Signal Layer 2 w8: v1(8953.43,3740.12) 8953.43,3681.27 9151.17,3483.54 9151.17,2485.96 9126.4,2461.19 9126.4,1319.76 9188.65,1257.51 9313.68,1257.51 9321.09,1250.1 9378.41,1250.1 9448.5,1180.01 9494.62,1180.01 9520.74,1206.12 9520.74,1218.09 9422.68,1316.15 9174.91,1316.15 9158.14,1332.92 9158.14,2448.04 9253.09,2542.99 9856.61,2542.99 v1@9895.96,2582.34
  Bottom Layer w8: v1(8953.43,3740.12) 8953.43,3763.12 8956,3765.69 8956,3778.68 C128_A4.1@8963.81,3786.49
TS18_A1: C123_A1.1 J1_A1.8 R152_A1.1 R153_A1.2 RT2_A1.1 | length 3728.8
  Top Layer w8: J1_A1.8@2003.97,3981.48 2006.83,3984.35 v1(2006.83,4060.32) ; R152_A1.1@2536.11,1158.67 2534.71,1160.07 2534.71,1201.48 v1(2533.31,1202.88) 2534.71,1204.28 2534.71,1271.96 R153_A1.2@2536.11,1273.36
  Signal Layer 2 w8: v1(2006.83,4060.32) 2006.83,3898.37 2027.56,3877.65 2027.56,3702.89 2135.83,3594.62 2135.83,3574.7 2215.2,3495.33 2215.2,2580.43 ; v1(2423.71,2580.36) 2215.26,2580.36 2215.2,2580.43 ; v1(2533.31,1202.88) 2531.6,1204.59 2510.3,1204.59 2448.92,1265.97 2375.82,1265.97 2368.41,1273.38 2243.38,1273.38 2190.43,1326.34 2190.43,1351.79 2190.43,2454.62 2215.2,2479.39 2215.2,2580.43
  Bottom Layer w8: C123_A1.1@2005.4,4006.54 2006.12,4007.25 2006.12,4059.6 v1(2006.83,4060.32) ; v1(2423.71,2580.36) 2424.11,2580.76 2467.29,2580.76 RT2_A1.1@2467.7,2581.17
TS18_A2: C123_A2.1 J1_A2.8 R152_A2.1 R153_A2.2 RT2_A2.1 | length 3736
  Top Layer w8: J1_A2.8@4298.99,3981.48 4301.85,3984.35 v1(4301.85,4060.32) ; R152_A2.1@4831.12,1158.67 4829.72,1160.07 4829.72,1201.48 v1(4828.32,1202.88) 4829.72,1204.28 4829.72,1271.96 R153_A2.2@4831.12,1273.36
  Signal Layer 2 w8: v1(4301.85,4060.32) 4301.85,3898.37 4322.57,3877.65 4322.57,3702.89 4430.84,3594.62 4430.84,3574.7 4510.21,3495.33 4510.21,2580.43 ; v1(4718.72,2580.36) 4510.28,2580.36 4510.21,2580.43 ; v1(4828.32,1202.88) 4826.61,1204.59 4805.32,1204.59 4743.94,1265.97 4670.84,1265.97 4663.43,1273.38 4538.4,1273.38 4485.44,1326.34 4485.44,1389.25 4476.73,1397.96 4476.73,2445.91 4510.21,2479.39 4510.21,2580.43
  Bottom Layer w8: C123_A2.1@4300.42,4006.54 4301.13,4007.25 4301.13,4059.6 v1(4301.85,4060.32) ; v1(4718.72,2580.36) 4719.13,2580.76 4762.31,2580.76 RT2_A2.1@4762.71,2581.17
TS18_A3: C123_A3.1 J1_A3.8 R152_A3.1 R153_A3.2 RT2_A3.1 | length 3728.8
  Top Layer w8: J1_A3.8@6635.58,3984.69 6638.45,3987.56 v1(6638.45,4063.53) ; R152_A3.1@7167.72,1161.88 7166.32,1163.28 7166.32,1204.69 v1(7164.92,1206.09) 7166.32,1207.49 7166.32,1275.17 R153_A3.2@7167.72,1276.57
  Signal Layer 2 w8: v1(6638.45,4063.53) 6638.45,3901.58 6659.17,3880.85 6659.17,3706.09 6767.44,3597.83 6767.44,3577.91 6846.81,3498.54 6846.81,2583.64 ; v1(7055.32,2583.57) 6846.88,2583.57 6846.81,2583.64 ; v1(7164.92,1206.09) 7163.21,1207.8 7141.91,1207.8 7080.54,1269.18 7007.44,1269.18 7000.02,1276.59 6875,1276.59 6822.04,1329.55 6822.04,1355 6822.04,2457.83 6846.81,2482.59 6846.81,2583.64
  Bottom Layer w8: C123_A3.1@6637.01,4009.75 6637.73,4010.46 6637.73,4062.81 v1(6638.45,4063.53) ; v1(7055.32,2583.57) 7055.72,2583.97 7098.91,2583.97 RT2_A3.1@7099.31,2584.37
TS18_A4: C123_A4.1 J1_A4.8 R152_A4.1 R153_A4.2 RT2_A4.1 | length 3728.8
  Top Layer w8: J1_A4.8@8955.81,3981.48 8958.68,3984.35 v1(8958.68,4060.32) ; R152_A4.1@9487.95,1158.67 9486.55,1160.07 9486.55,1201.48 v1(9485.15,1202.88) 9486.55,1204.28 9486.55,1271.96 R153_A4.2@9487.95,1273.36
  Signal Layer 2 w8: v1(8958.68,4060.32) 8958.68,3898.37 8979.4,3877.65 8979.4,3702.89 9087.67,3594.62 9087.67,3574.7 9167.04,3495.33 9167.04,2580.43 ; v1@9375.55,2580.36 9167.11,2580.36 9167.04,2580.43 ; v1(9485.15,1202.88) 9483.44,1204.59 9462.14,1204.59 9400.77,1265.97 9327.67,1265.97 9320.25,1273.38 9195.23,1273.38 9142.27,1326.34 9142.27,1351.79 9142.27,2454.62 9167.04,2479.39 9167.04,2580.43
  Bottom Layer w8: C123_A4.1@8957.24,4006.54 8957.96,4007.25 8957.96,4059.6 v1(8958.68,4060.32) ; v1(9375.55,2580.36) 9375.95,2580.76 9419.14,2580.76 RT2_A4.1@9419.54,2581.17
TS19_A1: C118_A1.1 J1_A1.1 R147_A1.1 R150_A1.2 RT3_A1.1 | length 5942.1
  Top Layer w8: J1_A1.1@1853.97,3821.25 1853.97,3754.7 1859.3,3749.37 v1(1859.3,3745.58) ; v1@2197.93,1202.32 2207.17,1211.55 R150_A1.2@2207.17,1272.04 ; v1(2199.83,1200.42) 2199.83,1196.63 2206.77,1189.69 2206.77,1157.75 R147_A1.1@2207.17,1157.35 ; v1(3105.17,2580.36) v1@3105.51,2580.7
  Signal Layer 2 w8: v1(1859.3,3745.58) 1883.76,3721.11 1883.76,3701.93 2151.7,3433.99 2151.7,2505.69 2126.93,2480.92 2126.93,1300.04 2146.07,1280.9 2146.07,1244.27 v1@2194.88,1195.47 ; v1(2199.83,1200.42) v1@2194.88,1195.47 ; v1(3105.17,2580.36) 3086.57,2580.36 3086.51,2580.3 3026.4,2580.3 2973.21,2527.11 2307.82,2527.11 2222.18,2441.47 2222.18,1364.94 2255.09,1332.03 2508.57,1332.03 2598.43,1242.17 2598.43,1197.66 2564.9,1164.13 2226.21,1164.13 v1@2194.88,1195.47
  Bottom Layer w8: C118_A1.1@1845.97,3788.75 1847.67,3787.05 1847.67,3761 1859.3,3749.37 v1(1859.3,3745.58) ; v1@3105.2,2580.33 3164.19,2580.33 RT3_A1.1@3164.62,2580.76
TS19_A2: C118_A2.1 J1_A2.1 R147_A2.1 R150_A2.2 RT3_A2.1 | length 5958.7
  Top Layer w8: J1_A2.1@4148.99,3821.25 4148.99,3754.7 4154.32,3749.37 v1(4154.32,3745.58) ; v1@4492.95,1202.32 4502.19,1211.55 R150_A2.2@4502.19,1272.04 ; v1(4494.84,1200.42) 4494.84,1196.63 4501.79,1189.69 4501.79,1157.75 R147_A2.1@4502.19,1157.35 ; v1(5400.19,2580.36) v1@5400.53,2580.7
  Signal Layer 2 w8: v1(4154.32,3745.58) 4178.78,3721.11 4178.78,3701.93 4446.72,3433.99 4446.72,2505.69 4413.24,2472.21 4413.24,1308.75 4441.09,1280.9 4441.09,1244.27 v1@4489.89,1195.47 ; v1(4494.84,1200.42) v1@4489.89,1195.47 ; v1(5400.19,2580.36) 5381.58,2580.36 5381.52,2580.3 5321.41,2580.3 5268.22,2527.11 4602.84,2527.11 4508.48,2432.76 4508.48,1411.11 4517.19,1402.4 4517.19,1364.94 4552.78,1329.36 4671.55,1329.36 4674.22,1332.03 4803.59,1332.03 4893.44,1242.17 4893.44,1197.66 4859.91,1164.13 4521.23,1164.13 v1@4489.89,1195.47
  Bottom Layer w8: C118_A2.1@4140.99,3788.75 4142.69,3787.05 4142.69,3761 4154.32,3749.37 v1(4154.32,3745.58) ; v1@5400.22,2580.33 5459.2,2580.33 RT3_A2.1@5459.63,2580.76
TS19_A3: C118_A3.1 J1_A3.1 R147_A3.1 R150_A3.2 RT3_A3.1 | length 5942.1
  Top Layer w8: J1_A3.1@6485.58,3824.46 6485.58,3757.91 6490.91,3752.57 v1(6490.91,3748.78) ; v1@6829.55,1205.53 6838.78,1214.76 R150_A3.2@6838.78,1275.25 ; v1(6831.44,1203.63) 6831.44,1199.84 6838.38,1192.9 6838.38,1160.96 R147_A3.1@6838.78,1160.56 ; v1(7736.79,2583.57) v1@7737.12,2583.9
  Signal Layer 2 w8: v1(6490.91,3748.78) 6515.38,3724.32 6515.38,3705.14 6783.31,3437.2 6783.31,2508.9 6758.54,2484.13 6758.54,1303.25 6777.69,1284.11 6777.69,1247.48 v1@6826.49,1198.68 ; v1(6831.44,1203.63) v1@6826.49,1198.68 ; v1(7736.79,2583.57) 7718.18,2583.57 7718.12,2583.51 7658.01,2583.51 7604.82,2530.32 6939.43,2530.32 6853.79,2444.68 6853.79,1368.15 6886.7,1335.23 7140.18,1335.23 7230.04,1245.38 7230.04,1200.87 7196.51,1167.34 6857.83,1167.34 v1@6826.49,1198.68
  Bottom Layer w8: C118_A3.1@6477.58,3791.95 6479.28,3790.26 6479.28,3764.21 6490.91,3752.57 v1(6490.91,3748.78) ; v1@7736.82,2583.54 7795.8,2583.54 RT3_A3.1@7796.23,2583.97
TS19_A4: C118_A4.1 J1_A4.1 R147_A4.1 R150_A4.2 RT3_A4.1 | length 5942.1
  Top Layer w8: J1_A4.1@8805.81,3821.25 8805.81,3754.7 8811.14,3749.37 v1(8811.14,3745.58) ; v1@9149.78,1202.32 9159.01,1211.55 R150_A4.2@9159.01,1272.04 ; v1(9151.67,1200.42) 9151.67,1196.63 9158.61,1189.69 9158.61,1157.75 R147_A4.1@9159.01,1157.35 ; v1(10057.02,2580.36) v1@10057.35,2580.7
  Signal Layer 2 w8: v1(8811.14,3745.58) 8835.61,3721.11 8835.61,3701.93 9103.54,3433.99 9103.54,2505.69 9078.77,2480.92 9078.77,1300.04 9097.92,1280.9 9097.92,1244.27 v1@9146.72,1195.47 ; v1(9151.67,1200.42) v1@9146.72,1195.47 ; v1(10057.02,2580.36) 10038.41,2580.36 10038.35,2580.3 9978.24,2580.3 9925.05,2527.11 9259.66,2527.11 9174.02,2441.47 9174.02,1364.94 9206.93,1332.03 9460.41,1332.03 9550.27,1242.17 9550.27,1197.66 9516.74,1164.13 9178.06,1164.13 v1@9146.72,1195.47
  Bottom Layer w8: C118_A4.1@8797.81,3788.75 8799.51,3787.05 8799.51,3761 8811.14,3749.37 v1(8811.14,3745.58) ; v1@10057.05,2580.33 10116.03,2580.33 RT3_A4.1@10116.46,2580.76
TS20_A1: C113_A1.1 J1_A1.2 R144_A1.1 R145_A1.2 RT4_A1.1 | length 6881.4
  Top Layer w8: J1_A1.2@1857.95,3972.62 1859.6,3974.27 v1@1859.6,4055.89 ; v1(2147.53,1197.66) v1@2153.54,1197.66 ; R144_A1.1@2153.54,1157.48 v1@2153.54,1197.66 ; R145_A1.2@2153.54,1272.18 v1@2153.54,1197.66 ; RT4_A1.1@3574.56,2582.39 3574.98,2581.97 3632.52,2581.97 v1(3632.94,2581.55)
  Signal Layer 2 w8: v1(1859.8,4061.75) 1859.8,3909.43 1836.42,3886.06 1836.42,3726.82 2130.2,3433.05 2130.2,2506.63 2111.06,2487.49 2111.06,1293.46 2130.2,1274.32 2130.2,1214.99 v1(2147.53,1197.66) 2196.93,1148.26 2590.48,1148.26 2627.95,1185.73 2627.95,1264.74 2544.8,1347.9 2264.91,1347.9 2238.05,1374.76 2238.05,2434.89 2313,2509.84 2999.93,2509.84 3039.3,2549.21 3572.3,2549.21 3605.05,2581.97 v1@3632.52,2581.97
  Bottom Layer w8: C113_A1.1@1859.8,4009.21 v1(1859.8,4061.75) ; v1@3632.52,2581.97 v1(3632.94,2581.55)
TS20_A2: C113_A2.1 J1_A2.2 R144_A2.1 R145_A2.2 RT4_A2.1 | length 6898.6
  Top Layer w8: J1_A2.2@4152.96,3972.62 4154.61,3974.27 v1@4154.61,4055.89 ; v1(4442.54,1197.66) v1@4448.56,1197.66 ; R144_A2.1@4448.56,1157.48 v1@4448.56,1197.66 ; R145_A2.2@4448.56,1272.18 v1@4448.56,1197.66 ; RT4_A2.1@5869.58,2582.39 5870,2581.97 5927.53,2581.97 v1(5927.95,2581.55)
  Signal Layer 2 w8: v1(4154.81,4061.75) 4154.81,3909.43 4131.44,3886.06 4131.44,3726.82 4425.21,3433.05 4425.21,2506.63 4397.36,2478.78 4397.36,1302.17 4425.21,1274.32 4425.21,1214.99 v1(4442.54,1197.66) 4491.95,1148.26 4885.5,1148.26 4922.97,1185.73 4922.97,1264.74 4839.81,1347.9 4667.65,1347.9 4664.98,1345.23 4562.59,1345.23 4533.07,1374.76 4533.07,1408.98 4524.36,1417.69 4524.36,2426.18 4608.02,2509.84 5294.94,2509.84 5334.31,2549.21 5867.31,2549.21 5900.07,2581.97 5927.53,2581.97 v1(5927.95,2581.55)
  Bottom Layer w8: C113_A2.1@4154.81,4009.21 v1(4154.81,4061.75) ; v1@5927.53,2581.97 v1(5927.95,2581.55)
TS20_A3: C113_A3.1 J1_A3.2 R144_A3.1 R145_A3.2 RT4_A3.1 | length 6881.4
  Top Layer w8: J1_A3.2@6489.56,3975.83 6491.21,3977.48 v1@6491.21,4059.1 ; v1(6779.14,1200.87) v1@6785.15,1200.87 ; R144_A3.1@6785.15,1160.69 v1@6785.15,1200.87 ; R145_A3.2@6785.15,1275.38 v1@6785.15,1200.87 ; RT4_A3.1@8206.18,2585.59 8206.59,2585.18 8264.13,2585.18 v1(8264.55,2584.76)
  Signal Layer 2 w8: v1(6491.41,4064.96) 6491.41,3912.64 6468.04,3889.27 6468.04,3730.03 6761.81,3436.25 6761.81,2509.84 6742.67,2490.7 6742.67,1296.67 6761.81,1277.53 6761.81,1218.2 v1(6779.14,1200.87) 6828.54,1151.47 7222.09,1151.47 7259.57,1188.94 7259.57,1267.95 7176.41,1351.11 6896.52,1351.11 6869.66,1377.96 6869.66,2438.1 6944.61,2513.05 7631.54,2513.05 7670.91,2552.42 8203.91,2552.42 8236.66,2585.18 v1@8264.13,2585.18
  Bottom Layer w8: C113_A3.1@6491.41,4012.42 v1(6491.41,4064.96) ; v1@8264.13,2585.18 v1(8264.55,2584.76)
TS20_A4: C113_A4.1 J1_A4.2 R144_A4.1 R145_A4.2 RT4_A4.1 | length 6881.4
  Top Layer w8: J1_A4.2@8809.79,3972.62 8811.44,3974.27 v1@8811.44,4055.89 ; v1(9099.37,1197.66) v1@9105.38,1197.66 ; R144_A4.1@9105.38,1157.49 v1@9105.38,1197.66 ; R145_A4.2@9105.38,1272.18 v1@9105.38,1197.66 ; RT4_A4.1@10526.41,2582.39 10526.82,2581.97 10584.36,2581.97 v1(10584.78,2581.55)
  Signal Layer 2 w8: v1(8811.64,4061.75) 8811.64,3909.43 8788.27,3886.06 8788.27,3726.82 9082.04,3433.05 9082.04,2506.63 9062.9,2487.49 9062.9,1293.46 9082.04,1274.32 9082.04,1214.99 v1(9099.37,1197.66) 9148.77,1148.26 9542.32,1148.26 9579.8,1185.73 9579.8,1264.74 9496.64,1347.9 9216.75,1347.9 9189.89,1374.76 9189.89,2434.89 9264.84,2509.84 9951.77,2509.84 9991.14,2549.21 10524.14,2549.21 10556.89,2581.97 v1@10584.36,2581.97
  Bottom Layer w8: C113_A4.1@8811.64,4009.21 v1(8811.64,4061.75) ; v1@10584.36,2581.97 v1(10584.78,2581.55)
TS_R1_A1: R148_A1.2 U3_A1.12 | length 305.9
  Bottom Layer w7: R148_A1.2@2303.15,1856.3 2303.15,1853.58 2294.84,1845.27 2285.77,1845.27 2281.67,1841.17 2281.67,1747.95 2321.98,1707.64 2401.97,1707.64 2409.77,1715.45 2409.77,1743.19 U3_A1.12@2415.13,1748.54
TS_R1_A2: R148_A2.2 U3_A2.12 | length 305.9
  Bottom Layer w7: R148_A2.2@4598.17,1856.3 4598.17,1853.58 4589.85,1845.27 4580.79,1845.27 4576.69,1841.17 4576.69,1747.95 4617,1707.64 4696.98,1707.64 4704.79,1715.45 4704.79,1743.19 U3_A2.12@4710.14,1748.54
TS_R1_A3: R148_A3.2 U3_A3.12 | length 305.9
  Bottom Layer w7: R148_A3.2@6934.76,1859.51 6934.76,1856.79 6926.45,1848.48 6917.39,1848.48 6913.28,1844.38 6913.28,1751.16 6953.6,1710.85 7033.58,1710.85 7041.38,1718.65 7041.38,1746.39 U3_A3.12@7046.74,1751.75
TS_R1_A4: R148_A4.2 U3_A4.12 | length 305.9
  Bottom Layer w7: R148_A4.2@9254.99,1856.3 9254.99,1853.58 9246.68,1845.27 9237.62,1845.27 9233.51,1841.17 9233.51,1747.95 9273.83,1707.64 9353.81,1707.64 9361.61,1715.45 9361.61,1743.19 U3_A4.12@9366.97,1748.54
TS_R2_A1: R151_A1.2 U2_A1.12 | length 67.1
  Top Layer w7: R151_A1.2@2461.06,1817.45 2466.31,1812.21 U2_A1.12@2466.31,1752.49
TS_R2_A2: R151_A2.2 U2_A2.12 | length 64.9
  Top Layer w7: R151_A2.2@4756.08,1817.45 4763.91,1809.62 U2_A2.12@4763.91,1755.85
TS_R2_A3: R151_A3.2 U2_A3.12 | length 64.9
  Top Layer w7: R151_A3.2@7092.67,1820.66 7100.99,1812.35 7100.99,1759.72 U2_A3.12@7101.36,1759.35
TS_R2_A4: R151_A4.2 U2_A4.12 | length 68.5
  Top Layer w7: R151_A4.2@9412.9,1817.45 9421.22,1809.14 9421.22,1754.18 U2_A4.12@9422.5,1752.89
TSREF_A1: C46_A1.2 R144_A1.2 R146_A1.2 R147_A1.2 R152_A1.2 R156_A1.2 R158_A1.2 R161_A1.2 R162_A1.2 U1_A1.50 | length 3573.2
  Top Layer w7: U1_A1.50@3433.88,1179 3436.28,1176.6 3466.97,1176.6 3475.04,1168.54 3514.26,1168.54 C46_A1.2@3524.71,1158.09 ; C46_A1.2@3525.69,1158.09 3547.88,1180.28 3547.88,1186.41 v1(3550.76,1189.29)
  Top Layer w12: v1(2269.82,1495.14) 2231.73,1457.05 2226.67,1457.05 2122.65,1353.03 2122.65,1141.2 2135.98,1127.86 2139.85,1127.86 2153.54,1114.18 R144_A1.2@2153.54,1110.24 2154.13,1110.83 2207.17,1110.83 2261.06,1110.83 2316.07,1110.83 2371.08,1110.83 2426.09,1110.83 2481.1,1110.83 2535.51,1110.83 R152_A1.2@2536.11,1111.43
  Signal Layer 2 w12: v1(2269.82,1495.14) 2414.08,1639.4 2414.08,1930.16 2421.11,1937.19 3643.28,1937.19 3730.31,1850.15 3730.31,1390.17 3552.67,1212.52 3552.67,1191.2 v1(3550.76,1189.29)
TSREF_A2: C46_A2.2 R144_A2.2 R146_A2.2 R147_A2.2 R152_A2.2 R156_A2.2 R158_A2.2 R161_A2.2 R162_A2.2 U1_A2.50 | length 3573.2
  Top Layer w7: U1_A2.50@5728.89,1179 5731.3,1176.6 5761.99,1176.6 5770.05,1168.54 5809.28,1168.54 C46_A2.2@5819.72,1158.09 ; C46_A2.2@5820.71,1158.09 5842.9,1180.28 5842.9,1186.41 v1(5845.77,1189.29)
  Top Layer w12: v1(4564.84,1495.14) 4526.74,1457.05 4521.68,1457.05 4417.67,1353.03 4417.67,1141.2 4431,1127.86 4434.87,1127.86 4448.56,1114.18 R144_A2.2@4448.56,1110.24 4449.15,1110.83 4502.19,1110.83 4556.08,1110.83 4611.09,1110.83 4666.1,1110.83 4721.11,1110.83 4776.11,1110.83 4830.53,1110.83 R152_A2.2@4831.12,1111.43
  Signal Layer 2 w12: v1(4564.84,1495.14) 4709.1,1639.4 4709.1,1930.16 4716.12,1937.19 5938.3,1937.19 6025.33,1850.15 6025.33,1390.17 5847.69,1212.52 5847.69,1191.2 v1(5845.77,1189.29)
TSREF_A3: C46_A3.2 R144_A3.2 R146_A3.2 R147_A3.2 R152_A3.2 R156_A3.2 R158_A3.2 R161_A3.2 R162_A3.2 U1_A3.50 | length 3573.2
  Top Layer w7: U1_A3.50@8065.49,1182.21 8067.9,1179.81 8098.59,1179.81 8106.65,1171.74 8145.87,1171.74 C46_A3.2@8156.32,1161.3 ; C46_A3.2@8157.3,1161.3 8179.5,1183.49 8179.5,1189.62 v1(8182.37,1192.49)
  Top Layer w12: v1(6901.44,1498.35) 6863.34,1460.25 6858.28,1460.25 6754.26,1356.24 6754.26,1144.4 6767.59,1131.07 6771.47,1131.07 6785.15,1117.39 R144_A3.2@6785.15,1113.45 6785.74,1114.04 6838.78,1114.04 6892.68,1114.04 6947.69,1114.04 7002.69,1114.04 7057.7,1114.04 7112.71,1114.04 7167.13,1114.04 R152_A3.2@7167.72,1114.63
  Signal Layer 2 w12: v1(6901.44,1498.35) 7045.69,1642.61 7045.69,1933.37 7052.72,1940.4 8274.89,1940.4 8361.93,1853.36 8361.93,1393.38 8184.28,1215.73 8184.28,1194.41 v1(8182.37,1192.49)
TSREF_A4: C46_A4.2 R144_A4.2 R146_A4.2 R147_A4.2 R152_A4.2 R156_A4.2 R158_A4.2 R161_A4.2 R162_A4.2 U1_A4.50 | length 3573.2
  Top Layer w7: U1_A4.50@10385.72,1179 10388.12,1176.6 10418.82,1176.6 10426.88,1168.54 10466.1,1168.54 C46_A4.2@10476.55,1158.09 ; C46_A4.2@10477.53,1158.09 10499.73,1180.28 10499.73,1186.41 v1(10502.6,1189.29)
  Top Layer w12: v1(9221.67,1495.14) 9183.57,1457.05 9178.51,1457.05 9074.49,1353.03 9074.49,1141.2 9087.82,1127.86 9091.7,1127.86 9105.38,1114.18 R144_A4.2@9105.38,1110.24 9105.97,1110.83 9159.01,1110.83 9212.91,1110.83 9267.92,1110.83 9322.92,1110.83 9377.93,1110.83 9432.94,1110.83 9487.36,1110.83 R152_A4.2@9487.95,1111.43
  Signal Layer 2 w12: v1(9221.67,1495.14) 9365.92,1639.4 9365.92,1930.16 9372.95,1937.19 10595.12,1937.19 10682.16,1850.16 10682.16,1390.17 10504.51,1212.52 10504.51,1191.2 v1(10502.6,1189.29)
TX/GPIO1_A1: C110_A1.1 R145_A1.1 R209.1 U1_A1.52 | length 3447.7
  Top Layer w7: R145_A1.1@2153.54,1319.42 2158.51,1314.45 2236.69,1392.63 2257.41,1392.63 2262.36,1397.59 2263.22,1397.59 2269.02,1403.39 2273.97,1403.39 2289.04,1418.46 v1(2290.81,1418.46) ; U1_A1.52@3463.22,1218.37 U1_A1.52@3433.88,1218.37 3436.28,1215.97 3468.86,1215.97 3471.31,1213.51 3497.43,1213.51 3501.2,1217.28 v1(3505.26,1217.28)
  Signal Layer 2 w7: v1(2290.81,1418.46) 2287.94,1421.33 2287.94,1436.69 2284.74,1439.89 2284.74,1457.38 2376.7,1549.34 2376.7,1552.3 2446.33,1621.92 2446.33,1900.84 2450.43,1904.94 3614.56,1904.94 3690.89,1828.6 3690.89,1402.92 v1(3505.26,1217.28)
  Bottom Layer w7: R209.1@2051.18,1003.94 2055.12,1003.94 2096.46,1045.28 2096.46,1238.81 2215.92,1358.27 2230.62,1358.27 v1(2290.81,1418.46) ; v1(3505.26,1217.28) 3528.38,1194.16 3528.38,1180.02 3541.49,1166.91 3560.03,1166.91 3571.14,1178.02 C110_A1.1@3589.84,1178.02
TX/GPIO1_A2: C110_A2.1 R145_A2.1 U1_A2.52 | length 2924.6
  Top Layer w7: R145_A2.1@4448.56,1319.42 4453.52,1314.45 4531.71,1392.63 4552.43,1392.63 4557.38,1397.59 4558.23,1397.59 4564.04,1403.39 4568.99,1403.39 4584.06,1418.46 v1(4584.33,1418.46) ; U1_A2.52@5758.23,1218.37 U1_A2.52@5728.89,1218.37 5731.3,1215.97 5763.87,1215.97 5766.33,1213.51 5792.44,1213.51 5796.21,1217.28 v1(5800.28,1217.28)
  Signal Layer 2 w7: v1(4584.33,1418.46) 4581.46,1421.33 4581.46,1438.19 4579.76,1439.89 4579.76,1457.38 4671.72,1549.34 4671.72,1552.3 4741.34,1621.92 4741.34,1900.84 4745.44,1904.94 5909.57,1904.94 5985.91,1828.6 5985.91,1402.92 v1(5800.28,1217.28)
  Bottom Layer w7: v1@4584.33,1414.76 v1(4584.33,1418.46) ; v1(5800.28,1217.28) 5823.39,1194.16 5823.39,1180.02 5836.5,1166.91 5855.04,1166.91 5866.15,1178.02 C110_A2.1@5884.86,1178.02
TX/GPIO1_A3: C110_A3.1 R145_A3.1 U1_A3.52 | length 2923
  Top Layer w7: R145_A3.1@6785.15,1322.63 6790.12,1317.66 6868.3,1395.84 6889.02,1395.84 6893.98,1400.79 6894.83,1400.79 6900.64,1406.6 6905.59,1406.6 6920.65,1421.67 v1(6922.42,1421.67) ; U1_A3.52@8094.83,1221.58 U1_A3.52@8065.49,1221.58 8067.9,1219.18 8100.47,1219.18 8102.93,1216.72 8129.04,1216.72 8132.81,1220.49 v1(8136.87,1220.49)
  Signal Layer 2 w7: v1(6922.42,1421.67) 6919.55,1424.54 6919.55,1439.9 6916.35,1443.1 6916.35,1460.59 7008.31,1552.55 7008.31,1555.5 7077.94,1625.13 7077.94,1904.05 7082.04,1908.15 8246.17,1908.15 8322.51,1831.81 8322.51,1406.13 v1(8136.87,1220.49)
  Bottom Layer w7: v1(8136.87,1220.49) 8159.99,1197.37 8159.99,1183.23 8173.1,1170.12 8191.64,1170.12 8202.75,1181.23 C110_A3.1@8221.45,1181.23
TX/GPIO1_A4: C110_A4.1 R145_A4.1 U1_A4.52 | length 2923
  Top Layer w7: R145_A4.1@9105.38,1319.42 9110.35,1314.45 9188.53,1392.63 9209.25,1392.63 9214.21,1397.59 9215.06,1397.59 9220.86,1403.39 9225.81,1403.39 9240.88,1418.46 v1(9242.65,1418.46) ; U1_A4.52@10415.06,1218.37 U1_A4.52@10385.72,1218.37 10388.12,1215.97 10420.7,1215.97 10423.16,1213.51 10449.27,1213.51 10453.04,1217.28 v1(10457.1,1217.28)
  Signal Layer 2 w7: v1(9242.65,1418.46) 9239.78,1421.33 9239.78,1436.69 9236.58,1439.89 9236.58,1457.38 9328.54,1549.34 9328.54,1552.3 9398.17,1621.92 9398.17,1900.84 9402.27,1904.94 10566.4,1904.94 10642.74,1828.6 10642.74,1402.92 v1(10457.1,1217.28)
  Bottom Layer w7: v1(10457.1,1217.28) 10480.22,1194.16 10480.22,1180.02 10493.33,1166.91 10511.87,1166.91 10522.98,1178.02 C110_A4.1@10541.68,1178.02
VC0_A1: C106_A1.2 C107_A1.1 R139_A1.2 U1_A1.40 | length 3747.9
  Top Layer w8: R139_A1.2@2801.57,3384.01 2801.57,3380.08 2793.76,3372.26 2773.05,3372.26 2749.31,3348.52 2660.03,3348.52 2640.4,3328.88 2442.96,3328.88 2316.84,3202.76 2316.84,1971.92 2347.83,1940.92 2349.27,1940.92 2353,1937.19 2566.67,1937.19 2591.76,1912.1 2591.76,1869.72 2601.61,1859.87 2601.61,1730.44 2583.51,1712.34 2583.51,1185.27 2921.15,847.63 3012.01,847.63 3052.93,888.56 3070.87,888.56 3072.81,888.56 C107_A1.1@3072.86,888.51 ; C107_A1.1@3070.87,885.83 3074.12,885.83 3084.61,896.32 3084.61,904.58 3099.16,919.12 C106_A1.2@3099.16,942.93 3103.09,942.93 3110.9,950.75 3118.41,950.75 3168.93,1001.27 3186.79,1001.27 3190.13,1004.61 3190.84,1004.61 3200.91,1014.67 3200.91,1081.26 U1_A1.40@3199.62,1082.55
VC0_A2: C106_A2.2 C107_A2.1 R139_A2.2 U1_A2.40 | length 3752
  Top Layer w8: R139_A2.2@5096.59,3384.01 5096.59,3380.08 5088.78,3372.26 5068.07,3372.26 5044.32,3348.52 4955.05,3348.52 4935.41,3328.88 4737.98,3328.88 4611.85,3202.76 4611.85,1971.92 4642.85,1940.92 4644.29,1940.92 4648.02,1937.19 4861.69,1937.19 4886.78,1912.1 4886.78,1884.87 4901.57,1870.08 4901.57,1730.36 4878.53,1707.32 4878.53,1185.27 5216.17,847.63 5307.02,847.63 5347.95,888.56 5365.88,888.56 5367.83,888.56 C107_A2.1@5367.88,888.51 ; C107_A2.1@5365.88,885.83 5369.14,885.83 5379.63,896.32 5379.63,904.58 5394.17,919.12 C106_A2.2@5394.17,942.93 5398.11,942.93 5405.92,950.75 5413.42,950.75 5463.95,1001.27 5481.81,1001.27 5485.15,1004.61 5485.86,1004.61 5495.92,1014.67 5495.92,1081.26 U1_A2.40@5494.64,1082.55
VC0_A3: C106_A3.2 C107_A3.1 R139_A3.2 U1_A3.40 | length 3743.2
  Top Layer w8: R139_A3.2@7433.19,3387.22 7433.19,3383.28 7425.37,3375.47 7404.67,3375.47 7380.92,3351.73 7291.64,3351.73 7272.01,3332.09 7074.57,3332.09 6948.45,3205.97 6948.45,1975.12 6979.45,1944.13 6980.88,1944.13 6984.61,1940.4 7198.29,1940.4 7223.38,1915.31 7223.38,1864.08 7227.59,1859.87 7227.59,1722.99 7215.12,1710.52 7215.12,1188.48 7552.76,850.84 7643.62,850.84 7684.55,891.77 7702.48,891.77 7704.42,891.77 C107_A3.1@7704.48,891.71 ; C107_A3.1@7702.48,889.04 7705.73,889.04 7716.22,899.53 7716.22,907.79 7730.77,922.33 C106_A3.2@7730.77,946.14 7734.71,946.14 7742.52,953.95 7750.02,953.95 7800.55,1004.48 7818.41,1004.48 7821.74,1007.82 7822.46,1007.82 7832.52,1017.88 7832.52,1084.47 U1_A3.40@7831.24,1085.75
VC0_A4: C106_A4.2 C107_A4.1 R139_A4.2 U1_A4.40 | length 3747.6
  Top Layer w8: R139_A4.2@9753.42,3384.01 9753.42,3380.08 9745.6,3372.26 9724.9,3372.26 9701.15,3348.52 9611.87,3348.52 9592.24,3328.88 9394.8,3328.88 9268.68,3202.76 9268.68,1971.92 9299.68,1940.92 9301.11,1940.92 9304.84,1937.19 9518.52,1937.19 9548.6,1907.11 9548.6,1878.57 9557.09,1870.08 9557.09,1729.05 9535.35,1707.32 9535.35,1185.27 9872.99,847.63 9963.85,847.63 10004.78,888.56 10022.71,888.56 10024.65,888.56 C107_A4.1@10024.71,888.51 ; C107_A4.1@10025.96,885.83 10036.45,896.32 10036.45,904.58 10051,919.12 C106_A4.2@10051,942.93 10054.94,942.93 10062.75,950.75 10070.25,950.75 10120.78,1001.27 10138.64,1001.27 10141.97,1004.61 10142.69,1004.61 10152.75,1014.67 10152.75,1081.26 U1_A4.40@10151.47,1082.55
VC1_A1: C105_A1.2 C106_A1.1 R138_A1.2 U1_A1.38 | length 3707.2
  Top Layer w8: R138_A1.2@2858.44,3384.01 2834.63,3384.01 2825.26,3374.64 2825.26,3363.35 2794.55,3332.64 2666.61,3332.64 2646.97,3313.01 2449.53,3313.01 2332.71,3196.18 2332.71,1978.49 2354.41,1956.79 2355.85,1956.79 2359.57,1953.06 2573.25,1953.06 2607.64,1918.68 2607.64,1876.29 2617.49,1866.44 2617.49,1723.87 2599.39,1705.76 2599.39,1191.85 2927.73,863.5 2980.64,863.5 2987.59,870.46 2987.59,871.51 3001.94,885.85 C105_A1.2@3009.79,885.83 ; C105_A1.2@3007.21,887.19 3008.58,885.83 C105_A1.2@3009.79,885.83 ; U1_A1.38@3160.25,1082.55 3159.15,1081.44 3159.15,1041.02 3155.15,1037.02 3155.15,1012.28 3109.49,966.62 3078.49,966.62 3071.53,959.66 3071.53,958.62 3055.85,942.93 C106_A1.1@3051.91,942.93 3047.98,942.93 3040.16,935.12 3040.16,916.2 C105_A1.2@3009.79,885.83
VC1_A2: C105_A2.2 C106_A2.1 R138_A2.2 U1_A2.38 | length 3710
  Top Layer w8: R138_A2.2@5153.46,3384.01 5129.65,3384.01 5120.27,3374.64 5120.27,3363.35 5089.57,3332.64 4961.62,3332.64 4941.99,3313.01 4744.55,3313.01 4627.73,3196.18 4627.73,1978.49 4649.42,1956.79 4650.86,1956.79 4654.59,1953.06 4868.27,1953.06 4902.65,1918.68 4902.65,1891.45 4917.45,1876.65 4917.45,1723.79 4910.79,1717.13 4894.4,1700.74 4894.4,1191.85 5222.74,863.5 5275.65,863.5 5282.61,870.46 5282.61,871.51 C105_A2.2@5296.96,885.85 ; C105_A2.2@5296.98,885.83 5304.8,885.83 5335.18,916.2 5335.18,935.12 5342.99,942.93 C106_A2.1@5346.93,942.93 5350.87,942.93 5366.55,958.62 5366.55,959.66 5373.51,966.62 5404.51,966.62 5450.17,1012.28 5450.17,1037.02 5454.17,1041.02 5454.17,1081.44 U1_A2.38@5455.27,1082.55 ; C105_A2.2@5302.23,887.19 C105_A2.2@5303.59,885.83
VC1_A3: C105_A3.2 C106_A3.1 R138_A3.2 U1_A3.38 | length 3702.5
  Top Layer w8: R138_A3.2@7490.05,3387.22 7466.24,3387.22 7456.87,3377.85 7456.87,3366.55 7426.17,3335.85 7298.22,3335.85 7278.58,3316.22 7081.15,3316.22 6964.32,3199.39 6964.32,1981.7 6986.02,1960 6987.46,1960 6991.19,1956.27 7204.86,1956.27 7239.25,1921.88 7239.25,1870.65 7243.46,1866.44 7243.46,1716.41 7231,1703.95 7231,1195.05 7559.34,866.71 7612.25,866.71 7619.2,873.67 7619.2,874.71 C105_A3.2@7633.55,889.06 ; C105_A3.2@7633.58,889.04 C105_A3.2@7641.4,889.04 ; C105_A3.2@7638.83,890.4 7640.19,889.04 C105_A3.2@7641.4,889.04 ; U1_A3.38@7791.87,1085.75 7790.76,1084.65 7790.76,1044.23 7786.76,1040.23 7786.76,1015.49 7741.11,969.83 7710.1,969.83 7703.15,962.87 7703.15,961.83 7687.46,946.14 C106_A3.1@7683.53,946.14 7679.59,946.14 7671.78,938.33 7671.78,919.41 C105_A3.2@7641.4,889.04
VC1_A4: C105_A4.2 C106_A4.1 R138_A4.2 U1_A4.38 | length 3709
  Top Layer w8: R138_A4.2@9810.28,3384.01 9786.47,3384.01 9777.1,3374.64 9777.1,3363.35 9746.4,3332.64 9618.45,3332.64 9598.81,3313.01 9401.38,3313.01 9284.55,3196.18 9284.55,1978.49 9306.25,1956.79 9307.69,1956.79 9311.42,1953.06 9525.09,1953.06 9564.47,1913.68 9564.47,1885.14 9572.96,1876.65 9572.96,1722.47 9566.29,1715.8 9551.23,1700.74 9551.23,1191.85 9879.57,863.51 9932.48,863.51 9939.43,870.46 9939.43,871.51 9953.78,885.85 9961.63,885.83 9992.01,916.2 9992.01,935.12 9999.82,942.93 C106_A4.1@10003.76,942.93 10007.69,942.93 10023.38,958.62 10023.38,959.66 10030.33,966.62 10061.34,966.62 10106.99,1012.28 10106.99,1037.02 10110.99,1041.02 10110.99,1081.44 U1_A4.38@10112.1,1082.55 ; C105_A4.2@9959.06,887.19 C105_A4.2@9960.42,885.83
VC2_A1: C104_A1.2 C105_A1.1 R135_A1.2 U1_A1.36 | length 3674.8
  Top Layer w8: R135_A1.2@2915.31,3384.01 2891.5,3384.01 2883.33,3375.85 2883.33,3364.55 2851.42,3332.64 2817,3332.64 2801.13,3316.77 2673.18,3316.77 2653.55,3297.13 2456.11,3297.13 2348.58,3189.61 2348.58,1985.07 2360.98,1972.67 2362.42,1972.67 2366.15,1968.94 2579.82,1968.94 2623.51,1925.25 2623.51,1882.87 2633.36,1873.02 2633.36,1717.29 2615.26,1699.19 2615.26,1198.42 2926.49,887.19 C105_A1.1@2952.76,887.19 ; C105_A1.1@2952.76,885.83 C105_A1.1@2962.54,885.83 ; C105_A1.1@2959.97,887.19 2961.33,885.83 C105_A1.1@2962.54,885.83 ; U1_A1.36@3120.88,1082.55 3120.88,1042.72 3100.39,1022.22 3100.39,1015.88 3079.89,995.39 3021.25,995.39 3001.2,975.34 3001.2,955.77 2993.39,947.96 C104_A1.2@2989.45,947.96 2989.45,924.15 2971.72,906.42 2971.72,895 C105_A1.1@2962.54,885.83
VC2_A2: C104_A2.2 C105_A2.1 R135_A2.2 U1_A2.36 | length 3677.7
  Top Layer w8: R135_A2.2@5210.32,3384.01 5186.51,3384.01 5178.35,3375.85 5178.35,3364.55 5146.44,3332.64 5112.02,3332.64 5096.15,3316.77 4968.2,3316.77 4948.56,3297.13 4751.13,3297.13 4643.6,3189.61 4643.6,1985.07 4656,1972.67 4657.44,1972.67 4661.17,1968.94 4874.84,1968.94 4918.53,1925.25 4918.53,1898.02 4933.32,1883.23 4933.32,1717.21 4926.66,1710.55 4910.28,1694.16 4910.28,1198.42 5221.51,887.19 C105_A2.1@5247.77,887.19 ; C105_A2.1@5247.77,885.83 5257.56,885.83 5266.73,895 5266.73,906.42 5284.47,924.15 C104_A2.2@5284.47,947.96 5288.4,947.96 5296.22,955.77 5296.22,975.34 5316.27,995.39 5374.91,995.39 5395.4,1015.88 5395.4,1022.22 5415.9,1042.72 U1_A2.36@5415.9,1082.55 ; C105_A2.1@5254.99,887.19 C105_A2.1@5256.35,885.83
VC2_A3: C104_A3.2 C105_A3.1 R135_A3.2 U1_A3.36 | length 3670.2
  Top Layer w8: R135_A3.2@7546.92,3387.22 7523.11,3387.22 7514.95,3379.06 7514.95,3367.76 7483.04,3335.85 7448.62,3335.85 7432.74,3319.98 7304.79,3319.98 7285.16,3300.34 7087.72,3300.34 6980.2,3192.82 6980.2,1988.27 6992.6,1975.87 6994.04,1975.87 6997.76,1972.15 7211.44,1972.15 7255.12,1928.46 7255.12,1877.23 7259.34,1873.02 7259.34,1709.84 7246.87,1697.37 7246.87,1201.63 7558.1,890.4 C105_A3.1@7584.37,890.4 ; C105_A3.1@7584.37,889.04 C105_A3.1@7594.16,889.04 ; C105_A3.1@7591.58,890.4 7592.94,889.04 C105_A3.1@7594.16,889.04 ; U1_A3.36@7752.5,1085.75 7752.5,1045.93 7732,1025.43 7732,1019.09 7711.51,998.6 7652.86,998.6 7632.81,978.54 7632.81,958.98 7625,951.17 C104_A3.2@7621.06,951.17 7621.06,927.36 7603.33,909.63 7603.33,898.21 C105_A3.1@7594.16,889.04
VC2_A4: C104_A4.2 C105_A4.1 R135_A4.2 U1_A4.36 | length 3676.6
  Top Layer w8: R135_A4.2@9867.15,3384.01 9843.34,3384.01 9835.18,3375.85 9835.18,3364.55 9803.27,3332.64 9768.85,3332.64 9752.97,3316.77 9625.02,3316.77 9605.39,3297.13 9407.95,3297.13 9300.43,3189.61 9300.43,1985.07 9312.83,1972.67 9314.27,1972.67 9317.99,1968.94 9531.67,1968.94 9580.35,1920.26 9580.35,1891.72 9588.83,1883.23 9588.83,1715.9 9582.17,1709.23 9567.1,1694.16 9567.1,1198.42 9878.33,887.19 C105_A4.1@9904.6,887.19 ; C105_A4.1@9904.6,885.83 9914.39,885.83 9923.56,895 9923.56,906.42 9941.29,924.15 C104_A4.2@9941.29,947.96 9945.23,947.96 9953.04,955.77 9953.04,975.34 9973.09,995.39 10031.74,995.39 10052.23,1015.88 10052.23,1022.22 10072.73,1042.72 U1_A4.36@10072.73,1082.55 ; C105_A4.1@9911.81,887.19 C105_A4.1@9913.17,885.83
VC3_A1: C102_A1.2 C104_A1.1 R132_A1.2 U1_A1.34 | length 3044.7
  Top Layer w8: C102_A1.2@2772.92,1088 C102_A1.2@2770.21,1088 2770.21,1091.94 2754.53,1107.63 2753.48,1107.63 2688.89,1172.22 2688.89,1177.63 2688.3,1178.22 2688.3,1183.75 2631.13,1240.91 2631.13,1692.61 2649.24,1710.71 2649.24,1879.59 2639.39,1889.44 2639.39,1968.21 2648.46,1977.29 2648.46,3212.66 2736.7,3300.89 2807.71,3300.89 2823.58,3316.77 2892.42,3316.77 2938.99,3363.35 2938.99,3374.64 2948.37,3384.01 R132_A1.2@2972.18,3384.01 ; C102_A1.2@2772.92,1090.71 2775.81,1087.81 2781.34,1087.81 2914.46,954.69 2935.48,954.69 C104_A1.1@2942.21,947.96 2946.14,947.96 2953.95,955.77 2953.95,956.82 3038.28,1041.14 3071.51,1041.14 3079.61,1049.24 3079.61,1080.64 U1_A1.34@3081.51,1082.55
VC3_A2: C102_A2.2 C104_A2.1 R132_A2.2 U1_A2.34 | length 3047.7
  Top Layer w8: R132_A2.2@5267.19,3384.01 5243.38,3384.01 5234.01,3374.64 5234.01,3363.35 5187.43,3316.77 5118.6,3316.77 5102.72,3300.89 5031.72,3300.89 4943.48,3212.66 4943.48,1977.29 4934.4,1968.21 4934.4,1904.6 4949.2,1889.8 4949.2,1710.64 4942.54,1703.98 4926.15,1687.59 4926.15,1240.91 4983.31,1183.75 4983.31,1178.22 4983.9,1177.63 4983.9,1172.22 5048.5,1107.63 5049.54,1107.63 5065.23,1091.94 C102_A2.2@5065.23,1088 5065.42,1087.81 5076.36,1087.81 5209.47,954.69 5230.49,954.69 C104_A2.1@5237.22,947.96 5241.16,947.96 5248.97,955.77 5248.97,956.82 5333.3,1041.14 5366.53,1041.14 5374.63,1049.24 5374.63,1080.64 U1_A2.34@5376.53,1082.55
VC3_A3: C102_A3.2 C104_A3.1 R132_A3.2 U1_A3.34 | length 3040
  Top Layer w8: C102_A3.2@7404.53,1091.21 C102_A3.2@7401.82,1091.21 7401.82,1095.15 7386.14,1110.83 7385.09,1110.83 7320.5,1175.43 7320.5,1180.84 7319.91,1181.43 7319.91,1186.96 7262.75,1244.12 7262.75,1690.8 7275.21,1703.26 7275.21,1879.59 7271,1883.8 7271,1971.42 7280.08,1980.5 7280.08,3215.86 7368.32,3304.1 7439.32,3304.1 7455.19,3319.98 7524.03,3319.98 7570.61,3366.55 7570.61,3377.85 7579.98,3387.22 R132_A3.2@7603.79,3387.22 ; C102_A3.2@7404.53,1093.92 7407.43,1091.02 7412.95,1091.02 7546.07,957.9 7567.09,957.9 C104_A3.1@7573.82,951.17 7577.76,951.17 7585.57,958.98 7585.57,960.03 7669.89,1044.35 7703.12,1044.35 7711.22,1052.45 7711.22,1083.85 U1_A3.34@7713.13,1085.75
VC3_A4: C102_A4.2 C104_A4.1 R132_A4.2 U1_A4.34 | length 3042.4
  Top Layer w8: R132_A4.2@9924.02,3384.01 9900.21,3384.01 9890.84,3374.64 9890.84,3363.35 9844.26,3316.77 9775.42,3316.77 9759.55,3300.89 9688.55,3300.89 9600.31,3212.66 9600.31,1977.29 9596.22,1973.21 9596.22,1898.29 9604.71,1889.8 9604.71,1709.32 9582.98,1687.59 9582.98,1240.91 9640.14,1183.75 9640.14,1178.22 9640.73,1177.63 9640.73,1172.22 9705.32,1107.63 9706.37,1107.63 9722.05,1091.94 C102_A4.2@9722.05,1088 9722.25,1087.81 9733.18,1087.81 9866.3,954.69 9887.32,954.69 C104_A4.1@9894.05,947.96 9897.99,947.96 9905.8,955.77 9905.8,956.82 9990.12,1041.14 10023.35,1041.14 10031.45,1049.24 10031.45,1080.64 U1_A4.34@10033.36,1082.55
VC4_A1: C101_A1.2 C102_A1.1 R128_A1.2 U1_A1.32 | length 2819.9
  Top Layer w8: C101_A1.2@2821.79,1120.47 2821.79,1124.4 2813.97,1132.21 2810.04,1132.21 2807.2,1135.05 2770.4,1135.05 C102_A1.1@2770.21,1135.25 2770.21,1138.99 2762.4,1146.8 2747.69,1146.8 2647.01,1247.49 2647.01,1686.04 2665.11,1704.14 2665.11,1886.17 2655.26,1896.02 2655.26,1961.64 2664.34,1970.72 2664.34,3206.08 2743.28,3285.02 2814.28,3285.02 2830.15,3300.89 2949.86,3300.89 3029.04,3380.08 R128_A1.2@3029.04,3384.01 ; C101_A1.2@2826.12,1124.4 2833.93,1132.21 2900.97,1132.21 2911.82,1143.06 2945.18,1143.06 2961.44,1159.32 U1_A1.32@2985.06,1159.32
VC4_A2: C101_A2.2 C102_A2.1 R128_A2.2 U1_A2.32 | length 2824
  Top Layer w8: C101_A2.2@5116.8,1120.47 5116.8,1124.4 5108.99,1132.21 5105.05,1132.21 5102.21,1135.05 5065.42,1135.05 C102_A2.1@5065.23,1135.25 5065.23,1138.99 5057.42,1146.8 5042.71,1146.8 4942.02,1247.49 4942.02,1681.01 4958.41,1697.4 4965.07,1704.06 4965.07,1896.38 4950.28,1911.17 4950.28,1961.64 4959.35,1970.72 4959.35,3206.08 5038.29,3285.02 5109.3,3285.02 5125.17,3300.89 5244.88,3300.89 5324.06,3380.08 R128_A2.2@5324.06,3384.01 ; C101_A2.2@5121.14,1124.4 5128.95,1132.21 5195.98,1132.21 5206.83,1143.06 5240.2,1143.06 5256.45,1159.32 U1_A2.32@5280.07,1159.32
VC4_A3: C101_A3.2 C102_A3.1 R128_A3.2 U1_A3.32 | length 2815.3
  Top Layer w8: C101_A3.2@7453.4,1123.67 7453.4,1127.61 7445.59,1135.42 7441.65,1135.42 7438.81,1138.26 7402.02,1138.26 C102_A3.1@7401.82,1138.46 7401.82,1142.2 7394.01,1150.01 7379.3,1150.01 7278.62,1250.69 7278.62,1684.22 7291.08,1696.69 7291.08,1886.17 7286.87,1890.38 7286.87,1964.85 7295.95,1973.93 7295.95,3209.29 7374.89,3288.23 7445.89,3288.23 7461.77,3304.1 7581.48,3304.1 7660.66,3383.28 R128_A3.2@7660.66,3387.22 ; C101_A3.2@7457.73,1127.61 7465.54,1135.42 7532.58,1135.42 7543.43,1146.27 7576.79,1146.27 7593.05,1162.53 U1_A3.32@7616.67,1162.53
VC4_A4: C101_A4.2 C102_A4.1 R128_A4.2 U1_A4.32 | length 2818.8
  Top Layer w8: C101_A4.2@9773.63,1120.47 9773.63,1124.4 9765.82,1132.21 9761.88,1132.21 9759.04,1135.05 9722.25,1135.05 C102_A4.1@9722.05,1135.25 9722.05,1138.99 9714.24,1146.8 9699.53,1146.8 9598.85,1247.49 9598.85,1681.01 9620.58,1702.75 9620.58,1896.38 9612.09,1904.87 9612.09,1966.63 9616.18,1970.72 9616.18,3206.08 9695.12,3285.02 9766.12,3285.02 9782,3300.89 9901.71,3300.89 9980.89,3380.08 R128_A4.2@9980.89,3384.01 ; C101_A4.2@9777.96,1124.4 9785.77,1132.21 9852.81,1132.21 9863.66,1143.06 9897.02,1143.06 9913.28,1159.32 U1_A4.32@9936.9,1159.32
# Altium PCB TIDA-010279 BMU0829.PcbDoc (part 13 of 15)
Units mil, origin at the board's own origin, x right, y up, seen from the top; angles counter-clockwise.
Board outline 11269.69 x 4438.98 mil, 4 copper layers (Top Layer, Signal Layer 1, Signal Layer 2, Bottom Layer), stack 61.6 mil thick; 1437 components, 728 nets, 3667 pads, 2806 vias.

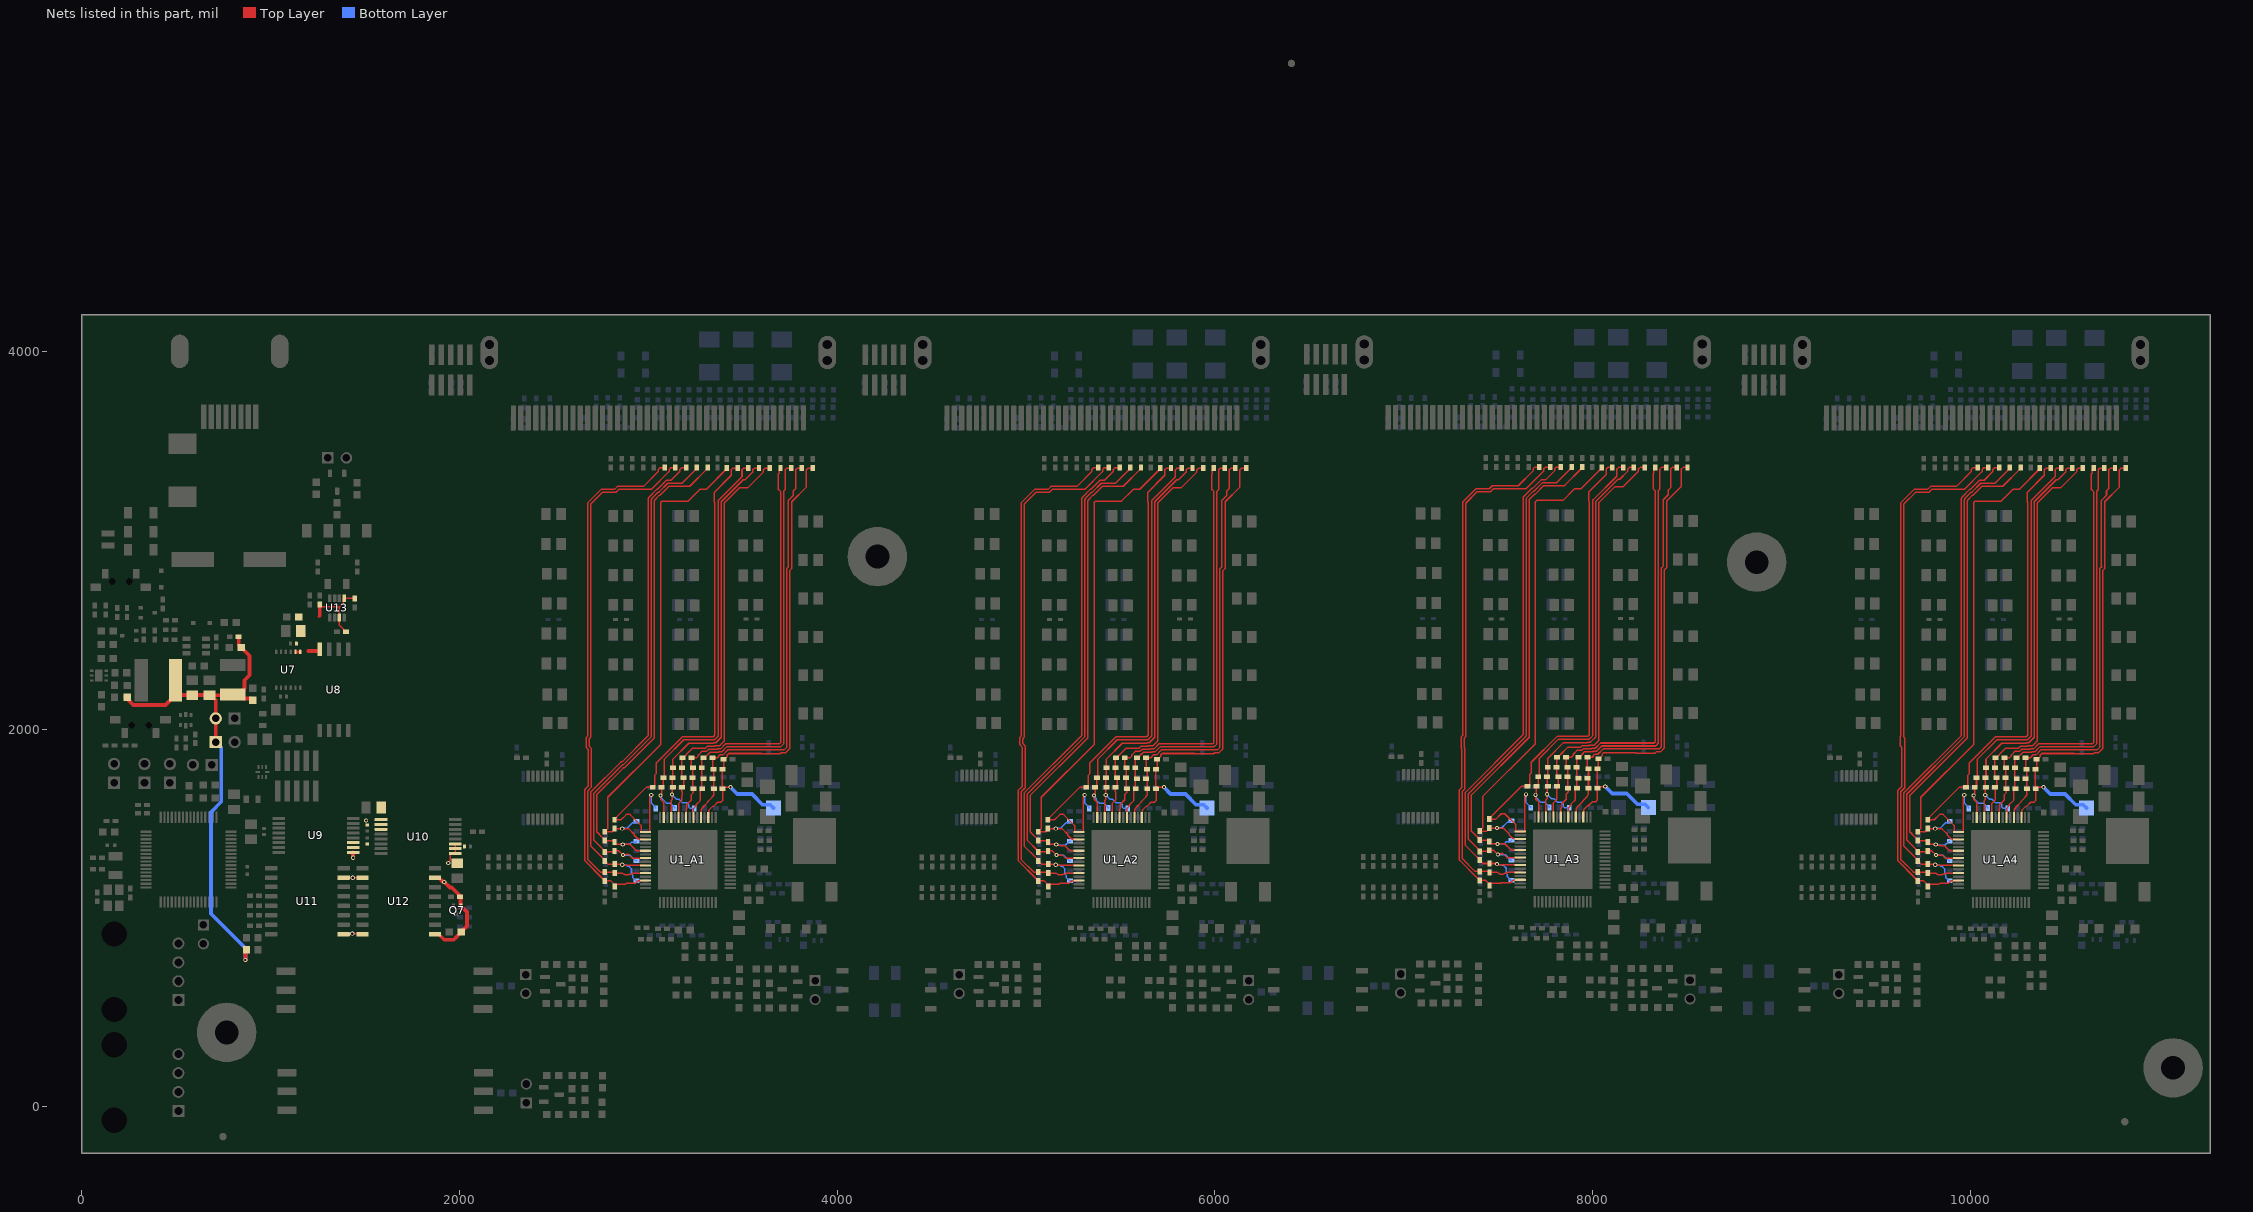
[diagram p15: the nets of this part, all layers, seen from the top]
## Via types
v1: diameter 22.01, hole 12.01, Top Layer to Bottom Layer, tented both sides, 2656 vias
v2: diameter 19.68, hole 7.87, Top Layer to Bottom Layer, tented both sides, 144 vias
v3: diameter 92.52, hole 49.21, Top Layer to Bottom Layer, 4 vias
v4: diameter 19.68, hole 7.87, Top Layer to Bottom Layer, 2 vias

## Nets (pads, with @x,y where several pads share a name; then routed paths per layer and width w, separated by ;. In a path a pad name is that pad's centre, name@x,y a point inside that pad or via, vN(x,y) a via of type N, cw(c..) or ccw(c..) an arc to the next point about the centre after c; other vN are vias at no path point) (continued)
VC5_A1: C98_A1.2 C101_A1.1 R126_A1.2 U1_A1.30 | length 2792.9
  Top Layer w8: U1_A1.30@2985.06,1198.69 2983.15,1196.78 2946.16,1196.78 2932.19,1182.81 2884.36,1182.81 2881,1179.46 2829.6,1179.46 2826.12,1175.98 2826.12,1171.65 2823.95,1173.81 2801.95,1195.81 C98_A1.2@2769.59,1195.81 2769.59,1199.75 2761.78,1207.56 2758.83,1207.56 2662.88,1303.51 2662.88,1679.46 2680.98,1697.56 2680.98,1892.74 2671.13,1902.59 2671.13,1955.06 2680.21,1964.14 2680.21,3199.51 2749.85,3269.15 2820.86,3269.15 2836.73,3285.02 2974.4,3285.02 3052.73,3363.35 3052.73,3374.64 3062.1,3384.01 R126_A1.2@3085.91,3384.01
VC5_A2: C98_A2.2 C101_A2.1 R126_A2.2 U1_A2.30 | length 2797
  Top Layer w8: U1_A2.30@5280.07,1198.69 5278.17,1196.78 5241.18,1196.78 5227.21,1182.81 5179.38,1182.81 5176.02,1179.46 5124.61,1179.46 5121.14,1175.98 5121.14,1171.65 5118.97,1173.81 5096.97,1195.81 C98_A2.2@5064.61,1195.81 5064.61,1199.75 5056.8,1207.56 5053.84,1207.56 4957.9,1303.51 4957.9,1674.44 4974.29,1690.83 4980.94,1697.49 4980.94,1902.95 4966.15,1917.75 4966.15,1955.06 4975.23,1964.14 4975.23,3199.51 5044.87,3269.15 5115.87,3269.15 5131.75,3285.02 5269.42,3285.02 5347.75,3363.35 5347.75,3374.64 5357.12,3384.01 R126_A2.2@5380.93,3384.01
VC5_A3: C98_A3.2 C101_A3.1 R126_A3.2 U1_A3.30 | length 2788.2
  Top Layer w8: U1_A3.30@7616.67,1201.9 7614.77,1199.99 7577.77,1199.99 7563.81,1186.02 7515.97,1186.02 7512.62,1182.67 7461.21,1182.67 7457.73,1179.19 7457.73,1174.85 7455.57,1177.02 7433.57,1199.02 C98_A3.2@7401.21,1199.02 7401.21,1202.96 7393.39,1210.77 7390.44,1210.77 7294.49,1306.72 7294.49,1677.65 7306.96,1690.11 7306.96,1892.74 7302.75,1896.95 7302.75,1958.27 7311.83,1967.35 7311.83,3202.71 7381.47,3272.35 7452.47,3272.35 7468.34,3288.23 7606.02,3288.23 7684.34,3366.55 7684.34,3377.85 7693.71,3387.22 R126_A3.2@7717.52,3387.22
VC5_A4: C98_A4.2 C101_A4.1 R126_A4.2 U1_A4.30 | length 2791.8
  Top Layer w8: U1_A4.30@9936.9,1198.69 9935,1196.78 9898,1196.78 9884.04,1182.81 9836.2,1182.81 9832.85,1179.46 9781.44,1179.46 9777.96,1175.98 9777.96,1171.65 9775.8,1173.81 9753.8,1195.81 C98_A4.2@9721.44,1195.81 9721.44,1199.75 9713.62,1207.56 9710.67,1207.56 9614.72,1303.51 9614.72,1674.44 9636.46,1696.17 9636.46,1902.95 9627.97,1911.44 9627.97,1960.06 9632.06,1964.14 9632.06,3199.51 9701.7,3269.15 9772.7,3269.15 9788.57,3285.02 9926.25,3285.02 10004.57,3363.35 10004.57,3374.64 10013.94,3384.01 R126_A4.2@10037.75,3384.01
VC6_A1: C88_A1.2 C98_A1.1 R114_A1.2 U1_A1.28 | length 2781.5
  Top Layer w8: U1_A1.28@2985.06,1238.06 2984.91,1237.91 2917.08,1237.91 2911.63,1232.46 2899.48,1232.46 2896.04,1229.02 2877.09,1229.02 2873.65,1232.46 2869.18,1232.46 2863.73,1237.91 C88_A1.2@2821.79,1237.91 ; R114_A1.2@3142.78,3384.01 3118.97,3384.01 3109.6,3374.64 3109.6,3363.35 3015.4,3269.15 2843.3,3269.15 2827.43,3253.27 2756.43,3253.27 2696.09,3192.93 2696.09,1957.57 2687.01,1948.49 2687.01,1909.17 2696.86,1899.32 2696.86,1690.99 2678.76,1672.89 2678.76,1310.08 2745.78,1243.06 C98_A1.1@2769.59,1243.06 C88_A1.2@2816.64,1243.06 ; C88_A1.2@2816.64,1243.06 C88_A1.2@2821.79,1237.91 ; C88_A1.2@2816.64,1243.06 C88_A1.2@2821.79,1237.91
VC6_A2: C88_A2.2 C98_A2.1 R114_A2.2 U1_A2.28 | length 2778.4
  Top Layer w8: U1_A2.28@5280.07,1238.06 5279.93,1237.91 5212.1,1237.91 5206.65,1232.46 5194.5,1232.46 5191.06,1229.02 5172.11,1229.02 5168.67,1232.46 5164.2,1232.46 5158.75,1237.91 C88_A2.2@5116.8,1237.91 5111.66,1243.06 C98_A2.1@5064.61,1243.06 5040.8,1243.06 4973.77,1310.08 4973.77,1667.86 4990.16,1684.25 4996.82,1690.91 4996.82,1909.53 4982.02,1924.32 4982.02,1948.49 4991.1,1957.57 4991.1,3192.93 5051.44,3253.27 5122.45,3253.27 5138.32,3269.15 5310.41,3269.15 5404.61,3363.35 5404.61,3374.64 5413.98,3384.01 R114_A2.2@5437.8,3384.01
VC6_A3: C88_A3.2 C98_A3.1 R114_A3.2 U1_A3.28 | length 2776.9
  Top Layer w8: U1_A3.28@7616.67,1241.27 7616.52,1241.12 7548.69,1241.12 7543.24,1235.67 7531.09,1235.67 7527.66,1232.23 7508.7,1232.23 7505.26,1235.67 7500.79,1235.67 7495.34,1241.12 C88_A3.2@7453.4,1241.12 ; R114_A3.2@7774.39,3387.22 7750.58,3387.22 7741.21,3377.85 7741.21,3366.55 7647.01,3272.35 7474.92,3272.35 7459.04,3256.48 7388.04,3256.48 7327.7,3196.14 7327.7,1960.78 7318.62,1951.7 7318.62,1903.53 7322.83,1899.32 7322.83,1683.54 7310.37,1671.07 7310.37,1313.29 7377.39,1246.27 C98_A3.1@7401.21,1246.27 C88_A3.2@7448.25,1246.27 ; C88_A3.2@7448.25,1246.27 C88_A3.2@7453.4,1241.12 ; C88_A3.2@7448.25,1246.27 C88_A3.2@7453.4,1241.12
VC6_A4: C88_A4.2 C98_A4.1 R114_A4.2 U1_A4.28 | length 2769.8
  Top Layer w8: U1_A4.28@9936.9,1238.06 9936.75,1237.91 9868.92,1237.91 9863.47,1232.46 9851.32,1232.46 9847.89,1229.02 9828.93,1229.02 9825.49,1232.46 9821.02,1232.46 9815.57,1237.91 C88_A4.2@9773.63,1237.91 9768.48,1243.06 C98_A4.1@9721.44,1243.06 9697.62,1243.06 9630.6,1310.08 9630.6,1667.86 9652.33,1689.6 9652.33,1953.17 9647.93,1957.57 9647.93,3192.93 9708.27,3253.27 9779.27,3253.27 9795.15,3269.15 9967.24,3269.15 10061.44,3363.35 10061.44,3374.64 10070.81,3384.01 R114_A4.2@10094.62,3384.01
VC7_A1: C81_A1.2 C88_A1.1 C96_A1.1 R104_A1.2 U1_A1.26 | length 2718.7
  Top Layer w8: U1_A1.26@2985.06,1277.43 2984.27,1278.22 2865.19,1278.22 v1(2861.72,1281.69) 2858.25,1285.15 C88_A1.1@2821.79,1285.15 2787.26,1285.15 2781.59,1290.82 2777.66,1290.82 2769.85,1298.63 C81_A1.2@2769.85,1302.57 2769.85,1306.51 2754.16,1322.19 2753.12,1322.19 2694.63,1380.68 2694.63,1666.31 2854.78,1826.46 2859.81,1826.46 2999.93,1966.59 2999.93,3220.93 3001.79,3222.79 3001.79,3226.76 3045.94,3270.91 3049.9,3270.91 3096.48,3317.48 3120.6,3317.48 3166.46,3363.35 3166.46,3374.64 3175.84,3384.01 R104_A1.2@3199.65,3384.01
  Bottom Layer w8: v1(2861.72,1281.69) 2864.4,1279.01 2883.57,1279.01 2887.8,1274.78 2896.04,1274.78 2910.85,1259.97 2910.85,1232.65 2916.71,1226.79 2916.71,1214.61 2934.54,1196.78 C96_A1.1@2938.47,1196.78
VC7_A2: C81_A2.2 C88_A2.1 C96_A2.1 R104_A2.2 U1_A2.26 | length 2715.8
  Top Layer w8: U1_A2.26@5280.07,1277.43 5279.29,1278.22 5160.2,1278.22 v1(5156.73,1281.69) 5153.26,1285.15 C88_A2.1@5116.8,1285.15 5082.28,1285.15 5076.61,1290.82 5072.67,1290.82 5064.86,1298.63 C81_A2.2@5064.86,1302.57 5064.86,1306.51 5049.18,1322.19 5048.13,1322.19 4989.65,1380.68 4989.65,1661.29 5294.94,1966.59 5294.94,3220.93 5296.8,3222.79 5296.8,3226.76 5340.95,3270.91 5344.92,3270.91 5391.49,3317.48 5415.62,3317.48 5461.48,3363.35 5461.48,3374.64 5470.85,3384.01 R104_A2.2@5494.66,3384.01
  Bottom Layer w8: v1(5156.73,1281.69) 5159.41,1279.01 5178.59,1279.01 5182.81,1274.78 5191.06,1274.78 5205.87,1259.97 5205.87,1232.65 5211.73,1226.79 5211.73,1214.61 5229.55,1196.78 C96_A2.1@5233.49,1196.78
VC7_A3: C81_A3.2 C88_A3.1 C96_A3.1 R104_A3.2 U1_A3.26 | length 2715.8
  Top Layer w8: U1_A3.26@7616.67,1280.64 7615.88,1281.42 7496.8,1281.42 v1(7493.33,1284.89) 7489.86,1288.36 C88_A3.1@7453.4,1288.36 7418.87,1288.36 7413.21,1294.03 7409.27,1294.03 7401.46,1301.84 C81_A3.2@7401.46,1305.78 7401.46,1309.72 7385.77,1325.4 7384.73,1325.4 7326.24,1383.89 7326.24,1664.5 7631.54,1969.79 7631.54,3224.14 7633.4,3226 7633.4,3229.97 7677.55,3274.12 7681.52,3274.12 7728.09,3320.69 7752.21,3320.69 7798.08,3366.55 7798.08,3377.85 7807.45,3387.22 R104_A3.2@7831.26,3387.22
  Bottom Layer w8: v1(7493.33,1284.89) 7496.01,1282.21 7515.18,1282.21 7519.41,1277.99 7527.66,1277.99 7542.46,1263.18 7542.46,1235.86 7548.33,1230 7548.33,1217.81 7566.15,1199.99 C96_A3.1@7570.09,1199.99
VC7_A4: C81_A4.2 C88_A4.1 C96_A4.1 R104_A4.2 U1_A4.26 | length 2715.8
  Top Layer w8: U1_A4.26@9936.9,1277.43 9936.11,1278.22 9817.03,1278.22 v1(9813.56,1281.69) 9810.09,1285.15 C88_A4.1@9773.63,1285.15 9739.1,1285.15 9733.44,1290.82 9729.5,1290.82 9721.69,1298.63 C81_A4.2@9721.69,1302.57 9721.69,1306.51 9706,1322.19 9704.96,1322.19 9646.47,1380.68 9646.47,1661.29 9951.77,1966.59 9951.77,3220.93 9953.63,3222.79 9953.63,3226.76 9997.78,3270.91 10001.75,3270.91 10048.32,3317.48 10072.44,3317.48 10118.31,3363.35 10118.31,3374.64 10127.68,3384.01 R104_A4.2@10151.49,3384.01
  Bottom Layer w8: v1(9813.56,1281.69) 9816.24,1279.01 9835.41,1279.01 9839.64,1274.78 9847.89,1274.78 9862.69,1259.97 9862.69,1232.65 9868.56,1226.79 9868.56,1214.61 9886.38,1196.78 C96_A4.1@9890.32,1196.78
VC8_A1: C71_A1.2 C81_A1.1 C89_A1.1 R100_A1.2 U1_A1.24 | length 2657.2
  Top Layer w8: U1_A1.24@2985.06,1316.8 2914.34,1316.8 2893.03,1338.11 2885.03,1338.11 2882.44,1335.53 2868.7,1335.53 v1(2866.02,1332.84) 2843.59,1355.28 2820.95,1355.28 C71_A1.2@2820.87,1355.36 2815.33,1349.81 C81_A1.1@2769.85,1349.81 2769.85,1353.75 2710.5,1413.09 2710.5,1659.74 2861.36,1810.59 2866.38,1810.59 3016.19,1960.4 3016.19,3214.75 3017.66,3216.22 3017.66,3220.18 3052.51,3255.03 3056.48,3255.03 3103.05,3301.61 3178.05,3301.61 3256.52,3380.08 R100_A1.2@3256.52,3384.01
  Bottom Layer w8: v1(2866.02,1332.84) 2867.63,1331.23 2905.28,1331.23 2934.54,1301.98 C89_A1.1@2938.47,1301.98
VC8_A2: C71_A2.2 C81_A2.1 C89_A2.1 R100_A2.2 U1_A2.24 | length 2657.8
  Top Layer w8: U1_A2.24@5280.07,1316.8 5209.35,1316.8 5193.31,1332.84 v1(5161.04,1332.84) 5138.6,1355.28 5115.97,1355.28 C71_A2.2@5115.89,1355.36 ; R100_A2.2@5551.53,3384.01 5551.53,3380.08 5473.06,3301.61 5398.07,3301.61 5351.5,3255.03 5347.53,3255.03 5312.68,3220.18 5312.68,3216.22 5311.21,3214.75 5311.21,1960.4 5005.52,1654.71 5005.52,1413.09 5064.86,1353.75 C81_A2.1@5064.86,1349.81 C71_A2.2@5110.35,1349.81 ; C71_A2.2@5110.35,1349.81 C71_A2.2@5115.89,1355.36 ; C71_A2.2@5110.35,1349.81 C71_A2.2@5115.89,1355.36
  Bottom Layer w8: v1(5161.04,1332.84) 5162.65,1331.23 5200.3,1331.23 5229.55,1301.98 C89_A2.1@5233.49,1301.98
VC8_A3: C71_A3.2 C81_A3.1 C89_A3.1 R100_A3.2 U1_A3.24 | length 2662.1
  Top Layer w8: U1_A3.24@7616.67,1320.01 7545.95,1320.01 7524.64,1341.32 7516.64,1341.32 7514.05,1338.73 7500.31,1338.73 v1(7497.63,1336.05) 7475.2,1358.49 7452.56,1358.49 C71_A3.2@7452.48,1358.56 ; R100_A3.2@7888.13,3387.22 7888.13,3383.28 7809.66,3304.82 7734.67,3304.82 7688.09,3258.24 7684.13,3258.24 7649.27,3223.39 7649.27,3219.42 7647.81,3217.96 7647.81,1963.61 7342.12,1657.92 7342.12,1416.3 7401.46,1356.96 C81_A3.1@7401.46,1353.02 C71_A3.2@7446.94,1353.02 ; C71_A3.2@7446.94,1353.02 C71_A3.2@7452.48,1358.56 ; C71_A3.2@7446.94,1353.02 C71_A3.2@7452.48,1358.56
  Bottom Layer w8: v1(7497.63,1336.05) 7499.25,1334.44 7536.89,1334.44 7566.15,1305.18 C89_A3.1@7570.09,1305.18
VC8_A4: C71_A4.2 C81_A4.1 C89_A4.1 R100_A4.2 U1_A4.24 | length 2657.8
  Top Layer w8: U1_A4.24@9936.9,1316.8 9866.18,1316.8 9850.13,1332.84 v1(9817.86,1332.84) 9795.43,1355.28 9772.79,1355.28 C71_A4.2@9772.71,1355.36 ; R100_A4.2@10208.36,3384.01 10208.36,3380.08 10129.89,3301.61 10054.9,3301.61 10008.32,3255.03 10004.36,3255.03 9969.5,3220.18 9969.5,3216.22 9968.04,3214.75 9968.04,1960.4 9662.35,1654.71 9662.35,1413.09 9721.69,1353.75 C81_A4.1@9721.69,1349.81 C71_A4.2@9767.17,1349.81 ; C71_A4.2@9767.17,1349.81 C71_A4.2@9772.71,1355.36 ; C71_A4.2@9767.17,1349.81 C71_A4.2@9772.71,1355.36
  Bottom Layer w8: v1(9817.86,1332.84) 9819.48,1331.23 9857.12,1331.23 9886.38,1301.98 C89_A4.1@9890.32,1301.98
VC9_A1: C63_A1.2 C71_A1.1 C84_A1.1 R90_A1.2 U1_A1.22 | length 2627.6
  Top Layer w8: C71_A1.1@2820.87,1402.6 2819.02,1404.45 2814.14,1409.33 C63_A1.2@2770.09,1409.33 2770.09,1413.26 2754.41,1428.95 2753.36,1428.95 2726.38,1455.94 2726.38,1653.16 2867.93,1794.72 2872.96,1794.72 3032.07,1953.83 3032.07,3208.17 3033.54,3209.64 3033.54,3213.61 3059.09,3239.16 3063.06,3239.16 3109.63,3285.73 3219.04,3285.73 3313.38,3380.08 R90_A1.2@3313.38,3384.01 ; C71_A1.1@2821.61,1402.6 2821.61,1397.92 2828.68,1390.85 2861.95,1390.85 v1(2864.4,1388.41) ; v1@2864.4,1389.66 2864.83,1390.1 2903.02,1390.1 2936.95,1356.17 U1_A1.22@2985.06,1356.17
  Bottom Layer w8: v1(2864.4,1388.41) 2866.09,1390.1 2900.98,1390.1 2904.67,1393.79 ; 2904.71,1393.79 2910.73,1399.8 2931.1,1399.8 C84_A1.1@2938.47,1407.17
VC9_A2: C63_A2.2 C71_A2.1 C84_A2.1 R90_A2.2 U1_A2.22 | length 2652
  Top Layer w8: C71_A2.1@5116.63,1402.6 5116.63,1397.92 C71_A2.1@5123.7,1390.85 ; v1(5159.41,1388.41) 5156.97,1390.85 C71_A2.1@5123.7,1390.85 ; v1@5159.41,1389.66 5163.35,1385.73 5176.39,1385.73 5180.98,1381.14 5206.99,1381.14 5231.96,1356.17 U1_A2.22@5280.07,1356.17 ; R90_A2.2@5608.4,3384.01 5608.4,3380.08 5514.06,3285.73 5404.64,3285.73 5358.07,3239.16 5354.11,3239.16 5328.55,3213.61 5328.55,3209.64 5327.08,3208.17 5327.08,1953.83 5021.39,1648.14 5021.39,1455.94 5048.38,1428.95 5049.43,1428.95 5065.11,1413.26 C63_A2.2@5065.11,1409.33 C71_A2.1@5109.16,1409.33 ; C71_A2.1@5109.16,1409.33 C71_A2.1@5115.89,1402.6 ; C71_A2.1@5109.16,1409.33 5114.03,1404.45 C71_A2.1@5115.89,1402.6 ; C71_A2.1@5115.89,1402.6 5115.89,1398.66 C71_A2.1@5123.7,1390.85
  Bottom Layer w8: v1(5159.41,1388.41) 5163.2,1388.41 5167.01,1384.6 5206.98,1384.6 5229.55,1407.17 C84_A2.1@5233.49,1407.17
VC9_A3: C63_A3.2 C71_A3.1 C84_A3.1 R90_A3.2 U1_A3.22 | length 2634.2
  Top Layer w8: C71_A3.1@7453.23,1405.81 7453.23,1401.13 7460.29,1394.06 7493.56,1394.06 v1(7496.01,1391.62) ; v1@7496.01,1392.87 7496.44,1393.31 7534.63,1393.31 7568.56,1359.38 U1_A3.22@7616.67,1359.38 ; R90_A3.2@7945,3387.22 7945,3383.28 7850.65,3288.94 7741.24,3288.94 7694.67,3242.37 7690.7,3242.37 7665.15,3216.81 7665.15,3212.85 7663.68,3211.38 7663.68,1957.04 7357.99,1651.35 7357.99,1459.14 7384.98,1432.16 7386.02,1432.16 7401.71,1416.47 C63_A3.2@7401.71,1412.54 C71_A3.1@7445.76,1412.54 ; C71_A3.1@7445.76,1412.54 C71_A3.1@7452.48,1405.81 7450.63,1407.66 C71_A3.1@7445.76,1412.54
  Bottom Layer w8: v1(7496.01,1391.62) 7497.7,1393.31 7532.59,1393.31 7536.28,1397 ; 7536.33,1397 7542.34,1403.01 7562.72,1403.01 C84_A3.1@7570.09,1410.38
VC9_A4: C63_A4.2 C71_A4.1 C84_A4.1 R90_A4.2 U1_A4.22 | length 2652
  Top Layer w8: C71_A4.1@9773.46,1402.6 9773.46,1397.92 C71_A4.1@9780.52,1390.85 ; v1(9816.24,1388.41) 9813.79,1390.85 C71_A4.1@9780.52,1390.85 ; v1@9816.24,1389.66 9820.18,1385.73 9831.9,1385.73 9836.48,1381.14 9863.81,1381.14 9888.79,1356.17 U1_A4.22@9936.9,1356.17 ; R90_A4.2@10265.23,3384.01 10265.23,3380.08 10170.88,3285.73 10061.47,3285.73 10014.9,3239.16 10010.93,3239.16 9985.38,3213.61 9985.38,3209.64 9983.91,3208.17 9983.91,1953.83 9678.22,1648.14 9678.22,1455.94 9705.21,1428.95 9706.25,1428.95 9721.94,1413.26 C63_A4.2@9721.94,1409.33 C71_A4.1@9765.99,1409.33 ; C71_A4.1@9765.99,1409.33 C71_A4.1@9772.71,1402.6 ; C71_A4.1@9765.99,1409.33 9770.86,1404.45 C71_A4.1@9772.71,1402.6 ; C71_A4.1@9772.71,1402.6 9772.71,1398.66 C71_A4.1@9780.52,1390.85
  Bottom Layer w8: v1(9816.24,1388.41) 9820.03,1388.41 9823.84,1384.6 9863.81,1384.6 9886.38,1407.17 C84_A4.1@9890.32,1407.17
VC10_A1: C58_A1.2 C63_A1.1 C79_A1.1 R83_A1.2 U1_A1.19 | length 2638
  Top Layer w8: U1_A1.19@2985.06,1415.22 2983.15,1417.13 2950.15,1417.13 2948.34,1418.94 2944.35,1418.94 2925.78,1437.51 2925.78,1442.85 2897.53,1471.11 2864.87,1471.11 2863.18,1472.8 v1(2861.72,1472.8) C58_A1.2@2820.86,1472.8 2820.86,1468.86 2808.57,1456.57 C63_A1.1@2770.09,1456.57 2770.09,1460.51 2777.91,1468.32 2780.75,1468.32 2785.43,1473.01 2785.43,1639.27 3065.28,1919.12 3065.28,3200.46 3072.24,3207.41 3210.75,3207.41 3273.2,3269.86 3307.24,3269.86 3415.33,3377.95 R83_A1.2@3415.33,3381.89
  Bottom Layer w8: v1@2863.18,1472.8 2864.65,1474.27 2886.18,1474.27 2911.23,1499.33 2911.29,1499.33 2916.52,1504.55 2930.66,1504.55 C79_A1.1@2938.47,1512.36
VC10_A2: C58_A2.2 C63_A2.1 C79_A2.1 R83_A2.2 U1_A2.19 | length 2638
  Top Layer w8: U1_A2.19@5280.07,1415.22 5278.17,1417.13 5245.16,1417.13 5243.35,1418.94 5239.37,1418.94 5220.8,1437.51 5220.8,1442.85 5192.54,1471.11 5159.89,1471.11 5158.19,1472.8 v1(5156.73,1472.8) C58_A2.2@5115.88,1472.8 5115.88,1468.86 5103.59,1456.57 C63_A2.1@5065.11,1456.57 5065.11,1460.51 5072.92,1468.32 5075.76,1468.32 5080.45,1473.01 5080.45,1639.27 5360.3,1919.12 5360.3,3200.46 5367.26,3207.41 5505.77,3207.41 5568.21,3269.86 5602.25,3269.86 5710.34,3377.95 R83_A2.2@5710.34,3381.89
  Bottom Layer w8: v1@5158.19,1472.8 5159.67,1474.27 5181.2,1474.27 5206.25,1499.33 5206.3,1499.33 5211.53,1504.55 5225.68,1504.55 C79_A2.1@5233.49,1512.36
VC10_A3: C58_A3.2 C63_A3.1 C79_A3.1 R83_A3.2 U1_A3.19 | length 2638
  Top Layer w8: U1_A3.19@7616.67,1418.43 7614.77,1420.34 7581.76,1420.34 7579.95,1422.15 7575.96,1422.15 7557.4,1440.72 7557.4,1446.06 7529.14,1474.31 7496.49,1474.31 7494.79,1476.01 v1(7493.33,1476.01) C58_A3.2@7452.48,1476.01 7452.48,1472.07 7440.18,1459.78 C63_A3.1@7401.71,1459.78 7401.71,1463.72 7409.52,1471.53 7412.36,1471.53 7417.05,1476.21 7417.05,1642.48 7696.9,1922.33 7696.9,3203.66 7703.85,3210.62 7842.36,3210.62 7904.81,3273.07 7938.85,3273.07 8046.94,3381.16 R83_A3.2@8046.94,3385.1
  Bottom Layer w8: v1@7494.79,1476.01 7496.26,1477.48 7517.79,1477.48 7542.85,1502.53 7542.9,1502.53 7548.13,1507.76 7562.28,1507.76 C79_A3.1@7570.09,1515.57
VC10_A4: C58_A4.2 C63_A4.1 C79_A4.1 R83_A4.2 U1_A4.19 | length 2638
  Top Layer w8: U1_A4.19@9936.9,1415.22 9935,1417.13 9901.99,1417.13 9900.18,1418.94 9896.19,1418.94 9877.62,1437.51 9877.62,1442.85 9849.37,1471.11 9816.72,1471.11 9815.02,1472.8 v1(9813.56,1472.8) C58_A4.2@9772.71,1472.8 9772.71,1468.86 9760.41,1456.57 C63_A4.1@9721.94,1456.57 9721.94,1460.51 9729.75,1468.32 9732.59,1468.32 9737.28,1473.01 9737.28,1639.27 10017.13,1919.12 10017.13,3200.46 10024.08,3207.41 10162.59,3207.41 10225.04,3269.86 10259.08,3269.86 10367.17,3377.95 R83_A4.2@10367.17,3381.89
  Bottom Layer w8: v1@9815.02,1472.8 9816.49,1474.27 9838.02,1474.27 9863.08,1499.33 9863.13,1499.33 9868.36,1504.55 9882.51,1504.55 C79_A4.1@9890.32,1512.36
VC11_A1: C49_A1.2 C58_A1.1 C75_A1.1 R75_A1.2 U1_A1.17 | length 2801.5
  Top Layer w8: v1(3015.04,1651.11) 3015.04,1647.32 3008.64,1640.91 3008.64,1456.5 3006.73,1454.59 U1_A1.17@2985.06,1454.59 2963.38,1454.59 2961.48,1456.5 2961.48,1490.17 2903.18,1548.47 2884.22,1548.47 2855.8,1520.04 C58_A1.1@2820.86,1520.04 2820.86,1523.98 2989.92,1693.04 C49_A1.2@3023.44,1693.04 3027.11,1693.04 3034.92,1700.85 3034.92,1756.24 3042.87,1764.19 3042.87,1821.29 3181.33,1959.75 3343.93,1959.75 3348.88,1964.69 3350.89,1966.7 3350.89,3199.79 3348.6,3202.08 3348.6,3253.2 3439.01,3343.61 3439.01,3372.52 3448.39,3381.89 R75_A1.2@3472.2,3381.89
  Bottom Layer w8: v1(3015.04,1651.11) 3015.04,1608.59 3039.3,1584.33 C75_A1.1@3039.3,1580.39
VC11_A2: C49_A2.2 C58_A2.1 C75_A2.1 R75_A2.2 U1_A2.17 | length 2801.5
  Top Layer w8: v1(5310.06,1651.11) 5310.06,1647.32 5303.65,1640.91 5303.65,1456.5 5301.75,1454.59 U1_A2.17@5280.07,1454.59 5258.4,1454.59 5256.5,1456.5 5256.5,1490.17 5198.19,1548.47 5179.24,1548.47 5150.82,1520.04 C58_A2.1@5115.88,1520.04 5115.88,1523.98 5284.93,1693.04 C49_A2.2@5318.46,1693.04 5322.13,1693.04 5329.94,1700.85 5329.94,1756.24 5337.89,1764.19 5337.89,1821.29 5476.35,1959.75 5638.95,1959.75 5643.9,1964.69 5645.91,1966.7 5645.91,3199.79 5643.61,3202.08 5643.61,3253.2 5734.03,3343.61 5734.03,3372.52 5743.4,3381.89 R75_A2.2@5767.21,3381.89
  Bottom Layer w8: v1(5310.06,1651.11) 5310.06,1608.59 5334.32,1584.33 C75_A2.1@5334.32,1580.39
VC11_A3: C49_A3.2 C58_A3.1 C75_A3.1 R75_A3.2 U1_A3.17 | length 2801.5
  Top Layer w8: v1(7646.66,1654.32) 7646.66,1650.53 7640.25,1644.12 7640.25,1459.71 7638.34,1457.8 U1_A3.17@7616.67,1457.8 7595,1457.8 7593.09,1459.71 7593.09,1493.37 7534.79,1551.68 7515.84,1551.68 7487.41,1523.25 C58_A3.1@7452.48,1523.25 7452.48,1527.19 7621.53,1696.25 C49_A3.2@7655.05,1696.25 7658.72,1696.25 7666.53,1704.06 7666.53,1759.45 7674.48,1767.4 7674.48,1824.49 7812.95,1962.96 7975.55,1962.96 7980.49,1967.9 7982.5,1969.91 7982.5,3202.99 7980.21,3205.29 7980.21,3256.4 8070.63,3346.82 8070.63,3375.73 8080,3385.1 R75_A3.2@8103.81,3385.1
  Bottom Layer w8: v1(7646.66,1654.32) 7646.66,1611.8 7670.92,1587.54 C75_A3.1@7670.92,1583.6
VC11_A4: C49_A4.2 C58_A4.1 C75_A4.1 R75_A4.2 U1_A4.17 | length 2801.5
  Top Layer w8: v1(9966.89,1651.11) 9966.89,1647.32 9960.48,1640.91 9960.48,1456.5 9958.57,1454.59 U1_A4.17@9936.9,1454.59 9915.23,1454.59 9913.32,1456.5 9913.32,1490.17 9855.02,1548.47 9836.07,1548.47 9807.64,1520.05 C58_A4.1@9772.71,1520.05 9772.71,1523.98 9941.76,1693.04 C49_A4.2@9975.28,1693.04 9978.95,1693.04 9986.76,1700.85 9986.76,1756.24 9994.71,1764.19 9994.71,1821.29 10133.18,1959.75 10295.78,1959.75 10300.72,1964.69 10302.73,1966.7 10302.73,3199.79 10300.44,3202.08 10300.44,3253.2 10390.86,3343.61 10390.86,3372.52 10400.23,3381.89 R75_A4.2@10424.04,3381.89
  Bottom Layer w8: v1(9966.89,1651.11) 9966.89,1608.59 9991.15,1584.33 C75_A4.1@9991.15,1580.39
VC12_A1: C45_A1.2 C49_A1.1 C67_A1.1 R65_A1.2 U1_A1.15 | length 2260.1
  Top Layer w8: v1(3064.83,1648.57) 3064.97,1648.43 3064.97,1628.64 3081.51,1612.09 U1_A1.15@3081.51,1531.37 ; v1@3070.42,1656.11 3070.42,1692.77 C49_A1.1@3070.69,1693.04 3072.23,1693.04 3080.04,1700.85 C45_A1.2@3080.04,1743.6 3085.2,1748.75 3085.2,1841.16 3187.91,1943.87 3350.51,1943.87 3369.75,1963.11 3369.75,3209.87 3495.88,3336.01 3495.88,3372.52 3505.25,3381.89 R65_A1.2@3529.06,3381.89
  Bottom Layer w8: v1(3064.83,1648.57) 3064.97,1648.43 3064.97,1639.41 3096.15,1608.22 3116.42,1608.22 3139.48,1585.16 C67_A1.1@3139.48,1581.22
VC12_A2: C45_A2.2 C49_A2.1 C67_A2.1 R65_A2.2 U1_A2.15 | length 2262.6
  Top Layer w8: v1(5359.84,1648.57) 5359.98,1648.43 5359.98,1628.64 5376.53,1612.09 U1_A2.15@5376.53,1531.37 ; v1@5365.43,1656.11 5365.43,1692.77 C49_A2.1@5365.7,1693.04 5367.25,1693.04 5375.06,1700.85 C45_A2.2@5375.06,1743.6 5380.21,1748.75 5380.21,1841.16 5482.93,1943.87 5645.53,1943.87 5664.76,1963.11 5664.76,3209.87 5790.9,3336.01 5790.9,3372.52 5800.27,3381.89 R65_A2.2@5824.08,3381.89
  Bottom Layer w8: v1(5359.84,1648.57) 5359.84,1644.78 5370.81,1633.81 5370.81,1624.38 5386.97,1608.22 5411.43,1608.22 5434.5,1585.16 C67_A2.1@5434.5,1581.22
VC12_A3: C45_A3.2 C49_A3.1 C67_A3.1 R65_A3.2 U1_A3.15 | length 2261
  Top Layer w8: v1(7696.44,1651.77) 7698.75,1649.47 7698.75,1628.77 7713.13,1614.39 U1_A3.15@7713.13,1534.57 ; v1@7702.03,1659.32 7702.03,1695.98 C49_A3.1@7702.3,1696.25 7703.84,1696.25 7711.66,1704.06 C45_A3.2@7711.66,1746.8 7716.81,1751.96 7716.81,1844.37 7819.52,1947.08 7982.12,1947.08 8001.36,1966.32 8001.36,3213.08 8127.49,3339.21 8127.49,3375.73 8136.87,3385.1 R65_A3.2@8160.68,3385.1
  Bottom Layer w8: v1(7696.44,1651.77) 7699.12,1649.09 7699.12,1638.58 7726.28,1611.43 7748.03,1611.43 7771.09,1588.36 C67_A3.1@7771.09,1584.43
VC12_A4: C45_A4.2 C49_A4.1 C67_A4.1 R65_A4.2 U1_A4.15 | length 2263.3
  Top Layer w8: v1(10016.67,1648.57) 10016.81,1648.43 10016.81,1628.64 10033.36,1612.09 U1_A4.15@10033.36,1531.37 ; v1@10022.26,1656.11 10022.26,1692.77 C49_A4.1@10022.53,1693.04 10024.07,1693.04 10031.89,1700.85 C45_A4.2@10031.89,1743.6 10037.04,1748.75 10037.04,1841.16 10139.75,1943.87 10302.35,1943.87 10321.59,1963.11 10321.59,3209.87 10447.72,3336.01 10447.72,3372.52 10457.1,3381.89 R65_A4.2@10480.91,3381.89
  Bottom Layer w8: v1(10016.67,1648.57) 10019.35,1645.89 10019.35,1631.34 10042.47,1608.22 10068.26,1608.22 10091.32,1585.16 C67_A4.1@10091.32,1581.22
VC13_A1: C37_A1.2 C45_A1.1 C61_A1.1 R61_A1.2 R199_A1.2 U1_A1.13 | length 2313.2
  Top Layer w8: U1_A1.13@3120.88,1531.37 3120.88,1621.97 3125.71,1626.79 v1(3125.71,1653.28) ; v1@3126.44,1651.72 C37_A1.2@3126.44,1688.52 ; R61_A1.2@3585.93,3381.89 3562.12,3381.89 3552.75,3372.52 3552.75,3361.22 3511.27,3319.75 3502.07,3319.75 3385.62,3203.3 3385.62,1956.54 3357.09,1928 3344.96,1928 3342.29,1925.32 3214.06,1925.32 3130.34,1841.59 R199_A1.2@3130.34,1795.9 3130.34,1746.64 C45_A1.1@3127.29,1743.6 3127.29,1696.71 C37_A1.2@3130.96,1693.04 ; C37_A1.2@3126.44,1688.52 C37_A1.2@3130.96,1693.04 ; C37_A1.2@3126.44,1688.52 C37_A1.2@3130.96,1693.04
  Bottom Layer w8: v1(3125.71,1653.28) 3125.71,1652.22 3149.34,1628.6 3161.73,1628.6 3181.34,1608.99 3206.3,1608.99 3213.39,1601.9 3213.39,1587.48 3220.47,1580.39 C61_A1.1@3244.28,1580.39
VC13_A2: C37_A2.2 C45_A2.1 C61_A2.1 R61_A2.2 R199_A2.2 U1_A2.13 | length 2304.1
  Top Layer w8: U1_A2.13@5415.9,1531.37 5415.9,1621.97 5421.46,1627.53 v1(5421.46,1651.49) ; v1@5420.85,1651.11 5421.46,1651.72 5421.46,1688.52 C37_A2.2@5425.98,1693.04 5422.3,1696.71 C45_A2.1@5422.3,1743.6 5425.35,1746.64 R199_A2.2@5425.35,1795.9 5425.35,1841.59 5509.08,1925.32 5637.3,1925.32 5639.98,1928 5652.1,1928 5680.64,1956.54 5680.64,3203.3 5797.09,3319.75 5806.29,3319.75 5847.77,3361.22 5847.77,3372.52 5857.14,3381.89 R61_A2.2@5880.95,3381.89
  Bottom Layer w8: v1(5421.46,1651.49) 5444.35,1628.6 5456.75,1628.6 5476.35,1608.99 5501.32,1608.99 5508.4,1601.9 5508.4,1587.48 5515.49,1580.39 C61_A2.1@5539.3,1580.39
VC13_A3: C37_A3.2 C45_A3.1 C61_A3.1 R61_A3.2 R199_A3.2 U1_A3.13 | length 2304.1
  Top Layer w8: U1_A3.13@7752.5,1534.57 7752.5,1625.18 7758.05,1630.73 v1(7758.05,1654.7) ; v1@7757.45,1654.32 7758.05,1654.93 7758.05,1691.72 C37_A3.2@7762.58,1696.25 7758.9,1699.92 C45_A3.1@7758.9,1746.8 7761.95,1749.85 R199_A3.2@7761.95,1799.11 7761.95,1844.8 7845.68,1928.53 7973.9,1928.53 7976.57,1931.21 7988.7,1931.21 8017.24,1959.75 8017.24,3206.51 8133.68,3322.95 8142.88,3322.95 8184.36,3364.43 8184.36,3375.73 8193.73,3385.1 R61_A3.2@8217.54,3385.1
  Bottom Layer w8: v1(7758.05,1654.7) 7780.95,1631.81 7793.34,1631.81 7812.95,1612.2 7837.91,1612.2 7845,1605.11 7845,1590.69 7852.09,1583.6 C61_A3.1@7875.9,1583.6
VC13_A4: C37_A4.2 C45_A4.1 C61_A4.1 R61_A4.2 R199_A4.2 U1_A4.13 | length 2304.3
  Top Layer w8: U1_A4.13@10072.73,1531.37 10072.73,1621.97 10078.28,1627.53 v1(10078.28,1651.49) ; v1@10077.67,1651.11 10078.28,1651.72 10078.28,1688.52 C37_A4.2@10082.81,1693.04 10079.13,1696.71 C45_A4.1@10079.13,1743.6 10082.18,1746.64 R199_A4.2@10082.18,1795.9 10082.18,1841.59 10165.91,1925.32 10294.13,1925.32 10296.8,1928 10308.93,1928 10337.47,1956.54 10337.47,3203.3 10453.91,3319.75 10463.11,3319.75 10504.59,3361.22 10504.59,3372.52 10513.96,3381.89 R61_A4.2@10537.77,3381.89
  Bottom Layer w8: v1(10078.28,1651.49) 10078.28,1651.15 10100.84,1628.6 10113.57,1628.6 10133.18,1608.99 10158.14,1608.99 10165.23,1601.9 10165.23,1587.48 10172.32,1580.39 C61_A4.1@10196.13,1580.39
VC14_A1: C30_A1.2 C37_A1.1 R51_A1.2 R199_A1.1 R205_A1.2 U1_A1.11 | length 2175.9
  Top Layer w8: U1_A1.11@3160.25,1531.37 3160.25,1605.91 3178.02,1623.67 3178.02,1648.14 3178.47,1648.59 3178.47,1667.54 3178.02,1668 3178.02,1692.85 3178.45,1692.85 3186.45,1700.85 C30_A1.2@3186.45,1743.6 3185.39,1743.6 3177.58,1751.41 R199_A1.1@3177.58,1795.9 3177.58,1844.49 R205_A1.2@3180.18,1847.08 3183.84,1847.08 3199.53,1862.77 3199.53,1863.81 3235.32,1899.61 3303.37,1899.61 3313.22,1909.45 3348.86,1909.45 3350.28,1910.87 3375.07,1910.87 3401.5,1937.29 3401.5,3196.72 3483.75,3278.97 3527.37,3278.97 3609.62,3361.22 3609.62,3372.52 3618.99,3381.89 R51_A1.2@3642.8,3381.89
VC14_A2: C30_A2.2 C37_A2.1 R51_A2.2 R199_A2.1 R205_A2.2 U1_A2.11 | length 2178
  Top Layer w8: U1_A2.11@5455.27,1531.37 5455.27,1605.91 5475.62,1626.26 5475.62,1665.41 5473.03,1668 5473.03,1692.85 5473.46,1692.85 5481.47,1700.85 C30_A2.2@5481.47,1743.6 5480.41,1743.6 5472.6,1751.41 R199_A2.1@5472.6,1795.9 5472.6,1844.49 R205_A2.2@5475.19,1847.08 5478.86,1847.08 5494.55,1862.77 5494.55,1863.81 5530.34,1899.61 5598.39,1899.61 5608.23,1909.45 5643.88,1909.45 5645.29,1910.87 5670.09,1910.87 5696.51,1937.29 5696.51,3196.72 5778.76,3278.97 5822.38,3278.97 5904.63,3361.22 5904.63,3372.52 5914,3381.89 R51_A2.2@5937.82,3381.89 ; C37_A2.1@5473.22,1693.04 C37_A2.1@5473.41,1692.85
VC14_A3: C30_A3.2 C37_A3.1 R51_A3.2 R199_A3.1 R205_A3.2 U1_A3.11 | length 2176.6
  Top Layer w8: U1_A3.11@7791.87,1534.57 7791.87,1609.11 7810.81,1628.06 7810.81,1670.75 7809.63,1671.94 7809.63,1695.62 7810.06,1696.05 7818.06,1704.06 C30_A3.2@7818.06,1746.8 7817,1746.8 7809.19,1754.62 R199_A3.1@7809.19,1799.11 7809.19,1847.7 R205_A3.2@7811.79,1850.29 7815.46,1850.29 7831.14,1865.98 7831.14,1867.02 7866.94,1902.81 7934.99,1902.81 7944.83,1912.66 7980.47,1912.66 7981.89,1914.07 8006.69,1914.07 8033.11,1940.5 8033.11,3199.93 8115.36,3282.18 8158.98,3282.18 8241.23,3364.43 8241.23,3375.73 8250.6,3385.1 R51_A3.2@8274.41,3385.1 ; C37_A3.1@7809.82,1696.25 C37_A3.1@7810.01,1696.05
VC14_A4: C30_A4.2 C37_A4.1 R51_A4.2 R199_A4.1 R205_A4.2 U1_A4.11 | length 2176.9
  Top Layer w8: U1_A4.11@10112.1,1531.37 10112.1,1605.91 10131.13,1624.93 10131.13,1666.73 10129.86,1668 10129.86,1692.85 10130.29,1692.85 10138.29,1700.85 C30_A4.2@10138.29,1743.6 10137.23,1743.6 10129.42,1751.41 R199_A4.1@10129.42,1795.9 10129.42,1844.49 R205_A4.2@10132.02,1847.08 10135.69,1847.08 10151.37,1862.77 10151.37,1863.81 10187.17,1899.61 10255.22,1899.61 10265.06,1909.45 10300.7,1909.45 10302.12,1910.87 10326.92,1910.87 10353.34,1937.29 10353.34,3196.72 10435.59,3278.97 10479.21,3278.97 10561.46,3361.22 10561.46,3372.52 10570.83,3381.89 R51_A4.2@10594.64,3381.89 ; C37_A4.1@10130.05,1693.04 C37_A4.1@10130.24,1692.85
VC15_A1: C22_A1.2 C30_A1.1 R41_A1.2 R200_A1.2 R205_A1.1 U1_A1.9 | length 2312
  Top Layer w8: U1_A1.9@3199.62,1531.37 3199.62,1576.96 3203.16,1580.5 3203.16,1601.09 3227.88,1625.81 3227.88,1653.3 3238.29,1663.71 C22_A1.2@3238.27,1683.78 3235.66,1686.39 C30_A1.1@3235.66,1743.6 ; C30_A1.1@3233.69,1743.6 C30_A1.1@3235.66,1743.6 ; R41_A1.2@3699.67,3381.89 3691.86,3374.08 3691.86,3354.23 3687.77,3350.14 3687.77,3269.86 3699.82,3257.82 3699.82,1927.9 3695.07,1923.16 3409.82,1923.16 3381.65,1894.99 3365.04,1894.99 3363.62,1893.57 3319.79,1893.57 3309.95,1883.73 3285.15,1883.73 3264.97,1863.55 3264.97,1857.15 3254.9,1847.08 R205_A1.1@3227.42,1847.08 3227.42,1803.71 3235.23,1795.9 R200_A1.2@3235.66,1795.9 C30_A1.1@3235.66,1743.6
VC15_A2: C22_A2.2 C30_A2.1 R41_A2.2 R200_A2.2 R205_A2.1 U1_A2.9 | length 2312
  Top Layer w8: U1_A2.9@5494.64,1531.37 5494.64,1576.96 5498.18,1580.5 5498.18,1601.09 5522.9,1625.81 5522.9,1653.3 5533.31,1663.71 C22_A2.2@5533.29,1683.78 5530.68,1686.39 C30_A2.1@5530.68,1743.6 ; C30_A2.1@5528.71,1743.6 C30_A2.1@5530.68,1743.6 ; R41_A2.2@5994.68,3381.89 5986.87,3374.08 5986.87,3354.23 5982.79,3350.14 5982.79,3269.86 5994.83,3257.82 5994.83,1927.9 5990.09,1923.16 5704.83,1923.16 5676.66,1894.99 5660.06,1894.99 5658.64,1893.57 5614.81,1893.57 5604.97,1883.73 5580.17,1883.73 5559.98,1863.55 5559.98,1857.15 5549.92,1847.08 R205_A2.1@5522.44,1847.08 5522.44,1803.71 5530.25,1795.9 R200_A2.2@5530.68,1795.9 C30_A2.1@5530.68,1743.6
VC15_A3: C22_A3.2 C30_A3.1 R41_A3.2 R200_A3.2 R205_A3.1 U1_A3.9 | length 2312
  Top Layer w8: U1_A3.9@7831.24,1534.57 7831.24,1580.17 7834.77,1583.7 7834.77,1604.29 7859.49,1629.01 7859.49,1656.51 7869.91,1666.92 C22_A3.2@7869.89,1686.99 7867.28,1689.6 C30_A3.1@7867.28,1746.8 ; C30_A3.1@7865.31,1746.8 C30_A3.1@7867.28,1746.8 ; R41_A3.2@8331.28,3385.1 8323.47,3377.29 8323.47,3357.43 8319.39,3353.35 8319.39,3273.07 8331.43,3261.03 8331.43,1931.11 8326.69,1926.37 8041.43,1926.37 8013.26,1898.2 7996.65,1898.2 7995.24,1896.78 7951.4,1896.78 7941.56,1886.94 7916.77,1886.94 7896.58,1866.75 7896.58,1860.36 7886.51,1850.29 R205_A3.1@7859.03,1850.29 7859.03,1806.92 7866.84,1799.11 R200_A3.2@7867.28,1799.11 C30_A3.1@7867.28,1746.8
VC15_A4: C22_A4.2 C30_A4.1 R41_A4.2 R200_A4.2 R205_A4.1 U1_A4.9 | length 2312
  Top Layer w8: U1_A4.9@10151.47,1531.37 10151.47,1576.96 10155,1580.5 10155,1601.09 10179.72,1625.81 10179.72,1653.3 10190.14,1663.71 C22_A4.2@10190.12,1683.78 10187.51,1686.39 C30_A4.1@10187.51,1743.6 ; C30_A4.1@10185.54,1743.6 C30_A4.1@10187.51,1743.6 ; R41_A4.2@10651.51,3381.89 10643.7,3374.08 10643.7,3354.23 10639.62,3350.14 10639.62,3269.86 10651.66,3257.82 10651.66,1927.9 10646.92,1923.16 10361.66,1923.16 10333.49,1894.99 10316.88,1894.99 10315.47,1893.57 10271.63,1893.57 10261.79,1883.73 10237,1883.73 10216.81,1863.55 10216.81,1857.15 10206.74,1847.08 R205_A4.1@10179.26,1847.08 10179.26,1803.71 10187.07,1795.9 R200_A4.2@10187.51,1795.9 C30_A4.1@10187.51,1743.6
VC16_A1: C14_A1.2 C22_A1.1 R37_A1.2 R200_A1.1 R206_A1.2 U1_A1.7 | length 2295.9
  Top Layer w8: U1_A1.7@3239,1531.37 3239,1579.25 3247.43,1587.68 3247.43,1590.78 3253.96,1597.3 3253.96,1600.03 3276.03,1622.11 3276.03,1675.97 3283.85,1683.78 C22_A1.1@3285.52,1683.78 ; C22_A1.1@3282.91,1683.78 3282.91,1729.27 C14_A1.2@3290.72,1737.08 ; C14_A1.2@3293.17,1737.08 C14_A1.2@3290.72,1737.08 ; R37_A1.2@3756.54,3381.89 3732.72,3381.89 3724.21,3373.37 3724.21,3267.29 3715.69,3258.78 3715.69,1921.32 3701.65,1907.29 3416.39,1907.29 3388.22,1879.12 3371.62,1879.12 3370.2,1877.7 3326.37,1877.7 3312.48,1863.81 3312.48,1862.77 3296.79,1847.08 3290.72,1847.08 3282.91,1839.27 R200_A1.1@3282.91,1795.9 3282.91,1744.89 C14_A1.2@3290.72,1737.08
VC16_A2: C14_A2.2 C22_A2.1 R37_A2.2 R200_A2.1 R206_A2.2 U1_A2.7 | length 2295.9
  Top Layer w8: U1_A2.7@5534.01,1531.37 5534.01,1579.25 5542.44,1587.68 5542.44,1590.78 5548.97,1597.3 5548.97,1600.03 5571.05,1622.11 5571.05,1675.97 5578.86,1683.78 C22_A2.1@5580.53,1683.78 ; C22_A2.1@5577.92,1683.78 5577.92,1729.27 C14_A2.2@5585.73,1737.08 ; C14_A2.2@5588.19,1737.08 C14_A2.2@5585.73,1737.08 ; R37_A2.2@6051.55,3381.89 6027.74,3381.89 6019.22,3373.37 6019.22,3267.29 6010.71,3258.78 6010.71,1921.32 5996.67,1907.29 5711.41,1907.29 5683.24,1879.12 5666.63,1879.12 5665.22,1877.7 5621.38,1877.7 5607.5,1863.81 5607.5,1862.77 5591.81,1847.08 5585.73,1847.08 5577.92,1839.27 R200_A2.1@5577.92,1795.9 5577.92,1744.89 C14_A2.2@5585.73,1737.08
VC16_A3: C14_A3.2 C22_A3.1 R37_A3.2 R200_A3.1 R206_A3.2 U1_A3.7 | length 2295.9
  Top Layer w8: U1_A3.7@7870.61,1534.57 7870.61,1582.46 7879.04,1590.89 7879.04,1593.98 7885.57,1600.51 7885.57,1603.24 7907.65,1625.32 7907.65,1679.18 7915.46,1686.99 C22_A3.1@7917.13,1686.99 ; C22_A3.1@7914.52,1686.99 7914.52,1732.48 C14_A3.2@7922.33,1740.29 ; C14_A3.2@7924.79,1740.29 C14_A3.2@7922.33,1740.29 ; R37_A3.2@8388.15,3385.1 8364.34,3385.1 8355.82,3376.58 8355.82,3270.5 8347.3,3261.98 8347.3,1924.53 8333.26,1910.49 8048,1910.49 8019.84,1882.33 8003.23,1882.33 8001.81,1880.91 7957.98,1880.91 7944.09,1867.02 7944.09,1865.98 7928.41,1850.29 7922.33,1850.29 7914.52,1842.48 R200_A3.1@7914.52,1799.11 7914.52,1748.1 C14_A3.2@7922.33,1740.29
VC16_A4: C14_A4.2 C22_A4.1 R37_A4.2 R200_A4.1 R206_A4.2 U1_A4.7 | length 2295.9
  Top Layer w8: U1_A4.7@10190.84,1531.37 10190.84,1579.25 10199.27,1587.68 10199.27,1590.78 10205.8,1597.3 10205.8,1600.03 10227.88,1622.11 10227.88,1675.97 10235.69,1683.78 C22_A4.1@10237.36,1683.78 ; C22_A4.1@10234.75,1683.78 10234.75,1729.27 C14_A4.2@10242.56,1737.08 ; C14_A4.2@10245.02,1737.08 C14_A4.2@10242.56,1737.08 ; R37_A4.2@10708.38,3381.89 10684.57,3381.89 10676.05,3373.37 10676.05,3267.29 10667.53,3258.78 10667.53,1921.32 10653.49,1907.29 10368.23,1907.29 10340.07,1879.12 10323.46,1879.12 10322.04,1877.7 10278.21,1877.7 10264.32,1863.81 10264.32,1862.77 10248.64,1847.08 10242.56,1847.08 10234.75,1839.27 R200_A4.1@10234.75,1795.9 10234.75,1744.89 C14_A4.2@10242.56,1737.08
VC17_A1: C7_A1.2 C14_A1.1 R26_A1.2 R201_A1.2 R206_A1.1 U1_A1.5 | length 2290.6
  Top Layer w8: U1_A1.5@3278.37,1531.37 3280.27,1533.27 3280.27,1572.8 3282.08,1574.61 3282.08,1577.7 3287.7,1583.32 3287.7,1586.05 3315.79,1614.13 3315.79,1616.67 3337.42,1638.3 3337.42,1641.53 3345.82,1649.93 3345.82,1683.81 3346.22,1683.81 C7_A1.2@3346.47,1683.55 ; C14_A1.1@3340.42,1737.08 3346.01,1742.67 3346.01,1786.96 3340.1,1792.86 R206_A1.1@3340.1,1847.08 3365.62,1847.08 3371.24,1852.7 3371.24,1856.29 3378.19,1863.24 3394.8,1863.24 3422.97,1891.41 3720.38,1891.41 3731.56,1902.6 3731.56,2848.54 3742.7,2859.67 3741.25,2861.12 3741.25,3210.54 3768.33,3237.62 3768.33,3262.03 3780.22,3273.92 3780.22,3372.52 3789.59,3381.89 R26_A1.2@3813.4,3381.89 ; C7_A1.2@3346.01,1683.55 C14_A1.1@3346.01,1733.32
VC17_A2: C7_A2.2 C14_A2.1 R26_A2.2 R201_A2.2 R206_A2.1 U1_A2.5 | length 2290.6
  Top Layer w8: U1_A2.5@5573.38,1531.37 5575.29,1533.27 5575.29,1572.8 5577.1,1574.61 5577.1,1577.7 5582.72,1583.32 5582.72,1586.05 5610.8,1614.13 5610.8,1616.67 5632.44,1638.3 5632.44,1641.53 5640.83,1649.93 5640.83,1683.81 5641.23,1683.81 C7_A2.2@5641.49,1683.55 ; C14_A2.1@5635.43,1737.08 5641.02,1742.67 5641.02,1786.96 5635.12,1792.86 R206_A2.1@5635.12,1847.08 5660.63,1847.08 5666.25,1852.7 5666.25,1856.29 5673.21,1863.24 5689.81,1863.24 5717.98,1891.41 6015.39,1891.41 6026.58,1902.6 6026.58,2848.54 6037.71,2859.67 6036.26,2861.12 6036.26,3210.54 6063.34,3237.62 6063.34,3262.03 6075.24,3273.92 6075.24,3372.52 6084.61,3381.89 R26_A2.2@6108.42,3381.89 ; C7_A2.2@5641.02,1683.55 C14_A2.1@5641.02,1733.32
VC17_A3: C7_A3.2 C14_A3.1 R26_A3.2 R201_A3.2 R206_A3.1 U1_A3.5 | length 2290.6
  Top Layer w8: U1_A3.5@7909.98,1534.57 7911.88,1536.48 7911.88,1576.01 7913.69,1577.82 7913.69,1580.91 7919.32,1586.53 7919.32,1589.26 7947.4,1617.34 7947.4,1619.88 7969.03,1641.51 7969.03,1644.74 7977.43,1653.14 7977.43,1687.01 7977.83,1687.01 C7_A3.2@7978.09,1686.76 ; C14_A3.1@7972.03,1740.29 7977.62,1745.87 7977.62,1790.16 7971.71,1796.07 R206_A3.1@7971.71,1850.29 7997.23,1850.29 8002.85,1855.91 8002.85,1859.5 8009.8,1866.45 8026.41,1866.45 8054.58,1894.62 8351.99,1894.62 8363.18,1905.81 8363.18,2851.75 8374.31,2862.88 8372.86,2864.33 8372.86,3213.75 8399.94,3240.83 8399.94,3265.24 8411.83,3277.13 8411.83,3375.73 8421.2,3385.1 R26_A3.2@8445.02,3385.1 ; C7_A3.2@7977.62,1686.76 C14_A3.1@7977.62,1736.53
VC17_A4: C7_A4.2 C14_A4.1 R26_A4.2 R201_A4.2 R206_A4.1 U1_A4.5 | length 2290.6
  Top Layer w8: U1_A4.5@10230.21,1531.37 10232.11,1533.27 10232.11,1572.8 10233.92,1574.61 10233.92,1577.7 10239.55,1583.32 10239.55,1586.05 10267.63,1614.13 10267.63,1616.67 10289.26,1638.3 10289.26,1641.53 10297.66,1649.93 10297.66,1683.81 10298.06,1683.81 C7_A4.2@10298.32,1683.55 ; C14_A4.1@10292.26,1737.08 10297.85,1742.67 10297.85,1786.96 10291.94,1792.86 R206_A4.1@10291.94,1847.08 10317.46,1847.08 10323.08,1852.7 10323.08,1856.29 10330.03,1863.24 10346.64,1863.24 10374.81,1891.41 10672.22,1891.41 10683.41,1902.6 10683.41,2848.54 10694.54,2859.67 10693.09,2861.12 10693.09,3210.54 10720.17,3237.62 10720.17,3262.03 10732.06,3273.92 10732.06,3372.52 10741.43,3381.89 R26_A4.2@10765.25,3381.89 ; C7_A4.2@10297.85,1683.55 C14_A4.1@10297.85,1733.32
VC18_A1: C7_A1.1 D1_A1.2 R19_A1.2 R201_A1.1 R207_A1.2 U1_A1.3 | length 2622.7
  Top Layer w8: U1_A1.3@3317.74,1531.37 3319.64,1533.27 3319.64,1567.53 3321.45,1569.35 3321.45,1572.07 3340.02,1590.64 3345.23,1590.64 3366.92,1612.33 3383.89,1612.33 3393.06,1621.5 C7_A1.1@3393.06,1683.81 ; R201_A1.1@3392.57,1787.63 R201_A1.1@3398.19,1793.25 ; C7_A1.1@3393.46,1692.33 3434.48,1692.33 v1(3434.69,1692.54) ; R19_A1.2@3870.27,3381.89 3846.46,3381.89 3837.09,3372.52 3837.09,3281.15 3759.09,3203.15 3759.09,2850.84 3747.44,2839.18 3747.44,1896.02 3726.95,1875.54 3704.06,1875.54 3698.21,1869.69 3599.23,1869.69 3598.15,1870.77 3424.77,1870.77 3417.82,1863.81 3417.82,1854.58 3402.8,1839.56 R207_A1.2@3398.86,1839.56 3398.19,1838.9 R201_A1.1@3398.19,1793.25 ; C7_A1.1@3393.72,1683.55 C7_A1.1@3393.72,1690.71 ; C7_A1.1@3393.72,1683.55 C7_A1.1@3393.72,1690.71 ; C7_A1.1@3393.72,1683.55 C7_A1.1@3393.72,1690.71 ; C7_A1.1@3393.72,1690.71 3392.96,1690.71 3392.3,1691.36 3392.3,1787.36 R201_A1.1@3398.19,1793.25
  Bottom Layer w20: v1(3434.69,1692.54) 3470.29,1656.93 3471.21,1656.93 3472.16,1655.98 3548.41,1655.98 3605.09,1599.3 3645.66,1599.3 D1_A1.2@3662.74,1582.22
VC18_A2: C7_A2.1 D1_A2.2 R19_A2.2 R201_A2.1 R207_A2.2 U1_A2.3 | length 2622.7
  Top Layer w8: U1_A2.3@5612.75,1531.37 5614.66,1533.27 5614.66,1567.53 5616.47,1569.35 5616.47,1572.07 5635.04,1590.64 5640.25,1590.64 5661.94,1612.33 5678.91,1612.33 5688.08,1621.5 C7_A2.1@5688.08,1683.81 ; R201_A2.1@5687.59,1787.63 R201_A2.1@5693.21,1793.25 ; C7_A2.1@5688.47,1692.33 5729.49,1692.33 v1(5729.7,1692.54) ; R19_A2.2@6165.29,3381.89 6141.48,3381.89 6132.1,3372.52 6132.1,3281.15 6054.11,3203.15 6054.11,2850.84 6042.45,2839.18 6042.45,1896.02 6021.97,1875.54 5999.07,1875.54 5993.22,1869.69 5894.24,1869.69 5893.16,1870.77 5719.79,1870.77 5712.83,1863.81 5712.83,1854.58 5697.81,1839.56 R207_A2.2@5693.87,1839.56 5693.21,1838.9 R201_A2.1@5693.21,1793.25 ; C7_A2.1@5688.73,1683.55 C7_A2.1@5688.73,1690.71 ; C7_A2.1@5688.73,1683.55 C7_A2.1@5688.73,1690.71 ; C7_A2.1@5688.73,1683.55 C7_A2.1@5688.73,1690.71 ; C7_A2.1@5688.73,1690.71 5687.97,1690.71 5687.32,1691.36 5687.32,1787.36 R201_A2.1@5693.21,1793.25
  Bottom Layer w20: v1(5729.7,1692.54) 5765.31,1656.93 5766.22,1656.93 5767.17,1655.98 5843.42,1655.98 5900.1,1599.3 5940.68,1599.3 D1_A2.2@5957.76,1582.22
VC18_A3: C7_A3.1 D1_A3.2 R19_A3.2 R201_A3.1 R207_A3.2 U1_A3.3 | length 2622.7
  Top Layer w8: U1_A3.3@7949.35,1534.57 7951.25,1536.48 7951.25,1570.74 7953.06,1572.55 7953.06,1575.28 7971.63,1593.85 7976.85,1593.85 7998.54,1615.54 8015.51,1615.54 8024.67,1624.7 C7_A3.1@8024.67,1687.01 ; R201_A3.1@8024.19,1790.84 R201_A3.1@8029.81,1796.46 ; C7_A3.1@8025.07,1695.54 8066.09,1695.54 v1(8066.3,1695.74) ; R19_A3.2@8501.88,3385.1 8478.07,3385.1 8468.7,3375.73 8468.7,3284.36 8390.7,3206.36 8390.7,2854.04 8379.05,2842.39 8379.05,1899.23 8358.57,1878.75 8335.67,1878.75 8329.82,1872.89 8230.84,1872.89 8229.76,1873.98 8056.38,1873.98 8049.43,1867.02 8049.43,1857.79 8034.41,1842.77 R207_A3.2@8030.47,1842.77 8029.81,1842.1 R201_A3.1@8029.81,1796.46 ; C7_A3.1@8025.33,1686.76 C7_A3.1@8025.33,1693.92 ; C7_A3.1@8025.33,1686.76 C7_A3.1@8025.33,1693.92 ; C7_A3.1@8025.33,1686.76 C7_A3.1@8025.33,1693.92 ; C7_A3.1@8025.33,1693.92 8024.57,1693.92 8023.92,1694.57 8023.92,1790.57 R201_A3.1@8029.81,1796.46
  Bottom Layer w20: v1(8066.3,1695.74) 8101.91,1660.14 8102.82,1660.14 8103.77,1659.19 8180.02,1659.19 8236.7,1602.51 8277.27,1602.51 D1_A3.2@8294.36,1585.42
VC18_A4: C7_A4.1 D1_A4.2 R19_A4.2 R201_A4.1 R207_A4.2 U1_A4.3 | length 2622.7
  Top Layer w8: U1_A4.3@10269.58,1531.37 10271.48,1533.27 10271.48,1567.54 10273.29,1569.35 10273.29,1572.07 10291.86,1590.64 10297.08,1590.64 10318.77,1612.33 10335.74,1612.33 10344.9,1621.5 C7_A4.1@10344.9,1683.81 ; R201_A4.1@10344.42,1787.63 R201_A4.1@10350.04,1793.25 ; C7_A4.1@10345.3,1692.33 10386.32,1692.33 v1(10386.53,1692.54) ; R19_A4.2@10822.11,3381.89 10798.3,3381.89 10788.93,3372.52 10788.93,3281.15 10710.93,3203.15 10710.93,2850.84 10699.28,2839.18 10699.28,1896.02 10678.79,1875.54 10655.9,1875.54 10650.05,1869.69 10551.07,1869.69 10549.99,1870.77 10376.61,1870.77 10369.66,1863.81 10369.66,1854.58 10354.64,1839.56 R207_A4.2@10350.7,1839.56 10350.04,1838.9 R201_A4.1@10350.04,1793.25 ; C7_A4.1@10345.56,1683.55 C7_A4.1@10345.56,1690.71 ; C7_A4.1@10345.56,1683.55 C7_A4.1@10345.56,1690.71 ; C7_A4.1@10345.56,1683.55 C7_A4.1@10345.56,1690.71 ; C7_A4.1@10345.56,1690.71 10344.8,1690.71 10344.15,1691.36 10344.15,1787.36 R201_A4.1@10350.04,1793.25
  Bottom Layer w20: v1(10386.53,1692.54) 10422.14,1656.93 10423.05,1656.93 10424,1655.98 10500.25,1655.98 10556.93,1599.3 10597.5,1599.3 D1_A4.2@10614.59,1582.22
VCC5V: C182.1 C183.1 C184.1 CO1.1 J12.1 J13.2 L3.2 R218.2 R237.1 R246.1 R247.1 | length 2777.1
  Top Layer w8: R247.1@866.53,826.47 R247.1@871.88,831.82
  Top Layer w20: R237.1@231.03,2172.36 231.03,2171.38 258.78,2143.63 258.78,2141.66 272.92,2127.52 443.55,2127.52 496.86,2180.83 L3.2@496.86,2206.04 ; L3.2@496.86,2257.6 L3.2@496.86,2206.04 ; CO1.1@676.04,2179.27 CO1.1@683.88,2179.27 ; CO1.1@676.04,2180.61 585.31,2180.61 522.29,2180.61 L3.2@496.86,2206.04 ; J12.1@709.8,1931.31 709.36,1931.75 J13.2@709.36,2056.51 709.36,2153.78 CO1.1@683.88,2179.27 ; C184.1@744.42,2193.5 C184.1@744.42,2194.83 ; C184.1@799.53,2182.8 834.96,2182.8 C184.1@807.09,2182.8 ; C184.1@807.09,2185.04 801.31,2179.27 CO1.1@683.88,2179.27 ; R218.2@830.92,2488.31 830.92,2443.74 842.77,2431.89 C182.1@843.75,2431.89 844.73,2431.89 888.45,2388.17 888.45,2284.95 862.52,2259.02 862.52,2216.01 856.46,2209.95 856.46,2204.29 C184.1@840.36,2188.19 ; C184.1@839.78,2181.63 839.78,2177.98 856.46,2161.3 897.75,2161.3 R246.1@905.51,2153.54 ; v1(866.53,777.52) 866.91,777.9 866.91,826.09 R247.1@866.53,826.47
  Bottom Layer w20: J12.1@709.8,1931.31 739.08,1902.03 739.08,1615.06 684.11,1560.08 684.11,1022.34 866.53,839.93 v1(866.53,777.52)
VDD5: C202.1 C203.2 C204.1 C220.2 C222.1 R255.2 U7.7 U7.8 U8.8 U13.3 U13.5 | length 544.6
  Top Layer w8: 1252.32,2593.41 1260.35,2601.44 ; R255.2@1260.35,2660.04 1260.35,2648.98 1364.4,2648.98 U13.3@1364.4,2590.08 1364.4,2549.92 1386.95,2527.37 1386.95,2523.44 1394.76,2515.62 C220.2@1398.7,2515.62 ; 1364.4,2647.26 1385.14,2667.99 1385.14,2687.58 U13.5@1389.99,2692.44 C222.1@1437.65,2692.44
  Top Layer w15: U7.8@1131.9,2408.32 U7.7@1157.49,2408.32
  Top Layer w20: C204.1@1161.18,2513.47 C204.1@1174.53,2500.13 ; 1200.79,2413.91 1258.39,2413.91 1260.2,2415.72 U8.8@1260.2,2421.91 ; 1260.35,2601.44 R255.2@1260.35,2648.98 ; C222.1@1446.1,2691.61 1446.1,2687.68 C222.1@1447.91,2685.87
VStage1_5V: C187.2 C189.1 C190.2 U9.9 U9.10 U9.11 U10.1 U10.2 U10.3 U11.1 U11.7 U12.10 U12.16 | length 255.1
  Top Layer w8: U11.1@1386.71,914.08 1388.18,915.56 1431.09,915.56 v1(1432.56,917.03) 1434.42,915.18 1484.36,915.18 U12.16@1486.22,913.32 ; U11.7@1386.71,1214.08 1387.08,1213.7 1434.74,1213.7 v1(1435.11,1213.32) U12.10@1486.22,1213.32 ; C189.1@1585.28,1584.65 C189.1@1600.28,1569.64
  Top Layer w20: v1(1437.01,1318.9) U9.9@1437.01,1347.44
  Bottom Layer w20: v1(1432.56,917.03) v1@1433.84,918.31 ; v1@1434.19,1213.7 1434.46,1213.43 v1@1434.46,1212.66 ; v1@1437.01,1318.67 v1(1437.01,1318.9)
  other v1: 1505.91,1515.89
VStage2_5V: C211.2 C212.1 C217.2 Q7.1 R258.2 U10.9 U10.10 U10.11 U12.1 U12.7 | length 693.8
  Top Layer w8: v1(1940.99,1290.66) 1940.99,1294.45 1950.95,1304.41 1950.95,1337.36 1955.02,1341.43 U10.9@1978.48,1341.43 ; U10.9@1975.37,1341.43 1978.35,1344.41 1978.35,1366.88 U10.10@1978.48,1367.02 1978.35,1367.15 1978.35,1392.48 U10.11@1978.48,1392.61
  Top Layer w20: U12.1@1870.08,913.32 1890.75,913.32 1919.29,884.78 1970.1,884.78 1984.41,899.09 1984.41,900.75 C217.2@2008.37,924.7 ; U12.7@1870.08,1213.32 1890.75,1213.32 1910.44,1193.63 1916.61,1193.63 v1(1919.29,1190.94) 1949.25,1160.99 1958.78,1160.99 2007.87,1111.89 R258.2@2007.87,1102.36 ; C212.1@1988.19,1290.63 C212.1@1994.69,1290.63 ; Q7.1@2006.14,1065.98 R258.2@2006.14,1102.36 ; C217.2@2007.87,925.2 C217.2@2009.84,925.2 2010.83,925.2 2019.53,933.9 2019.53,936.85 2039.47,956.79 2039.47,1031.72 Q7.1@2011.18,1060
pads on no net: FID1.1 FID2.1 FID3.1 H1.1 H2.1 H3.1 H4.1 H5.0 H6.0 H7.0 H8.0 H9.0 H10.0 H11.0 H12.0 J1_A1.9 J1_A2.9 J1_A3.9 J1_A4.9 J2_A1.9 J2_A1.29 J2_A1.41 J2_A1.42 J2_A2.9 J2_A2.29 J2_A2.41 J2_A2.42 J2_A3.9 J2_A3.29 J2_A3.41 J2_A3.42 J2_A4.9 J2_A4.29 J2_A4.41 J2_A4.42 J5.9 J5.10 J7.3 J7.4 J7.MH1 J7.MH2 J8.1 J8.2 J8.MH1 J8.MH2 J11.6 J11.8 LBL1.0 S1. S2. T1.2 T5.2 U2_A1.7 U2_A2.7 U2_A3.7 U2_A4.7 U3_A1.7 U3_A2.7 U3_A3.7 U3_A4.7 U6.5 U6.7@91.18,2265.47 U6.7@91.18,2300.91 U11.6 U11.11 U12.6 U12.11 U14.1 U14.3 U14.5
copper on no net:
  other v3: 519.07,3957.68 1048.6,3957.68 519.07,4042.32 1048.6,4042.32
